VERSION 5.8 ;
BUSBITCHARS "[]" ;
DIVIDERCHAR "/" ;
UNITS
    DATABASE MICRONS 1000 ;
END UNITS

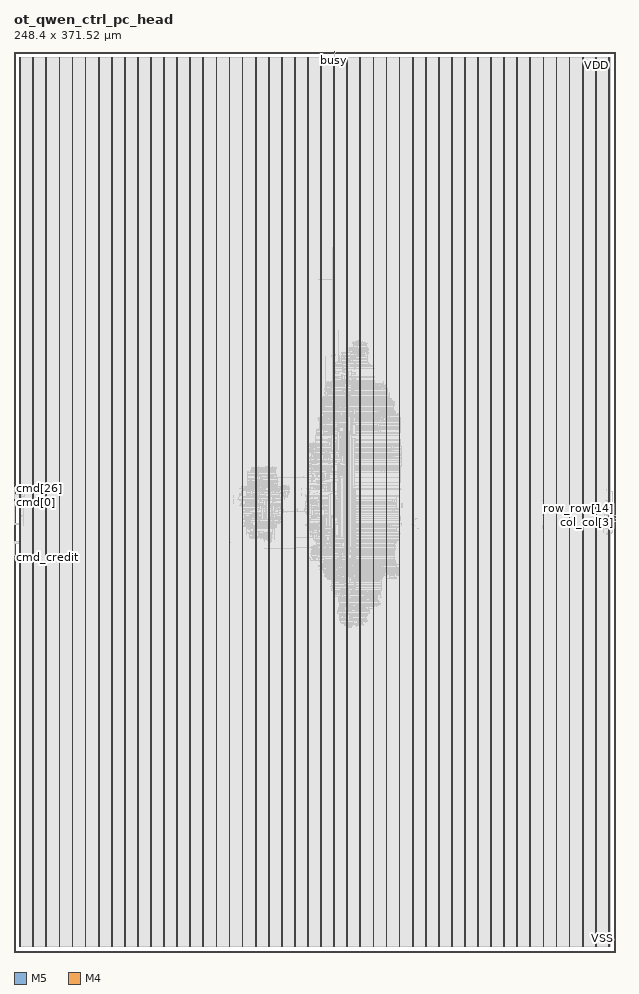
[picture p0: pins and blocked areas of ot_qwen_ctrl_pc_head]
MACRO ot_qwen_ctrl_pc_head
  FOREIGN ot_qwen_ctrl_pc_head 0 0 ;
  CLASS BLOCK ;
  SIZE 248.4 BY 371.52 ;
  PIN busy
    DIRECTION OUTPUT ;
    USE SIGNAL ;
    PORT
      LAYER M5 ;
        RECT  132.144 371.436 132.168 371.52 ;
    END
  END busy
  PIN clk
    DIRECTION INPUT ;
    USE SIGNAL ;
    PORT
      LAYER M5 ;
        RECT  132.24 371.436 132.264 371.52 ;
    END
  END clk
  PIN cmd[0]
    DIRECTION INPUT ;
    USE SIGNAL ;
    PORT
      LAYER M4 ;
        RECT  0 185.712 0.084 185.736 ;
    END
  END cmd[0]
  PIN cmd[10]
    DIRECTION INPUT ;
    USE SIGNAL ;
    PORT
      LAYER M4 ;
        RECT  0 186.672 0.084 186.696 ;
    END
  END cmd[10]
  PIN cmd[11]
    DIRECTION INPUT ;
    USE SIGNAL ;
    PORT
      LAYER M4 ;
        RECT  0 186.768 0.084 186.792 ;
    END
  END cmd[11]
  PIN cmd[12]
    DIRECTION INPUT ;
    USE SIGNAL ;
    PORT
      LAYER M4 ;
        RECT  0 186.864 0.084 186.888 ;
    END
  END cmd[12]
  PIN cmd[13]
    DIRECTION INPUT ;
    USE SIGNAL ;
    PORT
      LAYER M4 ;
        RECT  0 186.96 0.084 186.984 ;
    END
  END cmd[13]
  PIN cmd[14]
    DIRECTION INPUT ;
    USE SIGNAL ;
    PORT
      LAYER M4 ;
        RECT  0 187.056 0.084 187.08 ;
    END
  END cmd[14]
  PIN cmd[15]
    DIRECTION INPUT ;
    USE SIGNAL ;
    PORT
      LAYER M4 ;
        RECT  0 187.152 0.084 187.176 ;
    END
  END cmd[15]
  PIN cmd[16]
    DIRECTION INPUT ;
    USE SIGNAL ;
    PORT
      LAYER M4 ;
        RECT  0 187.248 0.084 187.272 ;
    END
  END cmd[16]
  PIN cmd[17]
    DIRECTION INPUT ;
    USE SIGNAL ;
    PORT
      LAYER M4 ;
        RECT  0 187.344 0.084 187.368 ;
    END
  END cmd[17]
  PIN cmd[18]
    DIRECTION INPUT ;
    USE SIGNAL ;
    PORT
      LAYER M4 ;
        RECT  0 187.44 0.084 187.464 ;
    END
  END cmd[18]
  PIN cmd[19]
    DIRECTION INPUT ;
    USE SIGNAL ;
    PORT
      LAYER M4 ;
        RECT  0 187.536 0.084 187.56 ;
    END
  END cmd[19]
  PIN cmd[1]
    DIRECTION INPUT ;
    USE SIGNAL ;
    PORT
      LAYER M4 ;
        RECT  0 185.808 0.084 185.832 ;
    END
  END cmd[1]
  PIN cmd[20]
    DIRECTION INPUT ;
    USE SIGNAL ;
    PORT
      LAYER M4 ;
        RECT  0 187.632 0.084 187.656 ;
    END
  END cmd[20]
  PIN cmd[21]
    DIRECTION INPUT ;
    USE SIGNAL ;
    PORT
      LAYER M4 ;
        RECT  0 187.728 0.084 187.752 ;
    END
  END cmd[21]
  PIN cmd[22]
    DIRECTION INPUT ;
    USE SIGNAL ;
    PORT
      LAYER M4 ;
        RECT  0 187.824 0.084 187.848 ;
    END
  END cmd[22]
  PIN cmd[23]
    DIRECTION INPUT ;
    USE SIGNAL ;
    PORT
      LAYER M4 ;
        RECT  0 187.92 0.084 187.944 ;
    END
  END cmd[23]
  PIN cmd[24]
    DIRECTION INPUT ;
    USE SIGNAL ;
    PORT
      LAYER M4 ;
        RECT  0 188.016 0.084 188.04 ;
    END
  END cmd[24]
  PIN cmd[25]
    DIRECTION INPUT ;
    USE SIGNAL ;
    PORT
      LAYER M4 ;
        RECT  0 188.112 0.084 188.136 ;
    END
  END cmd[25]
  PIN cmd[26]
    DIRECTION INPUT ;
    USE SIGNAL ;
    PORT
      LAYER M4 ;
        RECT  0 188.208 0.084 188.232 ;
    END
  END cmd[26]
  PIN cmd[27]
    DIRECTION INPUT ;
    USE SIGNAL ;
    PORT
      LAYER M4 ;
        RECT  0 188.304 0.084 188.328 ;
    END
  END cmd[27]
  PIN cmd[28]
    DIRECTION INPUT ;
    USE SIGNAL ;
    PORT
      LAYER M4 ;
        RECT  0 188.4 0.084 188.424 ;
    END
  END cmd[28]
  PIN cmd[29]
    DIRECTION INPUT ;
    USE SIGNAL ;
    PORT
      LAYER M4 ;
        RECT  0 188.496 0.084 188.52 ;
    END
  END cmd[29]
  PIN cmd[2]
    DIRECTION INPUT ;
    USE SIGNAL ;
    PORT
      LAYER M4 ;
        RECT  0 185.904 0.084 185.928 ;
    END
  END cmd[2]
  PIN cmd[30]
    DIRECTION INPUT ;
    USE SIGNAL ;
    PORT
      LAYER M4 ;
        RECT  0 188.592 0.084 188.616 ;
    END
  END cmd[30]
  PIN cmd[31]
    DIRECTION INPUT ;
    USE SIGNAL ;
    PORT
      LAYER M4 ;
        RECT  0 188.688 0.084 188.712 ;
    END
  END cmd[31]
  PIN cmd[3]
    DIRECTION INPUT ;
    USE SIGNAL ;
    PORT
      LAYER M4 ;
        RECT  0 186 0.084 186.024 ;
    END
  END cmd[3]
  PIN cmd[4]
    DIRECTION INPUT ;
    USE SIGNAL ;
    PORT
      LAYER M4 ;
        RECT  0 186.096 0.084 186.12 ;
    END
  END cmd[4]
  PIN cmd[5]
    DIRECTION INPUT ;
    USE SIGNAL ;
    PORT
      LAYER M4 ;
        RECT  0 186.192 0.084 186.216 ;
    END
  END cmd[5]
  PIN cmd[6]
    DIRECTION INPUT ;
    USE SIGNAL ;
    PORT
      LAYER M4 ;
        RECT  0 186.288 0.084 186.312 ;
    END
  END cmd[6]
  PIN cmd[7]
    DIRECTION INPUT ;
    USE SIGNAL ;
    PORT
      LAYER M4 ;
        RECT  0 186.384 0.084 186.408 ;
    END
  END cmd[7]
  PIN cmd[8]
    DIRECTION INPUT ;
    USE SIGNAL ;
    PORT
      LAYER M4 ;
        RECT  0 186.48 0.084 186.504 ;
    END
  END cmd[8]
  PIN cmd[9]
    DIRECTION INPUT ;
    USE SIGNAL ;
    PORT
      LAYER M4 ;
        RECT  0 186.576 0.084 186.6 ;
    END
  END cmd[9]
  PIN cmd_credit
    DIRECTION OUTPUT ;
    USE SIGNAL ;
    PORT
      LAYER M4 ;
        RECT  0 162.96 0.084 162.984 ;
    END
  END cmd_credit
  PIN cmd_v
    DIRECTION INPUT ;
    USE SIGNAL ;
    PORT
      LAYER M4 ;
        RECT  0 163.056 0.084 163.08 ;
    END
  END cmd_v
  PIN col_bank[0]
    DIRECTION OUTPUT ;
    USE SIGNAL ;
    PORT
      LAYER M4 ;
        RECT  248.316 176.592 248.4 176.616 ;
    END
  END col_bank[0]
  PIN col_bank[1]
    DIRECTION OUTPUT ;
    USE SIGNAL ;
    PORT
      LAYER M4 ;
        RECT  248.316 176.688 248.4 176.712 ;
    END
  END col_bank[1]
  PIN col_bank[2]
    DIRECTION OUTPUT ;
    USE SIGNAL ;
    PORT
      LAYER M4 ;
        RECT  248.316 176.784 248.4 176.808 ;
    END
  END col_bank[2]
  PIN col_bank[3]
    DIRECTION OUTPUT ;
    USE SIGNAL ;
    PORT
      LAYER M4 ;
        RECT  248.316 176.88 248.4 176.904 ;
    END
  END col_bank[3]
  PIN col_bank[4]
    DIRECTION OUTPUT ;
    USE SIGNAL ;
    PORT
      LAYER M4 ;
        RECT  248.316 176.976 248.4 177 ;
    END
  END col_bank[4]
  PIN col_col[0]
    DIRECTION OUTPUT ;
    USE SIGNAL ;
    PORT
      LAYER M4 ;
        RECT  248.316 177.072 248.4 177.096 ;
    END
  END col_col[0]
  PIN col_col[1]
    DIRECTION OUTPUT ;
    USE SIGNAL ;
    PORT
      LAYER M4 ;
        RECT  248.316 177.168 248.4 177.192 ;
    END
  END col_col[1]
  PIN col_col[2]
    DIRECTION OUTPUT ;
    USE SIGNAL ;
    PORT
      LAYER M4 ;
        RECT  248.316 177.264 248.4 177.288 ;
    END
  END col_col[2]
  PIN col_col[3]
    DIRECTION OUTPUT ;
    USE SIGNAL ;
    PORT
      LAYER M4 ;
        RECT  248.316 177.36 248.4 177.384 ;
    END
  END col_col[3]
  PIN col_col[4]
    DIRECTION OUTPUT ;
    USE SIGNAL ;
    PORT
      LAYER M4 ;
        RECT  248.316 177.456 248.4 177.48 ;
    END
  END col_col[4]
  PIN col_v
    DIRECTION OUTPUT ;
    USE SIGNAL ;
    PORT
      LAYER M4 ;
        RECT  248.316 177.552 248.4 177.576 ;
    END
  END col_v
  PIN col_we
    DIRECTION OUTPUT ;
    USE SIGNAL ;
    PORT
      LAYER M4 ;
        RECT  248.316 177.648 248.4 177.672 ;
    END
  END col_we
  PIN fault
    DIRECTION OUTPUT ;
    USE SIGNAL ;
    PORT
      LAYER M5 ;
        RECT  132.336 371.436 132.36 371.52 ;
    END
  END fault
  PIN read_credit[0]
    DIRECTION INPUT ;
    USE SIGNAL ;
    PORT
      LAYER M4 ;
        RECT  0 163.152 0.084 163.176 ;
    END
  END read_credit[0]
  PIN read_credit[1]
    DIRECTION INPUT ;
    USE SIGNAL ;
    PORT
      LAYER M4 ;
        RECT  0 163.248 0.084 163.272 ;
    END
  END read_credit[1]
  PIN read_credit[2]
    DIRECTION INPUT ;
    USE SIGNAL ;
    PORT
      LAYER M4 ;
        RECT  0 163.344 0.084 163.368 ;
    END
  END read_credit[2]
  PIN row_bank[0]
    DIRECTION OUTPUT ;
    USE SIGNAL ;
    PORT
      LAYER M4 ;
        RECT  248.316 177.744 248.4 177.768 ;
    END
  END row_bank[0]
  PIN row_bank[1]
    DIRECTION OUTPUT ;
    USE SIGNAL ;
    PORT
      LAYER M4 ;
        RECT  248.316 177.84 248.4 177.864 ;
    END
  END row_bank[1]
  PIN row_bank[2]
    DIRECTION OUTPUT ;
    USE SIGNAL ;
    PORT
      LAYER M4 ;
        RECT  248.316 177.936 248.4 177.96 ;
    END
  END row_bank[2]
  PIN row_bank[3]
    DIRECTION OUTPUT ;
    USE SIGNAL ;
    PORT
      LAYER M4 ;
        RECT  248.316 178.032 248.4 178.056 ;
    END
  END row_bank[3]
  PIN row_bank[4]
    DIRECTION OUTPUT ;
    USE SIGNAL ;
    PORT
      LAYER M4 ;
        RECT  248.316 178.128 248.4 178.152 ;
    END
  END row_bank[4]
  PIN row_op[0]
    DIRECTION OUTPUT ;
    USE SIGNAL ;
    PORT
      LAYER M4 ;
        RECT  248.316 178.224 248.4 178.248 ;
    END
  END row_op[0]
  PIN row_op[1]
    DIRECTION OUTPUT ;
    USE SIGNAL ;
    PORT
      LAYER M4 ;
        RECT  248.316 178.32 248.4 178.344 ;
    END
  END row_op[1]
  PIN row_op[2]
    DIRECTION OUTPUT ;
    USE SIGNAL ;
    PORT
      LAYER M4 ;
        RECT  248.316 178.416 248.4 178.44 ;
    END
  END row_op[2]
  PIN row_row[0]
    DIRECTION OUTPUT ;
    USE SIGNAL ;
    PORT
      LAYER M4 ;
        RECT  248.316 178.512 248.4 178.536 ;
    END
  END row_row[0]
  PIN row_row[10]
    DIRECTION OUTPUT ;
    USE SIGNAL ;
    PORT
      LAYER M4 ;
        RECT  248.316 179.472 248.4 179.496 ;
    END
  END row_row[10]
  PIN row_row[11]
    DIRECTION OUTPUT ;
    USE SIGNAL ;
    PORT
      LAYER M4 ;
        RECT  248.316 179.568 248.4 179.592 ;
    END
  END row_row[11]
  PIN row_row[12]
    DIRECTION OUTPUT ;
    USE SIGNAL ;
    PORT
      LAYER M4 ;
        RECT  248.316 179.664 248.4 179.688 ;
    END
  END row_row[12]
  PIN row_row[13]
    DIRECTION OUTPUT ;
    USE SIGNAL ;
    PORT
      LAYER M4 ;
        RECT  248.316 179.76 248.4 179.784 ;
    END
  END row_row[13]
  PIN row_row[14]
    DIRECTION OUTPUT ;
    USE SIGNAL ;
    PORT
      LAYER M4 ;
        RECT  248.316 179.856 248.4 179.88 ;
    END
  END row_row[14]
  PIN row_row[15]
    DIRECTION OUTPUT ;
    USE SIGNAL ;
    PORT
      LAYER M4 ;
        RECT  248.316 179.952 248.4 179.976 ;
    END
  END row_row[15]
  PIN row_row[16]
    DIRECTION OUTPUT ;
    USE SIGNAL ;
    PORT
      LAYER M4 ;
        RECT  248.316 180.048 248.4 180.072 ;
    END
  END row_row[16]
  PIN row_row[17]
    DIRECTION OUTPUT ;
    USE SIGNAL ;
    PORT
      LAYER M4 ;
        RECT  248.316 180.144 248.4 180.168 ;
    END
  END row_row[17]
  PIN row_row[18]
    DIRECTION OUTPUT ;
    USE SIGNAL ;
    PORT
      LAYER M4 ;
        RECT  248.316 180.24 248.4 180.264 ;
    END
  END row_row[18]
  PIN row_row[1]
    DIRECTION OUTPUT ;
    USE SIGNAL ;
    PORT
      LAYER M4 ;
        RECT  248.316 178.608 248.4 178.632 ;
    END
  END row_row[1]
  PIN row_row[2]
    DIRECTION OUTPUT ;
    USE SIGNAL ;
    PORT
      LAYER M4 ;
        RECT  248.316 178.704 248.4 178.728 ;
    END
  END row_row[2]
  PIN row_row[3]
    DIRECTION OUTPUT ;
    USE SIGNAL ;
    PORT
      LAYER M4 ;
        RECT  248.316 178.8 248.4 178.824 ;
    END
  END row_row[3]
  PIN row_row[4]
    DIRECTION OUTPUT ;
    USE SIGNAL ;
    PORT
      LAYER M4 ;
        RECT  248.316 178.896 248.4 178.92 ;
    END
  END row_row[4]
  PIN row_row[5]
    DIRECTION OUTPUT ;
    USE SIGNAL ;
    PORT
      LAYER M4 ;
        RECT  248.316 178.992 248.4 179.016 ;
    END
  END row_row[5]
  PIN row_row[6]
    DIRECTION OUTPUT ;
    USE SIGNAL ;
    PORT
      LAYER M4 ;
        RECT  248.316 179.088 248.4 179.112 ;
    END
  END row_row[6]
  PIN row_row[7]
    DIRECTION OUTPUT ;
    USE SIGNAL ;
    PORT
      LAYER M4 ;
        RECT  248.316 179.184 248.4 179.208 ;
    END
  END row_row[7]
  PIN row_row[8]
    DIRECTION OUTPUT ;
    USE SIGNAL ;
    PORT
      LAYER M4 ;
        RECT  248.316 179.28 248.4 179.304 ;
    END
  END row_row[8]
  PIN row_row[9]
    DIRECTION OUTPUT ;
    USE SIGNAL ;
    PORT
      LAYER M4 ;
        RECT  248.316 179.376 248.4 179.4 ;
    END
  END row_row[9]
  PIN row_v
    DIRECTION OUTPUT ;
    USE SIGNAL ;
    PORT
      LAYER M4 ;
        RECT  248.316 180.336 248.4 180.36 ;
    END
  END row_v
  PIN rst_n
    DIRECTION INPUT ;
    USE SIGNAL ;
    PORT
      LAYER M5 ;
        RECT  132.432 371.436 132.456 371.52 ;
    END
  END rst_n
  PIN VDD
    DIRECTION INOUT ;
    USE POWER ;
    PORT
      LAYER M5 ;
        RECT  245.592 2.151 245.712 369.369 ;
        RECT  240.192 2.151 240.312 369.369 ;
        RECT  234.792 2.151 234.912 369.369 ;
        RECT  229.392 2.151 229.512 369.369 ;
        RECT  223.992 2.151 224.112 369.369 ;
        RECT  218.592 2.151 218.712 369.369 ;
        RECT  213.192 2.151 213.312 369.369 ;
        RECT  207.792 2.151 207.912 369.369 ;
        RECT  202.392 2.151 202.512 369.369 ;
        RECT  196.992 2.151 197.112 369.369 ;
        RECT  191.592 2.151 191.712 369.369 ;
        RECT  186.192 2.151 186.312 369.369 ;
        RECT  180.792 2.151 180.912 369.369 ;
        RECT  175.392 2.151 175.512 369.369 ;
        RECT  169.992 2.151 170.112 369.369 ;
        RECT  164.592 2.151 164.712 369.369 ;
        RECT  159.192 2.151 159.312 369.369 ;
        RECT  153.792 2.151 153.912 369.369 ;
        RECT  148.392 2.151 148.512 369.369 ;
        RECT  142.992 2.151 143.112 369.369 ;
        RECT  137.592 2.151 137.712 369.369 ;
        RECT  132.192 2.151 132.312 369.369 ;
        RECT  126.792 2.151 126.912 369.369 ;
        RECT  121.392 2.151 121.512 369.369 ;
        RECT  115.992 2.151 116.112 369.369 ;
        RECT  110.592 2.151 110.712 369.369 ;
        RECT  105.192 2.151 105.312 369.369 ;
        RECT  99.792 2.151 99.912 369.369 ;
        RECT  94.392 2.151 94.512 369.369 ;
        RECT  88.992 2.151 89.112 369.369 ;
        RECT  83.592 2.151 83.712 369.369 ;
        RECT  78.192 2.151 78.312 369.369 ;
        RECT  72.792 2.151 72.912 369.369 ;
        RECT  67.392 2.151 67.512 369.369 ;
        RECT  61.992 2.151 62.112 369.369 ;
        RECT  56.592 2.151 56.712 369.369 ;
        RECT  51.192 2.151 51.312 369.369 ;
        RECT  45.792 2.151 45.912 369.369 ;
        RECT  40.392 2.151 40.512 369.369 ;
        RECT  34.992 2.151 35.112 369.369 ;
        RECT  29.592 2.151 29.712 369.369 ;
        RECT  24.192 2.151 24.312 369.369 ;
        RECT  18.792 2.151 18.912 369.369 ;
        RECT  13.392 2.151 13.512 369.369 ;
        RECT  7.992 2.151 8.112 369.369 ;
        RECT  2.592 2.151 2.712 369.369 ;
    END
  END VDD
  PIN VSS
    DIRECTION INOUT ;
    USE GROUND ;
    PORT
      LAYER M5 ;
        RECT  245.4 2.137 245.52 369.383 ;
        RECT  240 2.137 240.12 369.383 ;
        RECT  234.6 2.137 234.72 369.383 ;
        RECT  229.2 2.137 229.32 369.383 ;
        RECT  223.8 2.137 223.92 369.383 ;
        RECT  218.4 2.137 218.52 369.383 ;
        RECT  213 2.137 213.12 369.383 ;
        RECT  207.6 2.137 207.72 369.383 ;
        RECT  202.2 2.137 202.32 369.383 ;
        RECT  196.8 2.137 196.92 369.383 ;
        RECT  191.4 2.137 191.52 369.383 ;
        RECT  186 2.137 186.12 369.383 ;
        RECT  180.6 2.137 180.72 369.383 ;
        RECT  175.2 2.137 175.32 369.383 ;
        RECT  169.8 2.137 169.92 369.383 ;
        RECT  164.4 2.137 164.52 369.383 ;
        RECT  159 2.137 159.12 369.383 ;
        RECT  153.6 2.137 153.72 369.383 ;
        RECT  148.2 2.137 148.32 369.383 ;
        RECT  142.8 2.137 142.92 369.383 ;
        RECT  137.4 2.137 137.52 369.383 ;
        RECT  132 2.137 132.12 369.383 ;
        RECT  126.6 2.137 126.72 369.383 ;
        RECT  121.2 2.137 121.32 369.383 ;
        RECT  115.8 2.137 115.92 369.383 ;
        RECT  110.4 2.137 110.52 369.383 ;
        RECT  105 2.137 105.12 369.383 ;
        RECT  99.6 2.137 99.72 369.383 ;
        RECT  94.2 2.137 94.32 369.383 ;
        RECT  88.8 2.137 88.92 369.383 ;
        RECT  83.4 2.137 83.52 369.383 ;
        RECT  78 2.137 78.12 369.383 ;
        RECT  72.6 2.137 72.72 369.383 ;
        RECT  67.2 2.137 67.32 369.383 ;
        RECT  61.8 2.137 61.92 369.383 ;
        RECT  56.4 2.137 56.52 369.383 ;
        RECT  51 2.137 51.12 369.383 ;
        RECT  45.6 2.137 45.72 369.383 ;
        RECT  40.2 2.137 40.32 369.383 ;
        RECT  34.8 2.137 34.92 369.383 ;
        RECT  29.4 2.137 29.52 369.383 ;
        RECT  24 2.137 24.12 369.383 ;
        RECT  18.6 2.137 18.72 369.383 ;
        RECT  13.2 2.137 13.32 369.383 ;
        RECT  7.8 2.137 7.92 369.383 ;
        RECT  2.4 2.137 2.52 369.383 ;
    END
  END VSS
  OBS
    LAYER RVTN ;
     RECT  2.16 2.16 246.24 2.295 ;
     RECT  2.16 2.565 246.24 2.835 ;
     RECT  2.16 3.105 246.24 3.375 ;
     RECT  2.16 3.645 246.24 3.915 ;
     RECT  2.16 4.185 246.24 4.455 ;
     RECT  2.16 4.725 246.24 4.995 ;
     RECT  2.16 5.265 246.24 5.535 ;
     RECT  2.16 5.805 246.24 6.075 ;
     RECT  2.16 6.345 246.24 6.615 ;
     RECT  2.16 6.885 246.24 7.155 ;
     RECT  2.16 7.425 246.24 7.695 ;
     RECT  2.16 7.965 246.24 8.235 ;
     RECT  2.16 8.505 246.24 8.775 ;
     RECT  2.16 9.045 246.24 9.315 ;
     RECT  2.16 9.585 246.24 9.855 ;
     RECT  2.16 10.125 246.24 10.395 ;
     RECT  2.16 10.665 246.24 10.935 ;
     RECT  2.16 11.205 246.24 11.475 ;
     RECT  2.16 11.745 246.24 12.015 ;
     RECT  2.16 12.285 246.24 12.555 ;
     RECT  2.16 12.825 246.24 13.095 ;
     RECT  2.16 13.365 246.24 13.635 ;
     RECT  2.16 13.905 246.24 14.175 ;
     RECT  2.16 14.445 246.24 14.715 ;
     RECT  2.16 14.985 246.24 15.255 ;
     RECT  2.16 15.525 246.24 15.795 ;
     RECT  2.16 16.065 246.24 16.335 ;
     RECT  2.16 16.605 246.24 16.875 ;
     RECT  2.16 17.145 246.24 17.415 ;
     RECT  2.16 17.685 246.24 17.955 ;
     RECT  2.16 18.225 246.24 18.495 ;
     RECT  2.16 18.765 246.24 19.035 ;
     RECT  2.16 19.305 246.24 19.575 ;
     RECT  2.16 19.845 246.24 20.115 ;
     RECT  2.16 20.385 246.24 20.655 ;
     RECT  2.16 20.925 246.24 21.195 ;
     RECT  2.16 21.465 246.24 21.735 ;
     RECT  2.16 22.005 246.24 22.275 ;
     RECT  2.16 22.545 246.24 22.815 ;
     RECT  2.16 23.085 246.24 23.355 ;
     RECT  2.16 23.625 246.24 23.895 ;
     RECT  2.16 24.165 246.24 24.435 ;
     RECT  2.16 24.705 246.24 24.975 ;
     RECT  2.16 25.245 246.24 25.515 ;
     RECT  2.16 25.785 246.24 26.055 ;
     RECT  2.16 26.325 246.24 26.595 ;
     RECT  2.16 26.865 246.24 27.135 ;
     RECT  2.16 27.405 246.24 27.675 ;
     RECT  2.16 27.945 246.24 28.215 ;
     RECT  2.16 28.485 246.24 28.755 ;
     RECT  2.16 29.025 246.24 29.295 ;
     RECT  2.16 29.565 246.24 29.835 ;
     RECT  2.16 30.105 246.24 30.375 ;
     RECT  2.16 30.645 246.24 30.915 ;
     RECT  2.16 31.185 246.24 31.455 ;
     RECT  2.16 31.725 246.24 31.995 ;
     RECT  2.16 32.265 246.24 32.535 ;
     RECT  2.16 32.805 246.24 33.075 ;
     RECT  2.16 33.345 246.24 33.615 ;
     RECT  2.16 33.885 246.24 34.155 ;
     RECT  2.16 34.425 246.24 34.695 ;
     RECT  2.16 34.965 246.24 35.235 ;
     RECT  2.16 35.505 246.24 35.775 ;
     RECT  2.16 36.045 246.24 36.315 ;
     RECT  2.16 36.585 246.24 36.855 ;
     RECT  2.16 37.125 246.24 37.395 ;
     RECT  2.16 37.665 246.24 37.935 ;
     RECT  2.16 38.205 246.24 38.475 ;
     RECT  2.16 38.745 246.24 39.015 ;
     RECT  2.16 39.285 246.24 39.555 ;
     RECT  2.16 39.825 246.24 40.095 ;
     RECT  2.16 40.365 246.24 40.635 ;
     RECT  2.16 40.905 246.24 41.175 ;
     RECT  2.16 41.445 246.24 41.715 ;
     RECT  2.16 41.985 246.24 42.255 ;
     RECT  2.16 42.525 246.24 42.795 ;
     RECT  2.16 43.065 246.24 43.335 ;
     RECT  2.16 43.605 246.24 43.875 ;
     RECT  2.16 44.145 246.24 44.415 ;
     RECT  2.16 44.685 246.24 44.955 ;
     RECT  2.16 45.225 246.24 45.495 ;
     RECT  2.16 45.765 246.24 46.035 ;
     RECT  2.16 46.305 246.24 46.575 ;
     RECT  2.16 46.845 246.24 47.115 ;
     RECT  2.16 47.385 246.24 47.655 ;
     RECT  2.16 47.925 246.24 48.195 ;
     RECT  2.16 48.465 246.24 48.735 ;
     RECT  2.16 49.005 246.24 49.275 ;
     RECT  2.16 49.545 246.24 49.815 ;
     RECT  2.16 50.085 246.24 50.355 ;
     RECT  2.16 50.625 246.24 50.895 ;
     RECT  2.16 51.165 246.24 51.435 ;
     RECT  2.16 51.705 246.24 51.975 ;
     RECT  2.16 52.245 246.24 52.515 ;
     RECT  2.16 52.785 246.24 53.055 ;
     RECT  2.16 53.325 246.24 53.595 ;
     RECT  2.16 53.865 246.24 54.135 ;
     RECT  2.16 54.405 246.24 54.675 ;
     RECT  2.16 54.945 246.24 55.215 ;
     RECT  2.16 55.485 246.24 55.755 ;
     RECT  2.16 56.025 246.24 56.295 ;
     RECT  2.16 56.565 246.24 56.835 ;
     RECT  2.16 57.105 246.24 57.375 ;
     RECT  2.16 57.645 246.24 57.915 ;
     RECT  2.16 58.185 246.24 58.455 ;
     RECT  2.16 58.725 246.24 58.995 ;
     RECT  2.16 59.265 246.24 59.535 ;
     RECT  2.16 59.805 246.24 60.075 ;
     RECT  2.16 60.345 246.24 60.615 ;
     RECT  2.16 60.885 246.24 61.155 ;
     RECT  2.16 61.425 246.24 61.695 ;
     RECT  2.16 61.965 246.24 62.235 ;
     RECT  2.16 62.505 246.24 62.775 ;
     RECT  2.16 63.045 246.24 63.315 ;
     RECT  2.16 63.585 246.24 63.855 ;
     RECT  2.16 64.125 246.24 64.395 ;
     RECT  2.16 64.665 246.24 64.935 ;
     RECT  2.16 65.205 246.24 65.475 ;
     RECT  2.16 65.745 246.24 66.015 ;
     RECT  2.16 66.285 246.24 66.555 ;
     RECT  2.16 66.825 246.24 67.095 ;
     RECT  2.16 67.365 246.24 67.635 ;
     RECT  2.16 67.905 246.24 68.175 ;
     RECT  2.16 68.445 246.24 68.715 ;
     RECT  2.16 68.985 246.24 69.255 ;
     RECT  2.16 69.525 246.24 69.795 ;
     RECT  2.16 70.065 246.24 70.335 ;
     RECT  2.16 70.605 246.24 70.875 ;
     RECT  2.16 71.145 246.24 71.415 ;
     RECT  2.16 71.685 246.24 71.955 ;
     RECT  2.16 72.225 246.24 72.495 ;
     RECT  2.16 72.765 246.24 73.035 ;
     RECT  2.16 73.305 246.24 73.575 ;
     RECT  2.16 73.845 246.24 74.115 ;
     RECT  2.16 74.385 246.24 74.655 ;
     RECT  2.16 74.925 246.24 75.195 ;
     RECT  2.16 75.465 246.24 75.735 ;
     RECT  2.16 76.005 246.24 76.275 ;
     RECT  2.16 76.545 246.24 76.815 ;
     RECT  2.16 77.085 246.24 77.355 ;
     RECT  2.16 77.625 246.24 77.895 ;
     RECT  2.16 78.165 246.24 78.435 ;
     RECT  2.16 78.705 246.24 78.975 ;
     RECT  2.16 79.245 246.24 79.515 ;
     RECT  2.16 79.785 246.24 80.055 ;
     RECT  2.16 80.325 246.24 80.595 ;
     RECT  2.16 80.865 246.24 81.135 ;
     RECT  2.16 81.405 246.24 81.675 ;
     RECT  2.16 81.945 246.24 82.215 ;
     RECT  2.16 82.485 246.24 82.755 ;
     RECT  2.16 83.025 246.24 83.295 ;
     RECT  2.16 83.565 246.24 83.835 ;
     RECT  2.16 84.105 246.24 84.375 ;
     RECT  2.16 84.645 246.24 84.915 ;
     RECT  2.16 85.185 246.24 85.455 ;
     RECT  2.16 85.725 246.24 85.995 ;
     RECT  2.16 86.265 246.24 86.535 ;
     RECT  2.16 86.805 246.24 87.075 ;
     RECT  2.16 87.345 246.24 87.615 ;
     RECT  2.16 87.885 246.24 88.155 ;
     RECT  2.16 88.425 246.24 88.695 ;
     RECT  2.16 88.965 246.24 89.235 ;
     RECT  2.16 89.505 246.24 89.775 ;
     RECT  2.16 90.045 246.24 90.315 ;
     RECT  2.16 90.585 246.24 90.855 ;
     RECT  2.16 91.125 246.24 91.395 ;
     RECT  2.16 91.665 246.24 91.935 ;
     RECT  2.16 92.205 246.24 92.475 ;
     RECT  2.16 92.745 246.24 93.015 ;
     RECT  2.16 93.285 246.24 93.555 ;
     RECT  2.16 93.825 246.24 94.095 ;
     RECT  2.16 94.365 246.24 94.635 ;
     RECT  2.16 94.905 246.24 95.175 ;
     RECT  2.16 95.445 246.24 95.715 ;
     RECT  2.16 95.985 246.24 96.255 ;
     RECT  2.16 96.525 246.24 96.795 ;
     RECT  2.16 97.065 246.24 97.335 ;
     RECT  2.16 97.605 246.24 97.875 ;
     RECT  2.16 98.145 246.24 98.415 ;
     RECT  2.16 98.685 246.24 98.955 ;
     RECT  2.16 99.225 246.24 99.495 ;
     RECT  2.16 99.765 246.24 100.035 ;
     RECT  2.16 100.305 246.24 100.575 ;
     RECT  2.16 100.845 246.24 101.115 ;
     RECT  2.16 101.385 246.24 101.655 ;
     RECT  2.16 101.925 246.24 102.195 ;
     RECT  2.16 102.465 246.24 102.735 ;
     RECT  2.16 103.005 246.24 103.275 ;
     RECT  2.16 103.545 246.24 103.815 ;
     RECT  2.16 104.085 246.24 104.355 ;
     RECT  2.16 104.625 246.24 104.895 ;
     RECT  2.16 105.165 246.24 105.435 ;
     RECT  2.16 105.705 246.24 105.975 ;
     RECT  2.16 106.245 246.24 106.515 ;
     RECT  2.16 106.785 246.24 107.055 ;
     RECT  2.16 107.325 246.24 107.595 ;
     RECT  2.16 107.865 246.24 108.135 ;
     RECT  2.16 108.405 246.24 108.675 ;
     RECT  2.16 108.945 246.24 109.215 ;
     RECT  2.16 109.485 246.24 109.755 ;
     RECT  2.16 110.025 246.24 110.295 ;
     RECT  2.16 110.565 246.24 110.835 ;
     RECT  2.16 111.105 246.24 111.375 ;
     RECT  2.16 111.645 246.24 111.915 ;
     RECT  2.16 112.185 246.24 112.455 ;
     RECT  2.16 112.725 246.24 112.995 ;
     RECT  2.16 113.265 246.24 113.535 ;
     RECT  2.16 113.805 246.24 114.075 ;
     RECT  2.16 114.345 246.24 114.615 ;
     RECT  2.16 114.885 246.24 115.155 ;
     RECT  2.16 115.425 246.24 115.695 ;
     RECT  2.16 115.965 246.24 116.235 ;
     RECT  2.16 116.505 246.24 116.775 ;
     RECT  2.16 117.045 246.24 117.315 ;
     RECT  2.16 117.585 246.24 117.855 ;
     RECT  2.16 118.125 246.24 118.395 ;
     RECT  2.16 118.665 246.24 118.935 ;
     RECT  2.16 119.205 246.24 119.475 ;
     RECT  2.16 119.745 246.24 120.015 ;
     RECT  2.16 120.285 246.24 120.555 ;
     RECT  2.16 120.825 246.24 121.095 ;
     RECT  2.16 121.365 246.24 121.635 ;
     RECT  2.16 121.905 246.24 122.175 ;
     RECT  2.16 122.445 246.24 122.715 ;
     RECT  2.16 122.985 246.24 123.255 ;
     RECT  2.16 123.525 246.24 123.795 ;
     RECT  2.16 124.065 246.24 124.335 ;
     RECT  2.16 124.605 246.24 124.875 ;
     RECT  2.16 125.145 246.24 125.415 ;
     RECT  2.16 125.685 246.24 125.955 ;
     RECT  2.16 126.225 246.24 126.495 ;
     RECT  2.16 126.765 246.24 127.035 ;
     RECT  2.16 127.305 246.24 127.575 ;
     RECT  2.16 127.845 246.24 128.115 ;
     RECT  2.16 128.385 246.24 128.655 ;
     RECT  2.16 128.925 246.24 129.195 ;
     RECT  2.16 129.465 246.24 129.735 ;
     RECT  2.16 130.005 246.24 130.275 ;
     RECT  2.16 130.545 246.24 130.815 ;
     RECT  2.16 131.085 246.24 131.355 ;
     RECT  2.16 131.625 246.24 131.895 ;
     RECT  2.16 132.165 246.24 132.435 ;
     RECT  2.16 132.705 246.24 132.975 ;
     RECT  2.16 133.245 246.24 133.515 ;
     RECT  2.16 133.785 246.24 134.055 ;
     RECT  2.16 134.325 246.24 134.595 ;
     RECT  2.16 134.865 246.24 135.135 ;
     RECT  2.16 135.405 246.24 135.675 ;
     RECT  2.16 135.945 246.24 136.215 ;
     RECT  2.16 136.485 246.24 136.755 ;
     RECT  2.16 137.025 246.24 137.295 ;
     RECT  2.16 137.565 246.24 137.835 ;
     RECT  2.16 138.105 246.24 138.375 ;
     RECT  2.16 138.645 246.24 138.915 ;
     RECT  2.16 139.185 246.24 139.455 ;
     RECT  2.16 139.725 246.24 139.995 ;
     RECT  2.16 140.265 246.24 140.535 ;
     RECT  2.16 140.805 246.24 141.075 ;
     RECT  2.16 141.345 246.24 141.615 ;
     RECT  2.16 141.885 246.24 142.155 ;
     RECT  2.16 142.425 246.24 142.695 ;
     RECT  2.16 142.965 246.24 143.235 ;
     RECT  2.16 143.505 246.24 143.775 ;
     RECT  2.16 144.045 246.24 144.315 ;
     RECT  2.16 144.585 246.24 144.855 ;
     RECT  2.16 145.125 246.24 145.395 ;
     RECT  2.16 145.665 246.24 145.935 ;
     RECT  2.16 146.205 246.24 146.475 ;
     RECT  2.16 146.745 246.24 147.015 ;
     RECT  2.16 147.285 246.24 147.555 ;
     RECT  2.16 147.825 246.24 148.095 ;
     RECT  2.16 148.365 246.24 148.635 ;
     RECT  2.16 148.905 246.24 149.175 ;
     RECT  2.16 149.445 246.24 149.715 ;
     RECT  2.16 149.985 246.24 150.255 ;
     RECT  2.16 150.525 246.24 150.795 ;
     RECT  2.16 151.065 246.24 151.335 ;
     RECT  2.16 151.605 246.24 151.875 ;
     RECT  2.16 152.145 246.24 152.415 ;
     RECT  2.16 152.685 246.24 152.955 ;
     RECT  2.16 153.225 246.24 153.495 ;
     RECT  2.16 153.765 246.24 154.035 ;
     RECT  2.16 154.305 246.24 154.575 ;
     RECT  2.16 154.845 246.24 155.115 ;
     RECT  2.16 155.385 246.24 155.655 ;
     RECT  2.16 155.925 246.24 156.195 ;
     RECT  2.16 156.465 246.24 156.735 ;
     RECT  2.16 157.005 246.24 157.275 ;
     RECT  2.16 157.545 246.24 157.815 ;
     RECT  2.16 158.085 246.24 158.355 ;
     RECT  2.16 158.625 246.24 158.895 ;
     RECT  2.16 159.165 246.24 159.435 ;
     RECT  2.16 159.705 246.24 159.975 ;
     RECT  2.16 160.245 246.24 160.515 ;
     RECT  2.16 160.785 246.24 161.055 ;
     RECT  2.16 161.325 246.24 161.595 ;
     RECT  2.16 161.865 246.24 162.135 ;
     RECT  2.16 162.405 246.24 162.675 ;
     RECT  2.16 162.945 246.24 163.215 ;
     RECT  2.16 163.485 246.24 163.755 ;
     RECT  2.16 164.025 246.24 164.295 ;
     RECT  2.16 164.565 246.24 164.835 ;
     RECT  2.16 165.105 246.24 165.375 ;
     RECT  2.16 165.645 246.24 165.915 ;
     RECT  2.16 166.185 246.24 166.455 ;
     RECT  2.16 166.725 246.24 166.995 ;
     RECT  2.16 167.265 246.24 167.535 ;
     RECT  2.16 167.805 246.24 168.075 ;
     RECT  2.16 168.345 246.24 168.615 ;
     RECT  2.16 168.885 246.24 169.155 ;
     RECT  2.16 169.425 246.24 169.695 ;
     RECT  2.16 169.965 246.24 170.235 ;
     RECT  2.16 170.505 246.24 170.775 ;
     RECT  2.16 171.045 246.24 171.315 ;
     RECT  2.16 171.585 246.24 171.855 ;
     RECT  2.16 172.125 246.24 172.395 ;
     RECT  2.16 172.665 246.24 172.935 ;
     RECT  2.16 173.205 246.24 173.475 ;
     RECT  2.16 173.745 246.24 174.015 ;
     RECT  2.16 174.285 246.24 174.555 ;
     RECT  2.16 174.825 246.24 175.095 ;
     RECT  2.16 175.365 246.24 175.635 ;
     RECT  2.16 175.905 246.24 176.175 ;
     RECT  2.16 176.445 246.24 176.715 ;
     RECT  2.16 176.985 246.24 177.255 ;
     RECT  2.16 177.525 246.24 177.795 ;
     RECT  2.16 178.065 246.24 178.335 ;
     RECT  2.16 178.605 246.24 178.875 ;
     RECT  2.16 179.145 246.24 179.415 ;
     RECT  2.16 179.685 246.24 179.955 ;
     RECT  2.16 180.225 246.24 180.495 ;
     RECT  2.16 180.765 246.24 181.035 ;
     RECT  2.16 181.305 246.24 181.575 ;
     RECT  2.16 181.845 246.24 182.115 ;
     RECT  2.16 182.385 246.24 182.655 ;
     RECT  2.16 182.925 246.24 183.195 ;
     RECT  2.16 183.465 246.24 183.735 ;
     RECT  2.16 184.005 246.24 184.275 ;
     RECT  2.16 184.545 246.24 184.815 ;
     RECT  2.16 185.085 246.24 185.355 ;
     RECT  2.16 185.625 246.24 185.895 ;
     RECT  2.16 186.165 246.24 186.435 ;
     RECT  2.16 186.705 246.24 186.975 ;
     RECT  2.16 187.245 246.24 187.515 ;
     RECT  2.16 187.785 246.24 188.055 ;
     RECT  2.16 188.325 246.24 188.595 ;
     RECT  2.16 188.865 246.24 189.135 ;
     RECT  2.16 189.405 246.24 189.675 ;
     RECT  2.16 189.945 246.24 190.215 ;
     RECT  2.16 190.485 246.24 190.755 ;
     RECT  2.16 191.025 246.24 191.295 ;
     RECT  2.16 191.565 246.24 191.835 ;
     RECT  2.16 192.105 246.24 192.375 ;
     RECT  2.16 192.645 246.24 192.915 ;
     RECT  2.16 193.185 246.24 193.455 ;
     RECT  2.16 193.725 246.24 193.995 ;
     RECT  2.16 194.265 246.24 194.535 ;
     RECT  2.16 194.805 246.24 195.075 ;
     RECT  2.16 195.345 246.24 195.615 ;
     RECT  2.16 195.885 246.24 196.155 ;
     RECT  2.16 196.425 246.24 196.695 ;
     RECT  2.16 196.965 246.24 197.235 ;
     RECT  2.16 197.505 246.24 197.775 ;
     RECT  2.16 198.045 246.24 198.315 ;
     RECT  2.16 198.585 246.24 198.855 ;
     RECT  2.16 199.125 246.24 199.395 ;
     RECT  2.16 199.665 246.24 199.935 ;
     RECT  2.16 200.205 246.24 200.475 ;
     RECT  2.16 200.745 246.24 201.015 ;
     RECT  2.16 201.285 246.24 201.555 ;
     RECT  2.16 201.825 246.24 202.095 ;
     RECT  2.16 202.365 246.24 202.635 ;
     RECT  2.16 202.905 246.24 203.175 ;
     RECT  2.16 203.445 246.24 203.715 ;
     RECT  2.16 203.985 246.24 204.255 ;
     RECT  2.16 204.525 246.24 204.795 ;
     RECT  2.16 205.065 246.24 205.335 ;
     RECT  2.16 205.605 246.24 205.875 ;
     RECT  2.16 206.145 246.24 206.415 ;
     RECT  2.16 206.685 246.24 206.955 ;
     RECT  2.16 207.225 246.24 207.495 ;
     RECT  2.16 207.765 246.24 208.035 ;
     RECT  2.16 208.305 246.24 208.575 ;
     RECT  2.16 208.845 246.24 209.115 ;
     RECT  2.16 209.385 246.24 209.655 ;
     RECT  2.16 209.925 246.24 210.195 ;
     RECT  2.16 210.465 246.24 210.735 ;
     RECT  2.16 211.005 246.24 211.275 ;
     RECT  2.16 211.545 246.24 211.815 ;
     RECT  2.16 212.085 246.24 212.355 ;
     RECT  2.16 212.625 246.24 212.895 ;
     RECT  2.16 213.165 246.24 213.435 ;
     RECT  2.16 213.705 246.24 213.975 ;
     RECT  2.16 214.245 246.24 214.515 ;
     RECT  2.16 214.785 246.24 215.055 ;
     RECT  2.16 215.325 246.24 215.595 ;
     RECT  2.16 215.865 246.24 216.135 ;
     RECT  2.16 216.405 246.24 216.675 ;
     RECT  2.16 216.945 246.24 217.215 ;
     RECT  2.16 217.485 246.24 217.755 ;
     RECT  2.16 218.025 246.24 218.295 ;
     RECT  2.16 218.565 246.24 218.835 ;
     RECT  2.16 219.105 246.24 219.375 ;
     RECT  2.16 219.645 246.24 219.915 ;
     RECT  2.16 220.185 246.24 220.455 ;
     RECT  2.16 220.725 246.24 220.995 ;
     RECT  2.16 221.265 246.24 221.535 ;
     RECT  2.16 221.805 246.24 222.075 ;
     RECT  2.16 222.345 246.24 222.615 ;
     RECT  2.16 222.885 246.24 223.155 ;
     RECT  2.16 223.425 246.24 223.695 ;
     RECT  2.16 223.965 246.24 224.235 ;
     RECT  2.16 224.505 246.24 224.775 ;
     RECT  2.16 225.045 246.24 225.315 ;
     RECT  2.16 225.585 246.24 225.855 ;
     RECT  2.16 226.125 246.24 226.395 ;
     RECT  2.16 226.665 246.24 226.935 ;
     RECT  2.16 227.205 246.24 227.475 ;
     RECT  2.16 227.745 246.24 228.015 ;
     RECT  2.16 228.285 246.24 228.555 ;
     RECT  2.16 228.825 246.24 229.095 ;
     RECT  2.16 229.365 246.24 229.635 ;
     RECT  2.16 229.905 246.24 230.175 ;
     RECT  2.16 230.445 246.24 230.715 ;
     RECT  2.16 230.985 246.24 231.255 ;
     RECT  2.16 231.525 246.24 231.795 ;
     RECT  2.16 232.065 246.24 232.335 ;
     RECT  2.16 232.605 246.24 232.875 ;
     RECT  2.16 233.145 246.24 233.415 ;
     RECT  2.16 233.685 246.24 233.955 ;
     RECT  2.16 234.225 246.24 234.495 ;
     RECT  2.16 234.765 246.24 235.035 ;
     RECT  2.16 235.305 246.24 235.575 ;
     RECT  2.16 235.845 246.24 236.115 ;
     RECT  2.16 236.385 246.24 236.655 ;
     RECT  2.16 236.925 246.24 237.195 ;
     RECT  2.16 237.465 246.24 237.735 ;
     RECT  2.16 238.005 246.24 238.275 ;
     RECT  2.16 238.545 246.24 238.815 ;
     RECT  2.16 239.085 246.24 239.355 ;
     RECT  2.16 239.625 246.24 239.895 ;
     RECT  2.16 240.165 246.24 240.435 ;
     RECT  2.16 240.705 246.24 240.975 ;
     RECT  2.16 241.245 246.24 241.515 ;
     RECT  2.16 241.785 246.24 242.055 ;
     RECT  2.16 242.325 246.24 242.595 ;
     RECT  2.16 242.865 246.24 243.135 ;
     RECT  2.16 243.405 246.24 243.675 ;
     RECT  2.16 243.945 246.24 244.215 ;
     RECT  2.16 244.485 246.24 244.755 ;
     RECT  2.16 245.025 246.24 245.295 ;
     RECT  2.16 245.565 246.24 245.835 ;
     RECT  2.16 246.105 246.24 246.375 ;
     RECT  2.16 246.645 246.24 246.915 ;
     RECT  2.16 247.185 246.24 247.455 ;
     RECT  2.16 247.725 246.24 247.995 ;
     RECT  2.16 248.265 246.24 248.535 ;
     RECT  2.16 248.805 246.24 249.075 ;
     RECT  2.16 249.345 246.24 249.615 ;
     RECT  2.16 249.885 246.24 250.155 ;
     RECT  2.16 250.425 246.24 250.695 ;
     RECT  2.16 250.965 246.24 251.235 ;
     RECT  2.16 251.505 246.24 251.775 ;
     RECT  2.16 252.045 246.24 252.315 ;
     RECT  2.16 252.585 246.24 252.855 ;
     RECT  2.16 253.125 246.24 253.395 ;
     RECT  2.16 253.665 246.24 253.935 ;
     RECT  2.16 254.205 246.24 254.475 ;
     RECT  2.16 254.745 246.24 255.015 ;
     RECT  2.16 255.285 246.24 255.555 ;
     RECT  2.16 255.825 246.24 256.095 ;
     RECT  2.16 256.365 246.24 256.635 ;
     RECT  2.16 256.905 246.24 257.175 ;
     RECT  2.16 257.445 246.24 257.715 ;
     RECT  2.16 257.985 246.24 258.255 ;
     RECT  2.16 258.525 246.24 258.795 ;
     RECT  2.16 259.065 246.24 259.335 ;
     RECT  2.16 259.605 246.24 259.875 ;
     RECT  2.16 260.145 246.24 260.415 ;
     RECT  2.16 260.685 246.24 260.955 ;
     RECT  2.16 261.225 246.24 261.495 ;
     RECT  2.16 261.765 246.24 262.035 ;
     RECT  2.16 262.305 246.24 262.575 ;
     RECT  2.16 262.845 246.24 263.115 ;
     RECT  2.16 263.385 246.24 263.655 ;
     RECT  2.16 263.925 246.24 264.195 ;
     RECT  2.16 264.465 246.24 264.735 ;
     RECT  2.16 265.005 246.24 265.275 ;
     RECT  2.16 265.545 246.24 265.815 ;
     RECT  2.16 266.085 246.24 266.355 ;
     RECT  2.16 266.625 246.24 266.895 ;
     RECT  2.16 267.165 246.24 267.435 ;
     RECT  2.16 267.705 246.24 267.975 ;
     RECT  2.16 268.245 246.24 268.515 ;
     RECT  2.16 268.785 246.24 269.055 ;
     RECT  2.16 269.325 246.24 269.595 ;
     RECT  2.16 269.865 246.24 270.135 ;
     RECT  2.16 270.405 246.24 270.675 ;
     RECT  2.16 270.945 246.24 271.215 ;
     RECT  2.16 271.485 246.24 271.755 ;
     RECT  2.16 272.025 246.24 272.295 ;
     RECT  2.16 272.565 246.24 272.835 ;
     RECT  2.16 273.105 246.24 273.375 ;
     RECT  2.16 273.645 246.24 273.915 ;
     RECT  2.16 274.185 246.24 274.455 ;
     RECT  2.16 274.725 246.24 274.995 ;
     RECT  2.16 275.265 246.24 275.535 ;
     RECT  2.16 275.805 246.24 276.075 ;
     RECT  2.16 276.345 246.24 276.615 ;
     RECT  2.16 276.885 246.24 277.155 ;
     RECT  2.16 277.425 246.24 277.695 ;
     RECT  2.16 277.965 246.24 278.235 ;
     RECT  2.16 278.505 246.24 278.775 ;
     RECT  2.16 279.045 246.24 279.315 ;
     RECT  2.16 279.585 246.24 279.855 ;
     RECT  2.16 280.125 246.24 280.395 ;
     RECT  2.16 280.665 246.24 280.935 ;
     RECT  2.16 281.205 246.24 281.475 ;
     RECT  2.16 281.745 246.24 282.015 ;
     RECT  2.16 282.285 246.24 282.555 ;
     RECT  2.16 282.825 246.24 283.095 ;
     RECT  2.16 283.365 246.24 283.635 ;
     RECT  2.16 283.905 246.24 284.175 ;
     RECT  2.16 284.445 246.24 284.715 ;
     RECT  2.16 284.985 246.24 285.255 ;
     RECT  2.16 285.525 246.24 285.795 ;
     RECT  2.16 286.065 246.24 286.335 ;
     RECT  2.16 286.605 246.24 286.875 ;
     RECT  2.16 287.145 246.24 287.415 ;
     RECT  2.16 287.685 246.24 287.955 ;
     RECT  2.16 288.225 246.24 288.495 ;
     RECT  2.16 288.765 246.24 289.035 ;
     RECT  2.16 289.305 246.24 289.575 ;
     RECT  2.16 289.845 246.24 290.115 ;
     RECT  2.16 290.385 246.24 290.655 ;
     RECT  2.16 290.925 246.24 291.195 ;
     RECT  2.16 291.465 246.24 291.735 ;
     RECT  2.16 292.005 246.24 292.275 ;
     RECT  2.16 292.545 246.24 292.815 ;
     RECT  2.16 293.085 246.24 293.355 ;
     RECT  2.16 293.625 246.24 293.895 ;
     RECT  2.16 294.165 246.24 294.435 ;
     RECT  2.16 294.705 246.24 294.975 ;
     RECT  2.16 295.245 246.24 295.515 ;
     RECT  2.16 295.785 246.24 296.055 ;
     RECT  2.16 296.325 246.24 296.595 ;
     RECT  2.16 296.865 246.24 297.135 ;
     RECT  2.16 297.405 246.24 297.675 ;
     RECT  2.16 297.945 246.24 298.215 ;
     RECT  2.16 298.485 246.24 298.755 ;
     RECT  2.16 299.025 246.24 299.295 ;
     RECT  2.16 299.565 246.24 299.835 ;
     RECT  2.16 300.105 246.24 300.375 ;
     RECT  2.16 300.645 246.24 300.915 ;
     RECT  2.16 301.185 246.24 301.455 ;
     RECT  2.16 301.725 246.24 301.995 ;
     RECT  2.16 302.265 246.24 302.535 ;
     RECT  2.16 302.805 246.24 303.075 ;
     RECT  2.16 303.345 246.24 303.615 ;
     RECT  2.16 303.885 246.24 304.155 ;
     RECT  2.16 304.425 246.24 304.695 ;
     RECT  2.16 304.965 246.24 305.235 ;
     RECT  2.16 305.505 246.24 305.775 ;
     RECT  2.16 306.045 246.24 306.315 ;
     RECT  2.16 306.585 246.24 306.855 ;
     RECT  2.16 307.125 246.24 307.395 ;
     RECT  2.16 307.665 246.24 307.935 ;
     RECT  2.16 308.205 246.24 308.475 ;
     RECT  2.16 308.745 246.24 309.015 ;
     RECT  2.16 309.285 246.24 309.555 ;
     RECT  2.16 309.825 246.24 310.095 ;
     RECT  2.16 310.365 246.24 310.635 ;
     RECT  2.16 310.905 246.24 311.175 ;
     RECT  2.16 311.445 246.24 311.715 ;
     RECT  2.16 311.985 246.24 312.255 ;
     RECT  2.16 312.525 246.24 312.795 ;
     RECT  2.16 313.065 246.24 313.335 ;
     RECT  2.16 313.605 246.24 313.875 ;
     RECT  2.16 314.145 246.24 314.415 ;
     RECT  2.16 314.685 246.24 314.955 ;
     RECT  2.16 315.225 246.24 315.495 ;
     RECT  2.16 315.765 246.24 316.035 ;
     RECT  2.16 316.305 246.24 316.575 ;
     RECT  2.16 316.845 246.24 317.115 ;
     RECT  2.16 317.385 246.24 317.655 ;
     RECT  2.16 317.925 246.24 318.195 ;
     RECT  2.16 318.465 246.24 318.735 ;
     RECT  2.16 319.005 246.24 319.275 ;
     RECT  2.16 319.545 246.24 319.815 ;
     RECT  2.16 320.085 246.24 320.355 ;
     RECT  2.16 320.625 246.24 320.895 ;
     RECT  2.16 321.165 246.24 321.435 ;
     RECT  2.16 321.705 246.24 321.975 ;
     RECT  2.16 322.245 246.24 322.515 ;
     RECT  2.16 322.785 246.24 323.055 ;
     RECT  2.16 323.325 246.24 323.595 ;
     RECT  2.16 323.865 246.24 324.135 ;
     RECT  2.16 324.405 246.24 324.675 ;
     RECT  2.16 324.945 246.24 325.215 ;
     RECT  2.16 325.485 246.24 325.755 ;
     RECT  2.16 326.025 246.24 326.295 ;
     RECT  2.16 326.565 246.24 326.835 ;
     RECT  2.16 327.105 246.24 327.375 ;
     RECT  2.16 327.645 246.24 327.915 ;
     RECT  2.16 328.185 246.24 328.455 ;
     RECT  2.16 328.725 246.24 328.995 ;
     RECT  2.16 329.265 246.24 329.535 ;
     RECT  2.16 329.805 246.24 330.075 ;
     RECT  2.16 330.345 246.24 330.615 ;
     RECT  2.16 330.885 246.24 331.155 ;
     RECT  2.16 331.425 246.24 331.695 ;
     RECT  2.16 331.965 246.24 332.235 ;
     RECT  2.16 332.505 246.24 332.775 ;
     RECT  2.16 333.045 246.24 333.315 ;
     RECT  2.16 333.585 246.24 333.855 ;
     RECT  2.16 334.125 246.24 334.395 ;
     RECT  2.16 334.665 246.24 334.935 ;
     RECT  2.16 335.205 246.24 335.475 ;
     RECT  2.16 335.745 246.24 336.015 ;
     RECT  2.16 336.285 246.24 336.555 ;
     RECT  2.16 336.825 246.24 337.095 ;
     RECT  2.16 337.365 246.24 337.635 ;
     RECT  2.16 337.905 246.24 338.175 ;
     RECT  2.16 338.445 246.24 338.715 ;
     RECT  2.16 338.985 246.24 339.255 ;
     RECT  2.16 339.525 246.24 339.795 ;
     RECT  2.16 340.065 246.24 340.335 ;
     RECT  2.16 340.605 246.24 340.875 ;
     RECT  2.16 341.145 246.24 341.415 ;
     RECT  2.16 341.685 246.24 341.955 ;
     RECT  2.16 342.225 246.24 342.495 ;
     RECT  2.16 342.765 246.24 343.035 ;
     RECT  2.16 343.305 246.24 343.575 ;
     RECT  2.16 343.845 246.24 344.115 ;
     RECT  2.16 344.385 246.24 344.655 ;
     RECT  2.16 344.925 246.24 345.195 ;
     RECT  2.16 345.465 246.24 345.735 ;
     RECT  2.16 346.005 246.24 346.275 ;
     RECT  2.16 346.545 246.24 346.815 ;
     RECT  2.16 347.085 246.24 347.355 ;
     RECT  2.16 347.625 246.24 347.895 ;
     RECT  2.16 348.165 246.24 348.435 ;
     RECT  2.16 348.705 246.24 348.975 ;
     RECT  2.16 349.245 246.24 349.515 ;
     RECT  2.16 349.785 246.24 350.055 ;
     RECT  2.16 350.325 246.24 350.595 ;
     RECT  2.16 350.865 246.24 351.135 ;
     RECT  2.16 351.405 246.24 351.675 ;
     RECT  2.16 351.945 246.24 352.215 ;
     RECT  2.16 352.485 246.24 352.755 ;
     RECT  2.16 353.025 246.24 353.295 ;
     RECT  2.16 353.565 246.24 353.835 ;
     RECT  2.16 354.105 246.24 354.375 ;
     RECT  2.16 354.645 246.24 354.915 ;
     RECT  2.16 355.185 246.24 355.455 ;
     RECT  2.16 355.725 246.24 355.995 ;
     RECT  2.16 356.265 246.24 356.535 ;
     RECT  2.16 356.805 246.24 357.075 ;
     RECT  2.16 357.345 246.24 357.615 ;
     RECT  2.16 357.885 246.24 358.155 ;
     RECT  2.16 358.425 246.24 358.695 ;
     RECT  2.16 358.965 246.24 359.235 ;
     RECT  2.16 359.505 246.24 359.775 ;
     RECT  2.16 360.045 246.24 360.315 ;
     RECT  2.16 360.585 246.24 360.855 ;
     RECT  2.16 361.125 246.24 361.395 ;
     RECT  2.16 361.665 246.24 361.935 ;
     RECT  2.16 362.205 246.24 362.475 ;
     RECT  2.16 362.745 246.24 363.015 ;
     RECT  2.16 363.285 246.24 363.555 ;
     RECT  2.16 363.825 246.24 364.095 ;
     RECT  2.16 364.365 246.24 364.635 ;
     RECT  2.16 364.905 246.24 365.175 ;
     RECT  2.16 365.445 246.24 365.715 ;
     RECT  2.16 365.985 246.24 366.255 ;
     RECT  2.16 366.525 246.24 366.795 ;
     RECT  2.16 367.065 246.24 367.335 ;
     RECT  2.16 367.605 246.24 367.875 ;
     RECT  2.16 368.145 246.24 368.415 ;
     RECT  2.16 368.685 246.24 368.955 ;
     RECT  2.16 369.225 246.24 369.36 ;
    LAYER RVTP ;
     RECT  2.16 2.295 246.24 2.565 ;
     RECT  2.16 2.835 246.24 3.105 ;
     RECT  2.16 3.375 246.24 3.645 ;
     RECT  2.16 3.915 246.24 4.185 ;
     RECT  2.16 4.455 246.24 4.725 ;
     RECT  2.16 4.995 246.24 5.265 ;
     RECT  2.16 5.535 246.24 5.805 ;
     RECT  2.16 6.075 246.24 6.345 ;
     RECT  2.16 6.615 246.24 6.885 ;
     RECT  2.16 7.155 246.24 7.425 ;
     RECT  2.16 7.695 246.24 7.965 ;
     RECT  2.16 8.235 246.24 8.505 ;
     RECT  2.16 8.775 246.24 9.045 ;
     RECT  2.16 9.315 246.24 9.585 ;
     RECT  2.16 9.855 246.24 10.125 ;
     RECT  2.16 10.395 246.24 10.665 ;
     RECT  2.16 10.935 246.24 11.205 ;
     RECT  2.16 11.475 246.24 11.745 ;
     RECT  2.16 12.015 246.24 12.285 ;
     RECT  2.16 12.555 246.24 12.825 ;
     RECT  2.16 13.095 246.24 13.365 ;
     RECT  2.16 13.635 246.24 13.905 ;
     RECT  2.16 14.175 246.24 14.445 ;
     RECT  2.16 14.715 246.24 14.985 ;
     RECT  2.16 15.255 246.24 15.525 ;
     RECT  2.16 15.795 246.24 16.065 ;
     RECT  2.16 16.335 246.24 16.605 ;
     RECT  2.16 16.875 246.24 17.145 ;
     RECT  2.16 17.415 246.24 17.685 ;
     RECT  2.16 17.955 246.24 18.225 ;
     RECT  2.16 18.495 246.24 18.765 ;
     RECT  2.16 19.035 246.24 19.305 ;
     RECT  2.16 19.575 246.24 19.845 ;
     RECT  2.16 20.115 246.24 20.385 ;
     RECT  2.16 20.655 246.24 20.925 ;
     RECT  2.16 21.195 246.24 21.465 ;
     RECT  2.16 21.735 246.24 22.005 ;
     RECT  2.16 22.275 246.24 22.545 ;
     RECT  2.16 22.815 246.24 23.085 ;
     RECT  2.16 23.355 246.24 23.625 ;
     RECT  2.16 23.895 246.24 24.165 ;
     RECT  2.16 24.435 246.24 24.705 ;
     RECT  2.16 24.975 246.24 25.245 ;
     RECT  2.16 25.515 246.24 25.785 ;
     RECT  2.16 26.055 246.24 26.325 ;
     RECT  2.16 26.595 246.24 26.865 ;
     RECT  2.16 27.135 246.24 27.405 ;
     RECT  2.16 27.675 246.24 27.945 ;
     RECT  2.16 28.215 246.24 28.485 ;
     RECT  2.16 28.755 246.24 29.025 ;
     RECT  2.16 29.295 246.24 29.565 ;
     RECT  2.16 29.835 246.24 30.105 ;
     RECT  2.16 30.375 246.24 30.645 ;
     RECT  2.16 30.915 246.24 31.185 ;
     RECT  2.16 31.455 246.24 31.725 ;
     RECT  2.16 31.995 246.24 32.265 ;
     RECT  2.16 32.535 246.24 32.805 ;
     RECT  2.16 33.075 246.24 33.345 ;
     RECT  2.16 33.615 246.24 33.885 ;
     RECT  2.16 34.155 246.24 34.425 ;
     RECT  2.16 34.695 246.24 34.965 ;
     RECT  2.16 35.235 246.24 35.505 ;
     RECT  2.16 35.775 246.24 36.045 ;
     RECT  2.16 36.315 246.24 36.585 ;
     RECT  2.16 36.855 246.24 37.125 ;
     RECT  2.16 37.395 246.24 37.665 ;
     RECT  2.16 37.935 246.24 38.205 ;
     RECT  2.16 38.475 246.24 38.745 ;
     RECT  2.16 39.015 246.24 39.285 ;
     RECT  2.16 39.555 246.24 39.825 ;
     RECT  2.16 40.095 246.24 40.365 ;
     RECT  2.16 40.635 246.24 40.905 ;
     RECT  2.16 41.175 246.24 41.445 ;
     RECT  2.16 41.715 246.24 41.985 ;
     RECT  2.16 42.255 246.24 42.525 ;
     RECT  2.16 42.795 246.24 43.065 ;
     RECT  2.16 43.335 246.24 43.605 ;
     RECT  2.16 43.875 246.24 44.145 ;
     RECT  2.16 44.415 246.24 44.685 ;
     RECT  2.16 44.955 246.24 45.225 ;
     RECT  2.16 45.495 246.24 45.765 ;
     RECT  2.16 46.035 246.24 46.305 ;
     RECT  2.16 46.575 246.24 46.845 ;
     RECT  2.16 47.115 246.24 47.385 ;
     RECT  2.16 47.655 246.24 47.925 ;
     RECT  2.16 48.195 246.24 48.465 ;
     RECT  2.16 48.735 246.24 49.005 ;
     RECT  2.16 49.275 246.24 49.545 ;
     RECT  2.16 49.815 246.24 50.085 ;
     RECT  2.16 50.355 246.24 50.625 ;
     RECT  2.16 50.895 246.24 51.165 ;
     RECT  2.16 51.435 246.24 51.705 ;
     RECT  2.16 51.975 246.24 52.245 ;
     RECT  2.16 52.515 246.24 52.785 ;
     RECT  2.16 53.055 246.24 53.325 ;
     RECT  2.16 53.595 246.24 53.865 ;
     RECT  2.16 54.135 246.24 54.405 ;
     RECT  2.16 54.675 246.24 54.945 ;
     RECT  2.16 55.215 246.24 55.485 ;
     RECT  2.16 55.755 246.24 56.025 ;
     RECT  2.16 56.295 246.24 56.565 ;
     RECT  2.16 56.835 246.24 57.105 ;
     RECT  2.16 57.375 246.24 57.645 ;
     RECT  2.16 57.915 246.24 58.185 ;
     RECT  2.16 58.455 246.24 58.725 ;
     RECT  2.16 58.995 246.24 59.265 ;
     RECT  2.16 59.535 246.24 59.805 ;
     RECT  2.16 60.075 246.24 60.345 ;
     RECT  2.16 60.615 246.24 60.885 ;
     RECT  2.16 61.155 246.24 61.425 ;
     RECT  2.16 61.695 246.24 61.965 ;
     RECT  2.16 62.235 246.24 62.505 ;
     RECT  2.16 62.775 246.24 63.045 ;
     RECT  2.16 63.315 246.24 63.585 ;
     RECT  2.16 63.855 246.24 64.125 ;
     RECT  2.16 64.395 246.24 64.665 ;
     RECT  2.16 64.935 246.24 65.205 ;
     RECT  2.16 65.475 246.24 65.745 ;
     RECT  2.16 66.015 246.24 66.285 ;
     RECT  2.16 66.555 246.24 66.825 ;
     RECT  2.16 67.095 246.24 67.365 ;
     RECT  2.16 67.635 246.24 67.905 ;
     RECT  2.16 68.175 246.24 68.445 ;
     RECT  2.16 68.715 246.24 68.985 ;
     RECT  2.16 69.255 246.24 69.525 ;
     RECT  2.16 69.795 246.24 70.065 ;
     RECT  2.16 70.335 246.24 70.605 ;
     RECT  2.16 70.875 246.24 71.145 ;
     RECT  2.16 71.415 246.24 71.685 ;
     RECT  2.16 71.955 246.24 72.225 ;
     RECT  2.16 72.495 246.24 72.765 ;
     RECT  2.16 73.035 246.24 73.305 ;
     RECT  2.16 73.575 246.24 73.845 ;
     RECT  2.16 74.115 246.24 74.385 ;
     RECT  2.16 74.655 246.24 74.925 ;
     RECT  2.16 75.195 246.24 75.465 ;
     RECT  2.16 75.735 246.24 76.005 ;
     RECT  2.16 76.275 246.24 76.545 ;
     RECT  2.16 76.815 246.24 77.085 ;
     RECT  2.16 77.355 246.24 77.625 ;
     RECT  2.16 77.895 246.24 78.165 ;
     RECT  2.16 78.435 246.24 78.705 ;
     RECT  2.16 78.975 246.24 79.245 ;
     RECT  2.16 79.515 246.24 79.785 ;
     RECT  2.16 80.055 246.24 80.325 ;
     RECT  2.16 80.595 246.24 80.865 ;
     RECT  2.16 81.135 246.24 81.405 ;
     RECT  2.16 81.675 246.24 81.945 ;
     RECT  2.16 82.215 246.24 82.485 ;
     RECT  2.16 82.755 246.24 83.025 ;
     RECT  2.16 83.295 246.24 83.565 ;
     RECT  2.16 83.835 246.24 84.105 ;
     RECT  2.16 84.375 246.24 84.645 ;
     RECT  2.16 84.915 246.24 85.185 ;
     RECT  2.16 85.455 246.24 85.725 ;
     RECT  2.16 85.995 246.24 86.265 ;
     RECT  2.16 86.535 246.24 86.805 ;
     RECT  2.16 87.075 246.24 87.345 ;
     RECT  2.16 87.615 246.24 87.885 ;
     RECT  2.16 88.155 246.24 88.425 ;
     RECT  2.16 88.695 246.24 88.965 ;
     RECT  2.16 89.235 246.24 89.505 ;
     RECT  2.16 89.775 246.24 90.045 ;
     RECT  2.16 90.315 246.24 90.585 ;
     RECT  2.16 90.855 246.24 91.125 ;
     RECT  2.16 91.395 246.24 91.665 ;
     RECT  2.16 91.935 246.24 92.205 ;
     RECT  2.16 92.475 246.24 92.745 ;
     RECT  2.16 93.015 246.24 93.285 ;
     RECT  2.16 93.555 246.24 93.825 ;
     RECT  2.16 94.095 246.24 94.365 ;
     RECT  2.16 94.635 246.24 94.905 ;
     RECT  2.16 95.175 246.24 95.445 ;
     RECT  2.16 95.715 246.24 95.985 ;
     RECT  2.16 96.255 246.24 96.525 ;
     RECT  2.16 96.795 246.24 97.065 ;
     RECT  2.16 97.335 246.24 97.605 ;
     RECT  2.16 97.875 246.24 98.145 ;
     RECT  2.16 98.415 246.24 98.685 ;
     RECT  2.16 98.955 246.24 99.225 ;
     RECT  2.16 99.495 246.24 99.765 ;
     RECT  2.16 100.035 246.24 100.305 ;
     RECT  2.16 100.575 246.24 100.845 ;
     RECT  2.16 101.115 246.24 101.385 ;
     RECT  2.16 101.655 246.24 101.925 ;
     RECT  2.16 102.195 246.24 102.465 ;
     RECT  2.16 102.735 246.24 103.005 ;
     RECT  2.16 103.275 246.24 103.545 ;
     RECT  2.16 103.815 246.24 104.085 ;
     RECT  2.16 104.355 246.24 104.625 ;
     RECT  2.16 104.895 246.24 105.165 ;
     RECT  2.16 105.435 246.24 105.705 ;
     RECT  2.16 105.975 246.24 106.245 ;
     RECT  2.16 106.515 246.24 106.785 ;
     RECT  2.16 107.055 246.24 107.325 ;
     RECT  2.16 107.595 246.24 107.865 ;
     RECT  2.16 108.135 246.24 108.405 ;
     RECT  2.16 108.675 246.24 108.945 ;
     RECT  2.16 109.215 246.24 109.485 ;
     RECT  2.16 109.755 246.24 110.025 ;
     RECT  2.16 110.295 246.24 110.565 ;
     RECT  2.16 110.835 246.24 111.105 ;
     RECT  2.16 111.375 246.24 111.645 ;
     RECT  2.16 111.915 246.24 112.185 ;
     RECT  2.16 112.455 246.24 112.725 ;
     RECT  2.16 112.995 246.24 113.265 ;
     RECT  2.16 113.535 246.24 113.805 ;
     RECT  2.16 114.075 246.24 114.345 ;
     RECT  2.16 114.615 246.24 114.885 ;
     RECT  2.16 115.155 246.24 115.425 ;
     RECT  2.16 115.695 246.24 115.965 ;
     RECT  2.16 116.235 246.24 116.505 ;
     RECT  2.16 116.775 246.24 117.045 ;
     RECT  2.16 117.315 246.24 117.585 ;
     RECT  2.16 117.855 246.24 118.125 ;
     RECT  2.16 118.395 246.24 118.665 ;
     RECT  2.16 118.935 246.24 119.205 ;
     RECT  2.16 119.475 246.24 119.745 ;
     RECT  2.16 120.015 246.24 120.285 ;
     RECT  2.16 120.555 246.24 120.825 ;
     RECT  2.16 121.095 246.24 121.365 ;
     RECT  2.16 121.635 246.24 121.905 ;
     RECT  2.16 122.175 246.24 122.445 ;
     RECT  2.16 122.715 246.24 122.985 ;
     RECT  2.16 123.255 246.24 123.525 ;
     RECT  2.16 123.795 246.24 124.065 ;
     RECT  2.16 124.335 246.24 124.605 ;
     RECT  2.16 124.875 246.24 125.145 ;
     RECT  2.16 125.415 246.24 125.685 ;
     RECT  2.16 125.955 246.24 126.225 ;
     RECT  2.16 126.495 246.24 126.765 ;
     RECT  2.16 127.035 246.24 127.305 ;
     RECT  2.16 127.575 246.24 127.845 ;
     RECT  2.16 128.115 246.24 128.385 ;
     RECT  2.16 128.655 246.24 128.925 ;
     RECT  2.16 129.195 246.24 129.465 ;
     RECT  2.16 129.735 246.24 130.005 ;
     RECT  2.16 130.275 246.24 130.545 ;
     RECT  2.16 130.815 246.24 131.085 ;
     RECT  2.16 131.355 246.24 131.625 ;
     RECT  2.16 131.895 246.24 132.165 ;
     RECT  2.16 132.435 246.24 132.705 ;
     RECT  2.16 132.975 246.24 133.245 ;
     RECT  2.16 133.515 246.24 133.785 ;
     RECT  2.16 134.055 246.24 134.325 ;
     RECT  2.16 134.595 246.24 134.865 ;
     RECT  2.16 135.135 246.24 135.405 ;
     RECT  2.16 135.675 246.24 135.945 ;
     RECT  2.16 136.215 246.24 136.485 ;
     RECT  2.16 136.755 246.24 137.025 ;
     RECT  2.16 137.295 246.24 137.565 ;
     RECT  2.16 137.835 246.24 138.105 ;
     RECT  2.16 138.375 246.24 138.645 ;
     RECT  2.16 138.915 246.24 139.185 ;
     RECT  2.16 139.455 246.24 139.725 ;
     RECT  2.16 139.995 246.24 140.265 ;
     RECT  2.16 140.535 246.24 140.805 ;
     RECT  2.16 141.075 246.24 141.345 ;
     RECT  2.16 141.615 246.24 141.885 ;
     RECT  2.16 142.155 246.24 142.425 ;
     RECT  2.16 142.695 246.24 142.965 ;
     RECT  2.16 143.235 246.24 143.505 ;
     RECT  2.16 143.775 246.24 144.045 ;
     RECT  2.16 144.315 246.24 144.585 ;
     RECT  2.16 144.855 246.24 145.125 ;
     RECT  2.16 145.395 246.24 145.665 ;
     RECT  2.16 145.935 246.24 146.205 ;
     RECT  2.16 146.475 246.24 146.745 ;
     RECT  2.16 147.015 246.24 147.285 ;
     RECT  2.16 147.555 246.24 147.825 ;
     RECT  2.16 148.095 246.24 148.365 ;
     RECT  2.16 148.635 246.24 148.905 ;
     RECT  2.16 149.175 246.24 149.445 ;
     RECT  2.16 149.715 246.24 149.985 ;
     RECT  2.16 150.255 246.24 150.525 ;
     RECT  2.16 150.795 246.24 151.065 ;
     RECT  2.16 151.335 246.24 151.605 ;
     RECT  2.16 151.875 246.24 152.145 ;
     RECT  2.16 152.415 246.24 152.685 ;
     RECT  2.16 152.955 246.24 153.225 ;
     RECT  2.16 153.495 246.24 153.765 ;
     RECT  2.16 154.035 246.24 154.305 ;
     RECT  2.16 154.575 246.24 154.845 ;
     RECT  2.16 155.115 246.24 155.385 ;
     RECT  2.16 155.655 246.24 155.925 ;
     RECT  2.16 156.195 246.24 156.465 ;
     RECT  2.16 156.735 246.24 157.005 ;
     RECT  2.16 157.275 246.24 157.545 ;
     RECT  2.16 157.815 246.24 158.085 ;
     RECT  2.16 158.355 246.24 158.625 ;
     RECT  2.16 158.895 246.24 159.165 ;
     RECT  2.16 159.435 246.24 159.705 ;
     RECT  2.16 159.975 246.24 160.245 ;
     RECT  2.16 160.515 246.24 160.785 ;
     RECT  2.16 161.055 246.24 161.325 ;
     RECT  2.16 161.595 246.24 161.865 ;
     RECT  2.16 162.135 246.24 162.405 ;
     RECT  2.16 162.675 246.24 162.945 ;
     RECT  2.16 163.215 246.24 163.485 ;
     RECT  2.16 163.755 246.24 164.025 ;
     RECT  2.16 164.295 246.24 164.565 ;
     RECT  2.16 164.835 246.24 165.105 ;
     RECT  2.16 165.375 246.24 165.645 ;
     RECT  2.16 165.915 246.24 166.185 ;
     RECT  2.16 166.455 246.24 166.725 ;
     RECT  2.16 166.995 246.24 167.265 ;
     RECT  2.16 167.535 246.24 167.805 ;
     RECT  2.16 168.075 246.24 168.345 ;
     RECT  2.16 168.615 246.24 168.885 ;
     RECT  2.16 169.155 246.24 169.425 ;
     RECT  2.16 169.695 246.24 169.965 ;
     RECT  2.16 170.235 246.24 170.505 ;
     RECT  2.16 170.775 246.24 171.045 ;
     RECT  2.16 171.315 246.24 171.585 ;
     RECT  2.16 171.855 246.24 172.125 ;
     RECT  2.16 172.395 246.24 172.665 ;
     RECT  2.16 172.935 246.24 173.205 ;
     RECT  2.16 173.475 246.24 173.745 ;
     RECT  2.16 174.015 246.24 174.285 ;
     RECT  2.16 174.555 246.24 174.825 ;
     RECT  2.16 175.095 246.24 175.365 ;
     RECT  2.16 175.635 246.24 175.905 ;
     RECT  2.16 176.175 246.24 176.445 ;
     RECT  2.16 176.715 246.24 176.985 ;
     RECT  2.16 177.255 246.24 177.525 ;
     RECT  2.16 177.795 246.24 178.065 ;
     RECT  2.16 178.335 246.24 178.605 ;
     RECT  2.16 178.875 246.24 179.145 ;
     RECT  2.16 179.415 246.24 179.685 ;
     RECT  2.16 179.955 246.24 180.225 ;
     RECT  2.16 180.495 246.24 180.765 ;
     RECT  2.16 181.035 246.24 181.305 ;
     RECT  2.16 181.575 246.24 181.845 ;
     RECT  2.16 182.115 246.24 182.385 ;
     RECT  2.16 182.655 246.24 182.925 ;
     RECT  2.16 183.195 246.24 183.465 ;
     RECT  2.16 183.735 246.24 184.005 ;
     RECT  2.16 184.275 246.24 184.545 ;
     RECT  2.16 184.815 246.24 185.085 ;
     RECT  2.16 185.355 246.24 185.625 ;
     RECT  2.16 185.895 246.24 186.165 ;
     RECT  2.16 186.435 246.24 186.705 ;
     RECT  2.16 186.975 246.24 187.245 ;
     RECT  2.16 187.515 246.24 187.785 ;
     RECT  2.16 188.055 246.24 188.325 ;
     RECT  2.16 188.595 246.24 188.865 ;
     RECT  2.16 189.135 246.24 189.405 ;
     RECT  2.16 189.675 246.24 189.945 ;
     RECT  2.16 190.215 246.24 190.485 ;
     RECT  2.16 190.755 246.24 191.025 ;
     RECT  2.16 191.295 246.24 191.565 ;
     RECT  2.16 191.835 246.24 192.105 ;
     RECT  2.16 192.375 246.24 192.645 ;
     RECT  2.16 192.915 246.24 193.185 ;
     RECT  2.16 193.455 246.24 193.725 ;
     RECT  2.16 193.995 246.24 194.265 ;
     RECT  2.16 194.535 246.24 194.805 ;
     RECT  2.16 195.075 246.24 195.345 ;
     RECT  2.16 195.615 246.24 195.885 ;
     RECT  2.16 196.155 246.24 196.425 ;
     RECT  2.16 196.695 246.24 196.965 ;
     RECT  2.16 197.235 246.24 197.505 ;
     RECT  2.16 197.775 246.24 198.045 ;
     RECT  2.16 198.315 246.24 198.585 ;
     RECT  2.16 198.855 246.24 199.125 ;
     RECT  2.16 199.395 246.24 199.665 ;
     RECT  2.16 199.935 246.24 200.205 ;
     RECT  2.16 200.475 246.24 200.745 ;
     RECT  2.16 201.015 246.24 201.285 ;
     RECT  2.16 201.555 246.24 201.825 ;
     RECT  2.16 202.095 246.24 202.365 ;
     RECT  2.16 202.635 246.24 202.905 ;
     RECT  2.16 203.175 246.24 203.445 ;
     RECT  2.16 203.715 246.24 203.985 ;
     RECT  2.16 204.255 246.24 204.525 ;
     RECT  2.16 204.795 246.24 205.065 ;
     RECT  2.16 205.335 246.24 205.605 ;
     RECT  2.16 205.875 246.24 206.145 ;
     RECT  2.16 206.415 246.24 206.685 ;
     RECT  2.16 206.955 246.24 207.225 ;
     RECT  2.16 207.495 246.24 207.765 ;
     RECT  2.16 208.035 246.24 208.305 ;
     RECT  2.16 208.575 246.24 208.845 ;
     RECT  2.16 209.115 246.24 209.385 ;
     RECT  2.16 209.655 246.24 209.925 ;
     RECT  2.16 210.195 246.24 210.465 ;
     RECT  2.16 210.735 246.24 211.005 ;
     RECT  2.16 211.275 246.24 211.545 ;
     RECT  2.16 211.815 246.24 212.085 ;
     RECT  2.16 212.355 246.24 212.625 ;
     RECT  2.16 212.895 246.24 213.165 ;
     RECT  2.16 213.435 246.24 213.705 ;
     RECT  2.16 213.975 246.24 214.245 ;
     RECT  2.16 214.515 246.24 214.785 ;
     RECT  2.16 215.055 246.24 215.325 ;
     RECT  2.16 215.595 246.24 215.865 ;
     RECT  2.16 216.135 246.24 216.405 ;
     RECT  2.16 216.675 246.24 216.945 ;
     RECT  2.16 217.215 246.24 217.485 ;
     RECT  2.16 217.755 246.24 218.025 ;
     RECT  2.16 218.295 246.24 218.565 ;
     RECT  2.16 218.835 246.24 219.105 ;
     RECT  2.16 219.375 246.24 219.645 ;
     RECT  2.16 219.915 246.24 220.185 ;
     RECT  2.16 220.455 246.24 220.725 ;
     RECT  2.16 220.995 246.24 221.265 ;
     RECT  2.16 221.535 246.24 221.805 ;
     RECT  2.16 222.075 246.24 222.345 ;
     RECT  2.16 222.615 246.24 222.885 ;
     RECT  2.16 223.155 246.24 223.425 ;
     RECT  2.16 223.695 246.24 223.965 ;
     RECT  2.16 224.235 246.24 224.505 ;
     RECT  2.16 224.775 246.24 225.045 ;
     RECT  2.16 225.315 246.24 225.585 ;
     RECT  2.16 225.855 246.24 226.125 ;
     RECT  2.16 226.395 246.24 226.665 ;
     RECT  2.16 226.935 246.24 227.205 ;
     RECT  2.16 227.475 246.24 227.745 ;
     RECT  2.16 228.015 246.24 228.285 ;
     RECT  2.16 228.555 246.24 228.825 ;
     RECT  2.16 229.095 246.24 229.365 ;
     RECT  2.16 229.635 246.24 229.905 ;
     RECT  2.16 230.175 246.24 230.445 ;
     RECT  2.16 230.715 246.24 230.985 ;
     RECT  2.16 231.255 246.24 231.525 ;
     RECT  2.16 231.795 246.24 232.065 ;
     RECT  2.16 232.335 246.24 232.605 ;
     RECT  2.16 232.875 246.24 233.145 ;
     RECT  2.16 233.415 246.24 233.685 ;
     RECT  2.16 233.955 246.24 234.225 ;
     RECT  2.16 234.495 246.24 234.765 ;
     RECT  2.16 235.035 246.24 235.305 ;
     RECT  2.16 235.575 246.24 235.845 ;
     RECT  2.16 236.115 246.24 236.385 ;
     RECT  2.16 236.655 246.24 236.925 ;
     RECT  2.16 237.195 246.24 237.465 ;
     RECT  2.16 237.735 246.24 238.005 ;
     RECT  2.16 238.275 246.24 238.545 ;
     RECT  2.16 238.815 246.24 239.085 ;
     RECT  2.16 239.355 246.24 239.625 ;
     RECT  2.16 239.895 246.24 240.165 ;
     RECT  2.16 240.435 246.24 240.705 ;
     RECT  2.16 240.975 246.24 241.245 ;
     RECT  2.16 241.515 246.24 241.785 ;
     RECT  2.16 242.055 246.24 242.325 ;
     RECT  2.16 242.595 246.24 242.865 ;
     RECT  2.16 243.135 246.24 243.405 ;
     RECT  2.16 243.675 246.24 243.945 ;
     RECT  2.16 244.215 246.24 244.485 ;
     RECT  2.16 244.755 246.24 245.025 ;
     RECT  2.16 245.295 246.24 245.565 ;
     RECT  2.16 245.835 246.24 246.105 ;
     RECT  2.16 246.375 246.24 246.645 ;
     RECT  2.16 246.915 246.24 247.185 ;
     RECT  2.16 247.455 246.24 247.725 ;
     RECT  2.16 247.995 246.24 248.265 ;
     RECT  2.16 248.535 246.24 248.805 ;
     RECT  2.16 249.075 246.24 249.345 ;
     RECT  2.16 249.615 246.24 249.885 ;
     RECT  2.16 250.155 246.24 250.425 ;
     RECT  2.16 250.695 246.24 250.965 ;
     RECT  2.16 251.235 246.24 251.505 ;
     RECT  2.16 251.775 246.24 252.045 ;
     RECT  2.16 252.315 246.24 252.585 ;
     RECT  2.16 252.855 246.24 253.125 ;
     RECT  2.16 253.395 246.24 253.665 ;
     RECT  2.16 253.935 246.24 254.205 ;
     RECT  2.16 254.475 246.24 254.745 ;
     RECT  2.16 255.015 246.24 255.285 ;
     RECT  2.16 255.555 246.24 255.825 ;
     RECT  2.16 256.095 246.24 256.365 ;
     RECT  2.16 256.635 246.24 256.905 ;
     RECT  2.16 257.175 246.24 257.445 ;
     RECT  2.16 257.715 246.24 257.985 ;
     RECT  2.16 258.255 246.24 258.525 ;
     RECT  2.16 258.795 246.24 259.065 ;
     RECT  2.16 259.335 246.24 259.605 ;
     RECT  2.16 259.875 246.24 260.145 ;
     RECT  2.16 260.415 246.24 260.685 ;
     RECT  2.16 260.955 246.24 261.225 ;
     RECT  2.16 261.495 246.24 261.765 ;
     RECT  2.16 262.035 246.24 262.305 ;
     RECT  2.16 262.575 246.24 262.845 ;
     RECT  2.16 263.115 246.24 263.385 ;
     RECT  2.16 263.655 246.24 263.925 ;
     RECT  2.16 264.195 246.24 264.465 ;
     RECT  2.16 264.735 246.24 265.005 ;
     RECT  2.16 265.275 246.24 265.545 ;
     RECT  2.16 265.815 246.24 266.085 ;
     RECT  2.16 266.355 246.24 266.625 ;
     RECT  2.16 266.895 246.24 267.165 ;
     RECT  2.16 267.435 246.24 267.705 ;
     RECT  2.16 267.975 246.24 268.245 ;
     RECT  2.16 268.515 246.24 268.785 ;
     RECT  2.16 269.055 246.24 269.325 ;
     RECT  2.16 269.595 246.24 269.865 ;
     RECT  2.16 270.135 246.24 270.405 ;
     RECT  2.16 270.675 246.24 270.945 ;
     RECT  2.16 271.215 246.24 271.485 ;
     RECT  2.16 271.755 246.24 272.025 ;
     RECT  2.16 272.295 246.24 272.565 ;
     RECT  2.16 272.835 246.24 273.105 ;
     RECT  2.16 273.375 246.24 273.645 ;
     RECT  2.16 273.915 246.24 274.185 ;
     RECT  2.16 274.455 246.24 274.725 ;
     RECT  2.16 274.995 246.24 275.265 ;
     RECT  2.16 275.535 246.24 275.805 ;
     RECT  2.16 276.075 246.24 276.345 ;
     RECT  2.16 276.615 246.24 276.885 ;
     RECT  2.16 277.155 246.24 277.425 ;
     RECT  2.16 277.695 246.24 277.965 ;
     RECT  2.16 278.235 246.24 278.505 ;
     RECT  2.16 278.775 246.24 279.045 ;
     RECT  2.16 279.315 246.24 279.585 ;
     RECT  2.16 279.855 246.24 280.125 ;
     RECT  2.16 280.395 246.24 280.665 ;
     RECT  2.16 280.935 246.24 281.205 ;
     RECT  2.16 281.475 246.24 281.745 ;
     RECT  2.16 282.015 246.24 282.285 ;
     RECT  2.16 282.555 246.24 282.825 ;
     RECT  2.16 283.095 246.24 283.365 ;
     RECT  2.16 283.635 246.24 283.905 ;
     RECT  2.16 284.175 246.24 284.445 ;
     RECT  2.16 284.715 246.24 284.985 ;
     RECT  2.16 285.255 246.24 285.525 ;
     RECT  2.16 285.795 246.24 286.065 ;
     RECT  2.16 286.335 246.24 286.605 ;
     RECT  2.16 286.875 246.24 287.145 ;
     RECT  2.16 287.415 246.24 287.685 ;
     RECT  2.16 287.955 246.24 288.225 ;
     RECT  2.16 288.495 246.24 288.765 ;
     RECT  2.16 289.035 246.24 289.305 ;
     RECT  2.16 289.575 246.24 289.845 ;
     RECT  2.16 290.115 246.24 290.385 ;
     RECT  2.16 290.655 246.24 290.925 ;
     RECT  2.16 291.195 246.24 291.465 ;
     RECT  2.16 291.735 246.24 292.005 ;
     RECT  2.16 292.275 246.24 292.545 ;
     RECT  2.16 292.815 246.24 293.085 ;
     RECT  2.16 293.355 246.24 293.625 ;
     RECT  2.16 293.895 246.24 294.165 ;
     RECT  2.16 294.435 246.24 294.705 ;
     RECT  2.16 294.975 246.24 295.245 ;
     RECT  2.16 295.515 246.24 295.785 ;
     RECT  2.16 296.055 246.24 296.325 ;
     RECT  2.16 296.595 246.24 296.865 ;
     RECT  2.16 297.135 246.24 297.405 ;
     RECT  2.16 297.675 246.24 297.945 ;
     RECT  2.16 298.215 246.24 298.485 ;
     RECT  2.16 298.755 246.24 299.025 ;
     RECT  2.16 299.295 246.24 299.565 ;
     RECT  2.16 299.835 246.24 300.105 ;
     RECT  2.16 300.375 246.24 300.645 ;
     RECT  2.16 300.915 246.24 301.185 ;
     RECT  2.16 301.455 246.24 301.725 ;
     RECT  2.16 301.995 246.24 302.265 ;
     RECT  2.16 302.535 246.24 302.805 ;
     RECT  2.16 303.075 246.24 303.345 ;
     RECT  2.16 303.615 246.24 303.885 ;
     RECT  2.16 304.155 246.24 304.425 ;
     RECT  2.16 304.695 246.24 304.965 ;
     RECT  2.16 305.235 246.24 305.505 ;
     RECT  2.16 305.775 246.24 306.045 ;
     RECT  2.16 306.315 246.24 306.585 ;
     RECT  2.16 306.855 246.24 307.125 ;
     RECT  2.16 307.395 246.24 307.665 ;
     RECT  2.16 307.935 246.24 308.205 ;
     RECT  2.16 308.475 246.24 308.745 ;
     RECT  2.16 309.015 246.24 309.285 ;
     RECT  2.16 309.555 246.24 309.825 ;
     RECT  2.16 310.095 246.24 310.365 ;
     RECT  2.16 310.635 246.24 310.905 ;
     RECT  2.16 311.175 246.24 311.445 ;
     RECT  2.16 311.715 246.24 311.985 ;
     RECT  2.16 312.255 246.24 312.525 ;
     RECT  2.16 312.795 246.24 313.065 ;
     RECT  2.16 313.335 246.24 313.605 ;
     RECT  2.16 313.875 246.24 314.145 ;
     RECT  2.16 314.415 246.24 314.685 ;
     RECT  2.16 314.955 246.24 315.225 ;
     RECT  2.16 315.495 246.24 315.765 ;
     RECT  2.16 316.035 246.24 316.305 ;
     RECT  2.16 316.575 246.24 316.845 ;
     RECT  2.16 317.115 246.24 317.385 ;
     RECT  2.16 317.655 246.24 317.925 ;
     RECT  2.16 318.195 246.24 318.465 ;
     RECT  2.16 318.735 246.24 319.005 ;
     RECT  2.16 319.275 246.24 319.545 ;
     RECT  2.16 319.815 246.24 320.085 ;
     RECT  2.16 320.355 246.24 320.625 ;
     RECT  2.16 320.895 246.24 321.165 ;
     RECT  2.16 321.435 246.24 321.705 ;
     RECT  2.16 321.975 246.24 322.245 ;
     RECT  2.16 322.515 246.24 322.785 ;
     RECT  2.16 323.055 246.24 323.325 ;
     RECT  2.16 323.595 246.24 323.865 ;
     RECT  2.16 324.135 246.24 324.405 ;
     RECT  2.16 324.675 246.24 324.945 ;
     RECT  2.16 325.215 246.24 325.485 ;
     RECT  2.16 325.755 246.24 326.025 ;
     RECT  2.16 326.295 246.24 326.565 ;
     RECT  2.16 326.835 246.24 327.105 ;
     RECT  2.16 327.375 246.24 327.645 ;
     RECT  2.16 327.915 246.24 328.185 ;
     RECT  2.16 328.455 246.24 328.725 ;
     RECT  2.16 328.995 246.24 329.265 ;
     RECT  2.16 329.535 246.24 329.805 ;
     RECT  2.16 330.075 246.24 330.345 ;
     RECT  2.16 330.615 246.24 330.885 ;
     RECT  2.16 331.155 246.24 331.425 ;
     RECT  2.16 331.695 246.24 331.965 ;
     RECT  2.16 332.235 246.24 332.505 ;
     RECT  2.16 332.775 246.24 333.045 ;
     RECT  2.16 333.315 246.24 333.585 ;
     RECT  2.16 333.855 246.24 334.125 ;
     RECT  2.16 334.395 246.24 334.665 ;
     RECT  2.16 334.935 246.24 335.205 ;
     RECT  2.16 335.475 246.24 335.745 ;
     RECT  2.16 336.015 246.24 336.285 ;
     RECT  2.16 336.555 246.24 336.825 ;
     RECT  2.16 337.095 246.24 337.365 ;
     RECT  2.16 337.635 246.24 337.905 ;
     RECT  2.16 338.175 246.24 338.445 ;
     RECT  2.16 338.715 246.24 338.985 ;
     RECT  2.16 339.255 246.24 339.525 ;
     RECT  2.16 339.795 246.24 340.065 ;
     RECT  2.16 340.335 246.24 340.605 ;
     RECT  2.16 340.875 246.24 341.145 ;
     RECT  2.16 341.415 246.24 341.685 ;
     RECT  2.16 341.955 246.24 342.225 ;
     RECT  2.16 342.495 246.24 342.765 ;
     RECT  2.16 343.035 246.24 343.305 ;
     RECT  2.16 343.575 246.24 343.845 ;
     RECT  2.16 344.115 246.24 344.385 ;
     RECT  2.16 344.655 246.24 344.925 ;
     RECT  2.16 345.195 246.24 345.465 ;
     RECT  2.16 345.735 246.24 346.005 ;
     RECT  2.16 346.275 246.24 346.545 ;
     RECT  2.16 346.815 246.24 347.085 ;
     RECT  2.16 347.355 246.24 347.625 ;
     RECT  2.16 347.895 246.24 348.165 ;
     RECT  2.16 348.435 246.24 348.705 ;
     RECT  2.16 348.975 246.24 349.245 ;
     RECT  2.16 349.515 246.24 349.785 ;
     RECT  2.16 350.055 246.24 350.325 ;
     RECT  2.16 350.595 246.24 350.865 ;
     RECT  2.16 351.135 246.24 351.405 ;
     RECT  2.16 351.675 246.24 351.945 ;
     RECT  2.16 352.215 246.24 352.485 ;
     RECT  2.16 352.755 246.24 353.025 ;
     RECT  2.16 353.295 246.24 353.565 ;
     RECT  2.16 353.835 246.24 354.105 ;
     RECT  2.16 354.375 246.24 354.645 ;
     RECT  2.16 354.915 246.24 355.185 ;
     RECT  2.16 355.455 246.24 355.725 ;
     RECT  2.16 355.995 246.24 356.265 ;
     RECT  2.16 356.535 246.24 356.805 ;
     RECT  2.16 357.075 246.24 357.345 ;
     RECT  2.16 357.615 246.24 357.885 ;
     RECT  2.16 358.155 246.24 358.425 ;
     RECT  2.16 358.695 246.24 358.965 ;
     RECT  2.16 359.235 246.24 359.505 ;
     RECT  2.16 359.775 246.24 360.045 ;
     RECT  2.16 360.315 246.24 360.585 ;
     RECT  2.16 360.855 246.24 361.125 ;
     RECT  2.16 361.395 246.24 361.665 ;
     RECT  2.16 361.935 246.24 362.205 ;
     RECT  2.16 362.475 246.24 362.745 ;
     RECT  2.16 363.015 246.24 363.285 ;
     RECT  2.16 363.555 246.24 363.825 ;
     RECT  2.16 364.095 246.24 364.365 ;
     RECT  2.16 364.635 246.24 364.905 ;
     RECT  2.16 365.175 246.24 365.445 ;
     RECT  2.16 365.715 246.24 365.985 ;
     RECT  2.16 366.255 246.24 366.525 ;
     RECT  2.16 366.795 246.24 367.065 ;
     RECT  2.16 367.335 246.24 367.605 ;
     RECT  2.16 367.875 246.24 368.145 ;
     RECT  2.16 368.415 246.24 368.685 ;
     RECT  2.16 368.955 246.24 369.225 ;
    LAYER M1 ;
     RECT  2.16 2.151 246.24 369.369 ;
    LAYER M2 ;
     RECT  0.031 169.362 0.067 169.38 ;
     RECT  0.031 176.652 0.103 176.67 ;
     RECT  0.031 185.904 0.103 185.922 ;
     RECT  0.103 185.328 0.139 185.922 ;
     RECT  0.067 162.99 0.175 163.008 ;
     RECT  0.139 185.328 0.175 186.309 ;
     RECT  0.103 182.394 0.239 182.412 ;
     RECT  0.175 185.328 0.427 186.39 ;
     RECT  0.427 185.328 0.535 186.849 ;
     RECT  0.103 191.772 1.723 191.79 ;
     RECT  0.175 162.918 2.16 163.008 ;
     RECT  0.067 168.696 2.16 169.38 ;
     RECT  0.103 176.652 2.16 177.048 ;
     RECT  0.535 184.86 2.16 186.966 ;
     RECT  1.759 190.692 2.16 190.71 ;
     RECT  1.723 191.502 2.16 191.79 ;
     RECT  2.16 2.151 246.24 369.369 ;
     RECT  246.24 172.566 246.515 173.124 ;
     RECT  246.24 176.076 246.803 180.684 ;
     RECT  246.803 176.076 246.839 180.594 ;
     RECT  246.839 176.49 246.875 178.524 ;
     RECT  246.24 190.116 247.091 190.134 ;
     RECT  246.515 173.106 247.127 173.124 ;
     RECT  246.24 184.446 247.163 184.464 ;
     RECT  246.839 179.856 247.343 180.594 ;
     RECT  246.875 177.426 247.379 178.524 ;
     RECT  247.343 179.856 247.379 180.414 ;
     RECT  246.875 176.526 247.415 176.634 ;
     RECT  247.379 179.856 247.415 180.324 ;
     RECT  247.415 176.616 247.451 176.634 ;
     RECT  247.415 180.126 248.215 180.324 ;
     RECT  248.215 179.586 248.279 180.324 ;
     RECT  247.379 177.696 248.315 177.714 ;
     RECT  248.279 179.586 248.315 180.144 ;
    LAYER M3 ;
     RECT  2.415 2.143 2.505 2.413 ;
     RECT  7.815 2.143 7.905 2.413 ;
     RECT  13.215 2.143 13.305 2.413 ;
     RECT  18.615 2.143 18.705 2.413 ;
     RECT  24.015 2.143 24.105 2.413 ;
     RECT  29.415 2.143 29.505 2.413 ;
     RECT  34.815 2.143 34.905 2.413 ;
     RECT  40.215 2.143 40.305 2.413 ;
     RECT  45.615 2.143 45.705 2.413 ;
     RECT  51.015 2.143 51.105 2.413 ;
     RECT  56.415 2.143 56.505 2.413 ;
     RECT  61.815 2.143 61.905 2.413 ;
     RECT  67.215 2.143 67.305 2.413 ;
     RECT  72.615 2.143 72.705 2.413 ;
     RECT  78.015 2.143 78.105 2.413 ;
     RECT  83.415 2.143 83.505 2.413 ;
     RECT  88.815 2.143 88.905 2.413 ;
     RECT  94.215 2.143 94.305 2.413 ;
     RECT  99.615 2.143 99.705 2.413 ;
     RECT  105.015 2.143 105.105 2.413 ;
     RECT  110.415 2.143 110.505 2.413 ;
     RECT  115.815 2.143 115.905 2.413 ;
     RECT  121.215 2.143 121.305 2.413 ;
     RECT  126.615 2.143 126.705 2.413 ;
     RECT  132.015 2.143 132.105 2.413 ;
     RECT  137.415 2.143 137.505 2.413 ;
     RECT  142.815 2.143 142.905 2.413 ;
     RECT  148.215 2.143 148.305 2.413 ;
     RECT  153.615 2.143 153.705 2.413 ;
     RECT  159.015 2.143 159.105 2.413 ;
     RECT  164.415 2.143 164.505 2.413 ;
     RECT  169.815 2.143 169.905 2.413 ;
     RECT  175.215 2.143 175.305 2.413 ;
     RECT  180.615 2.143 180.705 2.413 ;
     RECT  186.015 2.143 186.105 2.413 ;
     RECT  191.415 2.143 191.505 2.413 ;
     RECT  196.815 2.143 196.905 2.413 ;
     RECT  202.215 2.143 202.305 2.413 ;
     RECT  207.615 2.143 207.705 2.413 ;
     RECT  213.015 2.143 213.105 2.413 ;
     RECT  218.415 2.143 218.505 2.413 ;
     RECT  223.815 2.143 223.905 2.413 ;
     RECT  229.215 2.143 229.305 2.413 ;
     RECT  234.615 2.143 234.705 2.413 ;
     RECT  240.015 2.143 240.105 2.413 ;
     RECT  245.415 2.143 245.505 2.413 ;
     RECT  137.415 2.413 137.697 134.095 ;
     RECT  139.068 134.059 139.086 134.095 ;
     RECT  137.415 134.095 138.186 134.131 ;
     RECT  138.996 134.095 139.086 134.131 ;
     RECT  137.415 134.131 139.446 134.491 ;
     RECT  141.372 134.491 141.39 134.599 ;
     RECT  137.376 134.491 139.446 134.635 ;
     RECT  141.372 134.599 141.462 134.635 ;
     RECT  137.124 134.635 139.446 134.671 ;
     RECT  141.372 134.635 141.678 134.671 ;
     RECT  142.815 2.413 143.097 134.671 ;
     RECT  136.8 134.671 139.446 134.797 ;
     RECT  136.224 134.797 139.446 134.905 ;
     RECT  144.144 134.941 144.162 135.059 ;
     RECT  136.224 134.905 139.626 135.139 ;
     RECT  140.904 134.671 143.097 135.175 ;
     RECT  143.82 135.139 143.838 135.175 ;
     RECT  136.224 135.139 139.914 135.211 ;
     RECT  136.224 135.211 140.166 135.337 ;
     RECT  140.904 135.175 143.838 135.337 ;
     RECT  136.224 135.337 143.838 135.599 ;
     RECT  136.224 135.599 140.922 135.677 ;
     RECT  136.224 135.677 140.634 135.751 ;
     RECT  135.252 135.751 140.634 135.779 ;
     RECT  141.696 135.599 143.838 135.869 ;
     RECT  135.252 135.779 140.13 135.877 ;
     RECT  134.712 135.877 140.13 135.917 ;
     RECT  141.876 135.869 143.838 136.219 ;
     RECT  141.876 136.219 143.946 136.291 ;
     RECT  141.876 136.291 144.27 136.417 ;
     RECT  145.152 136.219 145.17 136.417 ;
     RECT  141.876 136.417 145.566 136.561 ;
     RECT  134.784 135.917 140.13 136.651 ;
     RECT  141.084 136.525 141.102 136.651 ;
     RECT  141.876 136.561 146.034 136.651 ;
     RECT  134.784 136.651 146.034 136.787 ;
     RECT  134.784 136.787 145.494 136.831 ;
     RECT  134.532 136.831 145.494 137.029 ;
     RECT  134.316 137.029 145.494 137.069 ;
     RECT  134.568 137.069 145.494 137.489 ;
     RECT  134.568 137.489 145.206 137.645 ;
     RECT  134.568 137.645 135.846 137.669 ;
     RECT  135.432 137.669 135.846 137.867 ;
     RECT  136.836 137.645 145.206 137.867 ;
     RECT  137.16 137.867 145.206 138.451 ;
     RECT  135.828 137.867 135.846 138.541 ;
     RECT  134.568 137.669 134.586 138.571 ;
     RECT  134.28 138.571 134.586 138.577 ;
     RECT  134.28 138.577 135.09 138.611 ;
     RECT  134.532 138.611 135.09 138.721 ;
     RECT  135.828 138.541 136.098 138.721 ;
     RECT  137.16 138.451 145.602 138.721 ;
     RECT  137.16 138.721 145.818 138.949 ;
     RECT  134.532 138.721 136.098 138.955 ;
     RECT  136.98 138.949 145.818 138.955 ;
     RECT  134.532 138.955 145.818 139.261 ;
     RECT  134.532 139.261 145.89 139.621 ;
     RECT  133.884 139.621 145.89 139.657 ;
     RECT  133.74 139.657 145.89 139.765 ;
     RECT  133.74 139.765 146.214 139.801 ;
     RECT  133.74 139.801 146.682 140.539 ;
     RECT  133.524 140.539 146.682 140.611 ;
     RECT  133.524 140.611 146.754 140.729 ;
     RECT  133.524 140.729 146.574 140.765 ;
     RECT  133.848 140.765 146.574 141.341 ;
     RECT  133.848 141.341 145.53 141.539 ;
     RECT  146.304 141.341 146.574 141.655 ;
     RECT  146.304 141.655 146.934 141.691 ;
     RECT  133.848 141.539 145.35 141.809 ;
     RECT  146.304 141.691 147.186 141.961 ;
     RECT  148.215 2.413 148.497 141.961 ;
     RECT  133.848 141.809 145.17 142.259 ;
     RECT  133.92 142.259 145.17 142.349 ;
     RECT  146.304 141.961 148.497 142.429 ;
     RECT  146.052 142.429 148.497 142.735 ;
     RECT  134.568 142.349 145.17 142.771 ;
     RECT  146.016 142.735 148.734 142.771 ;
     RECT  134.568 142.771 148.734 142.897 ;
     RECT  149.58 142.771 149.598 142.897 ;
     RECT  134.568 142.897 149.598 142.933 ;
     RECT  134.568 142.933 149.814 142.939 ;
     RECT  134.568 142.939 149.958 143.131 ;
     RECT  134.568 143.131 150.498 143.437 ;
     RECT  134.568 143.437 150.714 143.545 ;
     RECT  134.532 143.545 150.714 143.581 ;
     RECT  134.532 143.581 151.218 143.735 ;
     RECT  134.532 143.735 150.462 143.815 ;
     RECT  151.2 143.735 151.218 143.843 ;
     RECT  134.208 143.815 150.462 144.661 ;
     RECT  134.208 144.661 150.966 144.779 ;
     RECT  134.208 144.779 150.534 145.049 ;
     RECT  134.208 145.049 150.246 145.085 ;
     RECT  146.412 145.085 150.246 145.193 ;
     RECT  146.772 145.193 150.246 145.319 ;
     RECT  134.208 145.085 145.638 145.339 ;
     RECT  133.848 145.339 145.638 145.915 ;
     RECT  146.772 145.319 149.922 145.915 ;
     RECT  133.848 145.915 149.922 146.281 ;
     RECT  151.704 146.371 151.722 146.395 ;
     RECT  133.848 146.281 150.246 146.399 ;
     RECT  151.38 146.395 151.722 146.429 ;
     RECT  133.848 146.399 149.922 146.551 ;
     RECT  133.308 146.551 149.922 146.635 ;
     RECT  132.015 2.413 132.297 146.641 ;
     RECT  133.164 146.635 149.922 146.641 ;
     RECT  132.015 146.641 149.922 146.669 ;
     RECT  151.38 146.429 151.398 147.053 ;
     RECT  145.296 146.669 149.922 147.289 ;
     RECT  145.296 147.289 150.246 147.559 ;
     RECT  132.015 146.669 144.486 147.595 ;
     RECT  145.296 147.559 150.462 147.595 ;
     RECT  132.015 147.595 151.11 148.171 ;
     RECT  132.015 148.171 151.146 148.289 ;
     RECT  146.412 148.289 151.146 148.441 ;
     RECT  146.412 148.441 151.182 148.631 ;
     RECT  132.015 148.289 145.602 148.675 ;
     RECT  131.94 148.675 145.602 148.711 ;
     RECT  146.448 148.631 151.182 149.071 ;
     RECT  131.724 148.711 145.602 149.179 ;
     RECT  131.58 149.179 145.602 149.323 ;
     RECT  131.076 149.323 145.602 149.413 ;
     RECT  146.448 149.071 151.614 149.413 ;
     RECT  131.076 149.413 151.614 149.945 ;
     RECT  131.436 149.945 151.614 150.961 ;
     RECT  131.04 150.961 151.614 150.997 ;
     RECT  130.86 150.997 151.614 151.037 ;
     RECT  131.04 151.037 151.614 151.169 ;
     RECT  131.04 151.169 151.578 151.951 ;
     RECT  131.04 151.951 151.758 151.979 ;
     RECT  131.616 151.979 151.758 152.069 ;
     RECT  131.616 152.069 151.614 152.779 ;
     RECT  131.148 152.779 151.614 152.851 ;
     RECT  131.148 152.851 151.866 153.023 ;
     RECT  131.148 153.023 151.074 153.419 ;
     RECT  131.94 153.419 151.074 153.841 ;
     RECT  151.848 153.023 151.866 153.841 ;
     RECT  131.148 153.419 131.166 153.967 ;
     RECT  129.456 153.883 129.474 154.039 ;
     RECT  130.824 153.967 131.166 154.039 ;
     RECT  155.88 154.039 155.898 154.111 ;
     RECT  153.615 2.413 153.897 154.219 ;
     RECT  155.124 154.111 155.142 154.219 ;
     RECT  153.615 154.219 155.142 154.237 ;
     RECT  155.88 154.111 155.934 154.237 ;
     RECT  157.284 154.039 157.302 154.237 ;
     RECT  153.615 154.237 155.934 154.301 ;
     RECT  129.456 154.039 131.166 154.309 ;
     RECT  131.94 153.841 151.866 154.309 ;
     RECT  154.944 154.301 155.934 154.345 ;
     RECT  156.744 154.237 157.554 154.345 ;
     RECT  129.456 154.309 151.866 154.381 ;
     RECT  154.944 154.345 157.554 154.381 ;
     RECT  154.944 154.381 158.022 154.535 ;
     RECT  158.004 154.535 158.022 154.643 ;
     RECT  154.944 154.535 157.122 154.769 ;
     RECT  129.456 154.381 151.938 154.777 ;
     RECT  129.132 154.777 151.938 154.885 ;
     RECT  128.016 155.155 128.034 155.191 ;
     RECT  128.772 154.885 151.938 155.191 ;
     RECT  128.016 155.191 151.938 155.309 ;
     RECT  159.015 2.413 159.297 155.353 ;
     RECT  158.436 155.353 159.297 155.425 ;
     RECT  152.712 155.191 152.73 155.461 ;
     RECT  153.615 154.301 153.897 155.461 ;
     RECT  128.16 155.309 151.938 155.579 ;
     RECT  152.712 155.461 153.897 155.579 ;
     RECT  154.944 154.769 156.978 155.611 ;
     RECT  128.52 155.579 151.938 155.659 ;
     RECT  152.712 155.579 152.766 155.659 ;
     RECT  158.004 155.425 159.297 155.659 ;
     RECT  153.615 155.579 153.897 155.695 ;
     RECT  154.944 155.611 157.194 155.695 ;
     RECT  153.615 155.695 157.194 156.271 ;
     RECT  157.968 155.659 159.297 156.271 ;
     RECT  128.52 155.659 152.766 156.397 ;
     RECT  128.124 156.397 152.766 156.541 ;
     RECT  153.615 156.271 159.297 156.541 ;
     RECT  128.124 156.541 159.297 156.703 ;
     RECT  127.908 156.703 159.297 156.811 ;
     RECT  127.836 156.811 159.297 156.937 ;
     RECT  127.692 156.937 159.297 157.343 ;
     RECT  127.692 157.343 157.986 157.577 ;
     RECT  126.615 2.413 126.897 157.981 ;
     RECT  126.144 157.981 126.897 158.045 ;
     RECT  133.092 157.577 157.986 158.089 ;
     RECT  159.015 157.343 159.297 158.089 ;
     RECT  126.54 158.045 126.897 158.161 ;
     RECT  127.692 157.577 132.297 158.161 ;
     RECT  126.54 158.161 132.297 158.299 ;
     RECT  133.092 158.089 159.297 158.299 ;
     RECT  126.54 158.299 159.297 158.549 ;
     RECT  126.54 158.549 158.202 158.585 ;
     RECT  126.54 158.585 157.986 158.621 ;
     RECT  126.54 158.621 157.95 158.729 ;
     RECT  126.54 158.729 151.578 159.205 ;
     RECT  126.396 159.205 151.578 159.241 ;
     RECT  125.748 159.241 151.578 159.359 ;
     RECT  126.396 159.359 151.578 159.475 ;
     RECT  152.388 158.729 157.95 159.475 ;
     RECT  126.396 159.475 157.95 159.503 ;
     RECT  125.604 159.511 125.622 159.581 ;
     RECT  126.615 159.503 157.95 159.637 ;
     RECT  126.615 159.637 158.094 159.781 ;
     RECT  159.015 158.549 159.297 159.781 ;
     RECT  126.615 159.781 159.297 160.007 ;
     RECT  126.615 160.007 158.022 160.439 ;
     RECT  126.615 160.439 157.59 160.709 ;
     RECT  126.615 160.709 157.302 160.747 ;
     RECT  126.432 160.747 157.302 161.285 ;
     RECT  126.432 161.285 127.098 161.293 ;
     RECT  127.872 161.285 157.302 161.627 ;
     RECT  123.48 161.671 123.498 161.755 ;
     RECT  125.028 161.671 125.046 161.789 ;
     RECT  127.872 161.627 156.87 161.789 ;
     RECT  128.052 161.789 156.87 161.825 ;
     RECT  123.48 161.755 123.786 161.833 ;
     RECT  124.56 161.797 124.578 161.833 ;
     RECT  156.24 161.825 156.87 161.861 ;
     RECT  126.144 161.293 127.098 162.031 ;
     RECT  123.48 161.833 124.578 162.095 ;
     RECT  126.144 162.031 127.134 162.331 ;
     RECT  123.48 162.095 124.542 162.409 ;
     RECT  125.748 162.331 127.134 162.409 ;
     RECT  123.408 162.409 124.542 162.481 ;
     RECT  121.215 2.413 121.497 162.607 ;
     RECT  122.292 162.571 122.31 162.607 ;
     RECT  121.215 162.607 122.31 162.635 ;
     RECT  2.415 2.413 2.697 162.751 ;
     RECT  125.748 162.409 127.242 162.751 ;
     RECT  156.852 161.861 156.87 162.751 ;
     RECT  125.28 162.751 127.242 162.779 ;
     RECT  123.372 162.481 124.542 162.841 ;
     RECT  125.28 162.779 125.298 162.841 ;
     RECT  128.052 161.825 155.502 162.841 ;
     RECT  2.415 162.751 2.826 162.869 ;
     RECT  121.215 162.635 121.878 162.869 ;
     RECT  128.052 162.841 155.79 162.877 ;
     RECT  126.072 162.779 127.242 162.905 ;
     RECT  128.052 162.877 155.898 162.913 ;
     RECT  156.672 162.751 156.87 162.913 ;
     RECT  126.324 162.905 127.242 162.949 ;
     RECT  128.052 162.913 156.87 162.949 ;
     RECT  0.18 162.913 0.198 162.955 ;
     RECT  0.144 162.955 0.198 162.985 ;
     RECT  126.324 162.949 156.87 163.013 ;
     RECT  126.36 163.013 156.87 163.021 ;
     RECT  121.215 162.869 121.734 163.139 ;
     RECT  123.372 162.841 125.298 163.139 ;
     RECT  0.072 162.985 0.234 163.181 ;
     RECT  123.372 163.139 125.226 163.183 ;
     RECT  2.415 162.869 2.697 163.255 ;
     RECT  0.072 163.181 0.198 163.277 ;
     RECT  2.304 163.255 2.697 163.373 ;
     RECT  122.868 163.183 125.226 163.409 ;
     RECT  0.072 163.277 0.126 163.531 ;
     RECT  126.36 163.021 157.158 163.553 ;
     RECT  0.036 163.531 0.126 163.565 ;
     RECT  126.36 163.553 157.122 163.715 ;
     RECT  126.36 163.715 157.05 163.787 ;
     RECT  126.36 163.787 156.87 163.831 ;
     RECT  122.94 163.409 125.226 164.101 ;
     RECT  125.964 163.831 156.87 164.101 ;
     RECT  122.94 164.101 156.87 164.299 ;
     RECT  122.904 164.299 156.87 164.731 ;
     RECT  122.868 164.731 156.87 164.875 ;
     RECT  122.868 164.875 157.194 165.145 ;
     RECT  122.76 165.145 157.194 165.209 ;
     RECT  122.76 165.209 156.87 165.335 ;
     RECT  122.868 165.335 156.87 165.713 ;
     RECT  123.048 165.713 156.87 166.081 ;
     RECT  123.048 166.081 156.942 166.225 ;
     RECT  123.048 166.225 157.446 166.379 ;
     RECT  123.048 166.379 156.942 166.507 ;
     RECT  122.76 166.507 156.942 166.523 ;
     RECT  115.815 2.413 116.097 166.801 ;
     RECT  115.704 166.801 116.097 166.891 ;
     RECT  121.215 163.139 121.497 166.891 ;
     RECT  115.704 166.891 116.262 166.928 ;
     RECT  121.104 166.891 121.497 166.928 ;
     RECT  115.704 166.928 116.097 167.021 ;
     RECT  122.76 166.523 156.87 167.341 ;
     RECT  122.76 167.341 157.59 167.459 ;
     RECT  122.76 167.459 122.778 167.567 ;
     RECT  123.66 167.459 157.59 167.729 ;
     RECT  124.128 167.729 157.05 167.765 ;
     RECT  124.128 167.765 156.87 167.837 ;
     RECT  124.848 167.837 156.87 168.143 ;
     RECT  2.415 163.373 2.697 168.655 ;
     RECT  0.036 163.565 0.09 168.719 ;
     RECT  157.608 168.817 157.626 168.853 ;
     RECT  88.815 2.413 89.097 168.961 ;
     RECT  124.848 168.143 129.654 168.961 ;
     RECT  130.572 168.143 156.87 168.961 ;
     RECT  157.608 168.853 157.77 168.961 ;
     RECT  2.415 168.655 2.862 168.989 ;
     RECT  124.848 168.961 129.726 169.051 ;
     RECT  88.815 168.961 89.478 169.079 ;
     RECT  90.648 169.051 90.666 169.151 ;
     RECT  105.015 2.413 105.297 169.357 ;
     RECT  106.056 169.231 106.074 169.357 ;
     RECT  0.036 168.719 0.054 169.385 ;
     RECT  124.668 169.051 129.726 169.393 ;
     RECT  104.904 169.357 106.074 169.501 ;
     RECT  124.416 169.393 129.726 169.501 ;
     RECT  130.572 168.961 158.094 169.501 ;
     RECT  103.5 169.579 103.518 169.619 ;
     RECT  124.416 169.501 158.094 169.771 ;
     RECT  159.015 160.007 159.297 169.771 ;
     RECT  124.416 169.771 159.297 169.861 ;
     RECT  104.904 169.501 106.11 169.897 ;
     RECT  124.2 169.861 159.297 170.041 ;
     RECT  124.164 170.041 159.297 170.239 ;
     RECT  124.092 170.239 159.297 170.299 ;
     RECT  103.572 170.299 103.59 170.401 ;
     RECT  99.615 2.413 99.897 170.581 ;
     RECT  103.032 170.401 103.59 170.581 ;
     RECT  104.796 169.897 106.11 170.581 ;
     RECT  99.615 170.581 100.314 170.707 ;
     RECT  97.92 170.707 97.938 170.851 ;
     RECT  99.036 170.707 100.314 170.851 ;
     RECT  101.844 170.581 101.862 170.851 ;
     RECT  103.032 170.581 103.734 170.851 ;
     RECT  104.508 170.581 106.11 170.851 ;
     RECT  123.768 170.299 159.297 170.909 ;
     RECT  97.488 170.851 100.602 170.941 ;
     RECT  101.808 170.851 102.222 170.971 ;
     RECT  103.032 170.851 106.11 170.971 ;
     RECT  97.164 170.941 100.602 170.977 ;
     RECT  101.808 170.971 106.11 170.977 ;
     RECT  97.164 170.977 106.11 171.013 ;
     RECT  121.215 166.928 121.497 171.211 ;
     RECT  97.128 171.013 106.11 171.247 ;
     RECT  121.104 171.211 121.497 171.248 ;
     RECT  97.056 171.247 106.11 171.319 ;
     RECT  97.056 171.319 106.146 171.509 ;
     RECT  123.156 171.517 123.174 171.661 ;
     RECT  123.912 170.909 159.297 171.661 ;
     RECT  98.424 171.509 106.146 171.931 ;
     RECT  245.415 2.413 245.697 172.165 ;
     RECT  98.424 171.931 106.29 172.201 ;
     RECT  98.424 172.201 106.326 172.291 ;
     RECT  244.152 172.201 244.17 172.319 ;
     RECT  98.172 172.291 106.326 172.399 ;
     RECT  97.056 171.509 97.362 172.435 ;
     RECT  98.1 172.399 106.326 172.435 ;
     RECT  245.088 172.165 245.697 172.435 ;
     RECT  97.056 172.435 106.326 172.471 ;
     RECT  121.215 171.248 121.497 172.471 ;
     RECT  122.328 172.093 122.346 172.471 ;
     RECT  123.156 171.661 159.297 172.471 ;
     RECT  122.328 172.471 159.297 172.633 ;
     RECT  244.548 172.435 245.697 172.669 ;
     RECT  246.492 172.561 246.51 172.669 ;
     RECT  97.056 172.471 106.506 172.741 ;
     RECT  122.328 172.633 159.642 172.859 ;
     RECT  244.548 172.669 246.51 172.859 ;
     RECT  245.16 172.859 246.51 173.101 ;
     RECT  245.16 173.101 247.122 173.165 ;
     RECT  97.056 172.741 106.542 173.245 ;
     RECT  96.156 172.435 96.174 173.323 ;
     RECT  97.056 173.245 106.686 173.323 ;
     RECT  123.12 172.859 159.297 173.399 ;
     RECT  158.616 173.399 159.297 173.435 ;
     RECT  122.328 172.859 122.346 173.911 ;
     RECT  123.12 173.399 157.842 173.911 ;
     RECT  122.328 173.911 157.842 174.253 ;
     RECT  122.328 174.253 157.986 174.281 ;
     RECT  159.015 173.435 159.297 174.361 ;
     RECT  245.415 173.165 247.122 174.631 ;
     RECT  166.968 174.721 166.986 174.757 ;
     RECT  96.156 173.323 106.686 174.763 ;
     RECT  166.392 174.757 166.986 174.797 ;
     RECT  245.196 174.631 247.122 174.811 ;
     RECT  96.156 174.763 106.722 174.901 ;
     RECT  107.46 170.401 107.478 174.901 ;
     RECT  244.008 174.901 244.026 174.991 ;
     RECT  244.872 174.811 247.122 174.991 ;
     RECT  164.415 2.413 164.697 175.003 ;
     RECT  175.215 2.413 175.497 175.003 ;
     RECT  186.015 2.413 186.297 175.003 ;
     RECT  196.815 2.413 197.097 175.003 ;
     RECT  207.615 2.413 207.897 175.003 ;
     RECT  218.415 2.413 218.697 175.003 ;
     RECT  229.215 2.413 229.497 175.003 ;
     RECT  240.015 2.413 240.297 175.003 ;
     RECT  121.14 172.471 121.497 175.027 ;
     RECT  122.328 174.281 127.422 175.027 ;
     RECT  239.904 175.003 240.297 175.055 ;
     RECT  121.14 175.027 127.422 175.063 ;
     RECT  121.104 175.063 127.422 175.093 ;
     RECT  128.16 174.281 157.986 175.093 ;
     RECT  121.104 175.093 157.986 175.099 ;
     RECT  158.94 174.361 159.297 175.099 ;
     RECT  96.156 174.901 107.478 175.135 ;
     RECT  121.104 175.099 158.022 175.135 ;
     RECT  158.796 175.099 159.297 175.135 ;
     RECT  96.084 175.135 107.478 175.171 ;
     RECT  243.216 173.011 243.234 175.261 ;
     RECT  108.324 175.171 108.342 175.369 ;
     RECT  242.712 175.261 243.234 175.373 ;
     RECT  95.94 175.171 107.478 175.405 ;
     RECT  108.324 175.369 108.378 175.405 ;
     RECT  95.94 175.405 108.378 175.441 ;
     RECT  95.76 175.441 108.378 175.469 ;
     RECT  164.304 175.003 164.697 175.469 ;
     RECT  238.284 175.339 238.302 175.469 ;
     RECT  95.76 175.469 108.342 175.567 ;
     RECT  95.292 175.567 108.342 175.595 ;
     RECT  94.215 2.413 94.497 175.711 ;
     RECT  95.292 175.595 108.234 175.711 ;
     RECT  121.104 175.135 159.297 175.739 ;
     RECT  242.784 175.373 243.234 175.915 ;
     RECT  244.008 174.991 247.122 175.915 ;
     RECT  240.015 175.055 240.297 175.963 ;
     RECT  164.415 175.469 164.697 175.981 ;
     RECT  162.468 175.867 162.486 175.997 ;
     RECT  175.104 175.003 175.497 176.009 ;
     RECT  185.904 175.003 186.297 176.009 ;
     RECT  196.704 175.003 197.097 176.009 ;
     RECT  207.504 175.003 207.897 176.009 ;
     RECT  218.304 175.003 218.697 176.009 ;
     RECT  229.104 175.003 229.497 176.009 ;
     RECT  239.904 175.963 240.297 176.009 ;
     RECT  164.415 175.981 165.258 176.045 ;
     RECT  94.215 175.711 108.234 176.099 ;
     RECT  120.168 175.981 120.186 176.099 ;
     RECT  94.215 176.099 94.497 176.251 ;
     RECT  121.104 175.739 154.89 176.251 ;
     RECT  242.784 175.915 247.122 176.251 ;
     RECT  160.056 176.251 160.074 176.341 ;
     RECT  164.415 176.045 164.79 176.341 ;
     RECT  120.492 176.251 154.89 176.369 ;
     RECT  164.088 176.341 164.79 176.381 ;
     RECT  242.244 176.251 247.122 176.381 ;
     RECT  164.415 176.381 164.79 176.441 ;
     RECT  160.02 176.341 160.074 176.477 ;
     RECT  95.292 176.099 108.234 176.513 ;
     RECT  118.656 176.449 118.674 176.521 ;
     RECT  121.104 176.369 154.89 176.521 ;
     RECT  155.628 175.739 159.297 176.521 ;
     RECT  244.296 176.381 247.122 176.521 ;
     RECT  94.176 176.251 94.497 176.549 ;
     RECT  118.584 176.521 118.674 176.549 ;
     RECT  244.296 176.521 247.41 176.611 ;
     RECT  118.584 176.549 118.602 176.639 ;
     RECT  242.244 176.381 243.558 176.675 ;
     RECT  242.244 176.675 243.234 176.711 ;
     RECT  121.104 176.521 159.297 176.791 ;
     RECT  160.02 176.477 160.038 176.791 ;
     RECT  95.292 176.513 107.73 176.909 ;
     RECT  121.104 176.791 160.038 176.909 ;
     RECT  108.504 176.683 108.522 176.917 ;
     RECT  95.292 176.909 106.866 176.945 ;
     RECT  108.504 176.917 108.666 176.989 ;
     RECT  244.296 176.611 247.446 177.005 ;
     RECT  95.292 176.945 106.758 177.017 ;
     RECT  0.036 176.647 0.054 177.025 ;
     RECT  108.504 176.989 108.738 177.061 ;
     RECT  109.548 177.025 109.566 177.061 ;
     RECT  121.104 176.909 159.642 177.089 ;
     RECT  108.504 177.061 109.566 177.151 ;
     RECT  110.415 2.413 110.697 177.151 ;
     RECT  94.215 176.549 94.497 177.187 ;
     RECT  95.292 177.017 106.542 177.187 ;
     RECT  94.215 177.187 106.542 177.245 ;
     RECT  107.712 176.909 107.73 177.295 ;
     RECT  108.504 177.151 110.697 177.521 ;
     RECT  107.712 177.295 107.766 177.601 ;
     RECT  108.504 177.521 109.026 177.601 ;
     RECT  248.292 177.067 248.31 177.719 ;
     RECT  95.652 177.245 106.542 177.799 ;
     RECT  107.712 177.601 109.026 177.799 ;
     RECT  121.104 177.089 159.297 177.997 ;
     RECT  242.784 176.711 243.234 177.997 ;
     RECT  242.244 177.997 243.234 178.033 ;
     RECT  3.852 176.071 3.87 178.105 ;
     RECT  242.244 178.033 243.558 178.105 ;
     RECT  244.296 177.005 247.374 178.105 ;
     RECT  242.244 178.105 247.374 178.169 ;
     RECT  242.784 178.169 247.374 178.295 ;
     RECT  95.652 177.799 109.026 178.411 ;
     RECT  109.764 177.521 110.697 178.411 ;
     RECT  95.652 178.411 110.697 178.501 ;
     RECT  245.088 178.295 247.374 178.529 ;
     RECT  243.216 178.295 244.314 178.601 ;
     RECT  95.436 178.501 110.697 178.609 ;
     RECT  95.4 178.609 110.697 178.637 ;
     RECT  94.215 177.245 94.497 178.681 ;
     RECT  95.4 178.637 98.118 178.681 ;
     RECT  98.964 178.637 110.697 178.681 ;
     RECT  98.964 178.681 110.79 178.709 ;
     RECT  245.088 178.529 247.158 178.709 ;
     RECT  165.744 178.555 165.762 178.771 ;
     RECT  165.744 178.771 166.446 178.799 ;
     RECT  243.396 178.601 244.314 178.799 ;
     RECT  165.996 178.799 166.446 178.829 ;
     RECT  99.072 178.709 110.79 178.907 ;
     RECT  162.468 178.807 162.486 178.907 ;
     RECT  165.996 178.829 166.014 178.907 ;
     RECT  94.215 178.681 98.118 178.979 ;
     RECT  160.596 178.843 160.614 179.069 ;
     RECT  121.104 177.997 159.642 179.077 ;
     RECT  121.104 179.077 159.678 179.117 ;
     RECT  243.9 178.799 244.314 179.213 ;
     RECT  245.124 178.709 247.158 179.309 ;
     RECT  95.4 178.979 98.118 179.371 ;
     RECT  245.124 179.309 246.258 179.405 ;
     RECT  95.4 179.371 98.154 179.491 ;
     RECT  99.072 178.907 110.697 179.491 ;
     RECT  118.584 179.221 118.602 179.519 ;
     RECT  248.22 178.987 248.238 179.563 ;
     RECT  2.415 168.989 2.697 179.581 ;
     RECT  121.104 179.117 159.606 179.609 ;
     RECT  245.124 179.405 246.114 179.611 ;
     RECT  248.22 179.563 248.31 179.645 ;
     RECT  95.4 179.491 110.697 179.755 ;
     RECT  94.215 178.979 94.497 179.761 ;
     RECT  95.256 179.755 110.697 179.795 ;
     RECT  247.068 179.309 247.158 179.851 ;
     RECT  245.052 179.611 246.114 179.899 ;
     RECT  94.176 179.761 94.497 179.915 ;
     RECT  245.016 179.899 246.114 180.139 ;
     RECT  247.068 179.851 247.41 180.139 ;
     RECT  248.256 179.645 248.31 180.149 ;
     RECT  243.9 179.213 243.918 180.265 ;
     RECT  164.415 176.441 164.697 180.283 ;
     RECT  175.215 176.009 175.497 180.283 ;
     RECT  186.015 176.009 186.297 180.283 ;
     RECT  196.815 176.009 197.097 180.283 ;
     RECT  207.615 176.009 207.897 180.283 ;
     RECT  218.415 176.009 218.697 180.283 ;
     RECT  229.215 176.009 229.497 180.283 ;
     RECT  240.015 176.009 240.297 180.283 ;
     RECT  243.9 180.265 243.954 180.283 ;
     RECT  245.016 180.139 247.41 180.301 ;
     RECT  164.304 180.283 164.697 180.329 ;
     RECT  175.104 180.283 175.497 180.329 ;
     RECT  185.904 180.283 186.297 180.329 ;
     RECT  196.704 180.283 197.097 180.329 ;
     RECT  207.504 180.283 207.897 180.329 ;
     RECT  218.304 180.283 218.697 180.329 ;
     RECT  229.104 180.283 229.497 180.329 ;
     RECT  239.904 180.283 240.297 180.329 ;
     RECT  248.256 180.149 248.274 180.329 ;
     RECT  244.692 180.301 247.41 180.365 ;
     RECT  2.415 179.581 3.006 180.391 ;
     RECT  3.852 178.105 3.942 180.391 ;
     RECT  243.828 180.283 243.954 180.419 ;
     RECT  244.692 180.365 247.374 180.419 ;
     RECT  95.364 179.795 110.697 180.463 ;
     RECT  94.215 179.915 94.497 180.535 ;
     RECT  95.364 180.463 111.006 180.535 ;
     RECT  244.692 180.419 247.338 180.571 ;
     RECT  244.224 180.571 247.338 180.599 ;
     RECT  244.224 180.599 247.158 180.689 ;
     RECT  121.104 179.609 159.297 180.733 ;
     RECT  94.215 180.535 111.006 181.273 ;
     RECT  120.852 180.733 159.297 181.471 ;
     RECT  244.224 180.689 246.114 181.499 ;
     RECT  120.312 181.471 159.297 181.579 ;
     RECT  112.356 181.627 112.374 181.741 ;
     RECT  112.356 181.741 112.662 181.769 ;
     RECT  112.644 181.769 112.662 181.805 ;
     RECT  120.204 181.579 159.297 181.813 ;
     RECT  120.06 181.813 159.297 181.949 ;
     RECT  0.036 177.025 0.126 182.389 ;
     RECT  116.964 182.425 116.982 182.443 ;
     RECT  116.892 182.443 116.982 182.461 ;
     RECT  244.224 181.499 244.242 182.489 ;
     RECT  94.215 181.273 111.186 182.579 ;
     RECT  116.892 182.461 117.018 182.579 ;
     RECT  120.06 181.949 156.078 182.695 ;
     RECT  156.96 181.949 159.297 182.695 ;
     RECT  116.856 182.731 116.874 182.885 ;
     RECT  120.06 182.695 159.297 182.885 ;
     RECT  120.276 182.885 159.297 183.005 ;
     RECT  94.215 182.579 111.042 183.029 ;
     RECT  122.724 183.005 159.297 183.263 ;
     RECT  245.016 181.499 246.114 183.505 ;
     RECT  242.244 183.433 242.262 183.533 ;
     RECT  244.836 183.505 246.114 183.659 ;
     RECT  120.276 183.005 121.986 183.811 ;
     RECT  122.724 183.263 157.986 183.811 ;
     RECT  94.215 183.029 110.697 184.045 ;
     RECT  120.276 183.811 157.986 184.073 ;
     RECT  94.104 184.045 110.697 184.109 ;
     RECT  120.276 184.073 121.77 184.199 ;
     RECT  93.24 184.309 93.258 184.349 ;
     RECT  94.215 184.109 110.697 184.351 ;
     RECT  159.015 183.263 159.297 184.441 ;
     RECT  247.068 180.689 247.158 184.469 ;
     RECT  94.215 184.351 110.754 184.541 ;
     RECT  120.276 184.199 120.366 184.541 ;
     RECT  2.415 180.391 3.942 184.739 ;
     RECT  0.036 182.389 0.234 184.855 ;
     RECT  122.76 184.073 157.986 184.855 ;
     RECT  93.384 184.351 93.402 185.045 ;
     RECT  160.164 183.631 160.182 185.189 ;
     RECT  94.215 184.541 110.697 185.275 ;
     RECT  122.688 184.855 157.986 185.275 ;
     RECT  245.016 183.659 246.114 185.279 ;
     RECT  122.688 185.275 158.022 185.287 ;
     RECT  94.032 185.275 110.697 185.315 ;
     RECT  121.104 184.199 121.77 185.323 ;
     RECT  122.544 185.287 158.022 185.323 ;
     RECT  90.648 185.287 90.666 185.359 ;
     RECT  2.415 184.739 3.87 185.395 ;
     RECT  120.348 184.541 120.366 185.431 ;
     RECT  121.104 185.323 158.022 185.431 ;
     RECT  2.304 185.395 3.87 185.521 ;
     RECT  94.032 185.315 100.638 185.549 ;
     RECT  120.348 185.431 158.022 185.549 ;
     RECT  158.94 184.441 159.297 185.549 ;
     RECT  245.016 185.279 245.754 185.549 ;
     RECT  120.348 185.549 157.986 185.557 ;
     RECT  120.24 185.557 157.986 185.597 ;
     RECT  245.016 185.549 245.697 185.665 ;
     RECT  120.348 185.597 157.986 185.741 ;
     RECT  94.032 185.549 100.566 185.819 ;
     RECT  120.348 185.741 156.222 185.819 ;
     RECT  0.036 184.855 0.558 185.927 ;
     RECT  120.348 185.819 156.15 186.125 ;
     RECT  0.108 185.927 0.558 186.205 ;
     RECT  94.032 185.819 100.35 186.241 ;
     RECT  0.108 186.205 0.594 186.314 ;
     RECT  101.412 185.315 110.697 186.331 ;
     RECT  164.415 180.329 164.697 186.331 ;
     RECT  175.215 180.329 175.497 186.331 ;
     RECT  186.015 180.329 186.297 186.331 ;
     RECT  196.815 180.329 197.097 186.331 ;
     RECT  207.615 180.329 207.897 186.331 ;
     RECT  218.415 180.329 218.697 186.331 ;
     RECT  229.215 180.329 229.497 186.331 ;
     RECT  240.015 180.329 240.297 186.331 ;
     RECT  244.8 185.665 245.697 186.331 ;
     RECT  2.304 185.521 3.906 186.359 ;
     RECT  90.648 185.359 90.702 186.359 ;
     RECT  118.584 186.205 118.602 186.359 ;
     RECT  244.152 186.331 245.697 186.359 ;
     RECT  92.916 186.241 92.934 186.367 ;
     RECT  93.96 186.241 100.35 186.367 ;
     RECT  164.304 186.331 164.697 186.368 ;
     RECT  175.104 186.331 175.497 186.368 ;
     RECT  185.904 186.331 186.297 186.368 ;
     RECT  196.704 186.331 197.097 186.368 ;
     RECT  207.504 186.331 207.897 186.368 ;
     RECT  218.304 186.331 218.697 186.368 ;
     RECT  229.104 186.331 229.497 186.368 ;
     RECT  239.904 186.331 240.297 186.368 ;
     RECT  244.152 186.359 244.17 186.368 ;
     RECT  101.412 186.331 110.79 186.395 ;
     RECT  0.108 186.314 0.558 186.413 ;
     RECT  120.672 186.125 156.15 186.601 ;
     RECT  0.144 186.413 0.558 186.605 ;
     RECT  2.304 186.359 3.87 186.629 ;
     RECT  92.916 186.367 100.35 186.629 ;
     RECT  94.14 186.629 100.35 186.673 ;
     RECT  101.412 186.395 110.697 186.673 ;
     RECT  2.304 186.629 3.402 186.709 ;
     RECT  94.14 186.673 110.697 186.737 ;
     RECT  120.672 186.601 156.186 186.745 ;
     RECT  156.96 185.741 157.986 186.745 ;
     RECT  2.088 186.709 3.402 186.773 ;
     RECT  90.648 186.359 90.666 186.773 ;
     RECT  94.14 186.737 100.89 186.809 ;
     RECT  2.088 186.773 3.258 186.854 ;
     RECT  92.916 186.629 93.366 186.871 ;
     RECT  92.196 186.871 93.366 186.941 ;
     RECT  0.18 186.605 0.558 186.989 ;
     RECT  0.18 186.989 0.522 187.085 ;
     RECT  6.804 185.971 6.822 187.169 ;
     RECT  0.18 187.085 0.486 187.181 ;
     RECT  0.432 187.181 0.486 187.277 ;
     RECT  94.14 186.809 100.818 187.555 ;
     RECT  0.432 187.277 0.45 187.565 ;
     RECT  94.14 187.555 101.142 187.681 ;
     RECT  101.916 186.737 110.697 187.681 ;
     RECT  111.744 186.601 111.762 187.681 ;
     RECT  2.268 186.854 3.258 187.709 ;
     RECT  92.628 186.941 92.646 187.709 ;
     RECT  111.744 187.681 111.978 187.753 ;
     RECT  2.268 187.709 3.006 187.819 ;
     RECT  111.744 187.753 112.122 187.861 ;
     RECT  94.14 187.681 110.697 187.889 ;
     RECT  90.72 187.789 90.738 187.951 ;
     RECT  92.916 187.825 92.934 187.951 ;
     RECT  113.004 187.681 113.022 187.951 ;
     RECT  90.648 187.951 90.738 187.979 ;
     RECT  111.744 187.861 112.266 187.987 ;
     RECT  113.004 187.951 113.058 187.987 ;
     RECT  114.588 187.861 114.606 188.015 ;
     RECT  92.916 187.951 93.15 188.023 ;
     RECT  98.496 187.889 110.697 188.059 ;
     RECT  111.744 187.987 113.058 188.059 ;
     RECT  120.672 186.745 157.986 188.059 ;
     RECT  159.015 185.549 159.297 188.059 ;
     RECT  120.672 188.059 159.297 188.107 ;
     RECT  94.14 187.889 97.686 188.249 ;
     RECT  90.648 187.979 90.666 188.393 ;
     RECT  94.14 188.249 94.734 188.393 ;
     RECT  98.496 188.059 113.058 188.519 ;
     RECT  114.156 188.401 114.174 188.519 ;
     RECT  120.456 188.107 159.297 188.519 ;
     RECT  94.14 188.393 94.662 188.527 ;
     RECT  112.86 188.519 113.058 188.635 ;
     RECT  120.456 188.519 120.474 188.663 ;
     RECT  1.728 187.819 3.006 188.671 ;
     RECT  95.508 188.249 97.686 188.671 ;
     RECT  98.496 188.519 100.602 188.671 ;
     RECT  92.916 188.023 93.258 188.869 ;
     RECT  94.032 188.527 94.662 188.869 ;
     RECT  1.728 188.671 3.33 188.933 ;
     RECT  112.86 188.635 113.094 188.941 ;
     RECT  92.916 188.869 94.662 189.101 ;
     RECT  92.916 189.101 92.934 189.131 ;
     RECT  101.34 188.519 111.906 189.131 ;
     RECT  118.584 188.329 118.602 189.167 ;
     RECT  94.032 189.101 94.662 189.211 ;
     RECT  95.508 188.671 100.602 189.211 ;
     RECT  90.648 189.373 90.666 189.473 ;
     RECT  110.124 189.131 111.906 189.607 ;
     RECT  112.86 188.941 113.202 189.607 ;
     RECT  110.124 189.607 112.086 189.869 ;
     RECT  112.86 189.607 113.526 189.905 ;
     RECT  111.78 189.869 112.086 189.949 ;
     RECT  112.86 189.905 113.49 189.949 ;
     RECT  101.34 189.131 109.386 190.021 ;
     RECT  118.584 189.985 118.602 190.139 ;
     RECT  247.068 184.469 247.086 190.139 ;
     RECT  4.176 188.107 4.194 190.175 ;
     RECT  111.78 189.949 113.49 190.211 ;
     RECT  94.032 189.211 100.602 190.291 ;
     RECT  101.34 190.021 109.422 190.291 ;
     RECT  94.032 190.291 109.422 190.319 ;
     RECT  4.392 190.291 4.41 190.517 ;
     RECT  121.215 188.519 159.297 190.723 ;
     RECT  121.212 190.723 159.297 190.747 ;
     RECT  1.728 188.933 2.898 190.831 ;
     RECT  94.176 190.319 109.422 190.831 ;
     RECT  110.415 189.869 110.826 190.831 ;
     RECT  111.78 190.211 113.238 190.831 ;
     RECT  121.212 190.747 159.858 190.949 ;
     RECT  244.656 190.561 244.674 190.949 ;
     RECT  94.176 190.831 113.238 191.029 ;
     RECT  118.584 190.957 118.602 191.029 ;
     RECT  118.584 191.029 118.674 191.057 ;
     RECT  118.656 191.057 118.674 191.065 ;
     RECT  94.176 191.029 113.274 191.101 ;
     RECT  118.656 191.065 118.782 191.129 ;
     RECT  121.212 190.949 159.606 191.263 ;
     RECT  94.176 191.101 113.706 191.291 ;
     RECT  118.764 191.129 118.782 191.363 ;
     RECT  94.176 191.291 108.738 191.467 ;
     RECT  120.888 191.263 159.606 191.489 ;
     RECT  93.24 191.335 93.258 191.501 ;
     RECT  1.728 190.831 3.006 191.525 ;
     RECT  121.032 191.489 159.297 191.525 ;
     RECT  121.032 191.525 127.89 191.633 ;
     RECT  92.916 191.641 92.934 191.759 ;
     RECT  94.068 191.467 108.738 191.759 ;
     RECT  109.476 191.291 113.706 191.759 ;
     RECT  0.108 188.203 0.126 191.795 ;
     RECT  109.584 191.759 113.418 191.795 ;
     RECT  2.415 191.525 3.006 191.911 ;
     RECT  109.656 191.795 113.418 192.029 ;
     RECT  109.692 192.029 113.418 192.101 ;
     RECT  121.068 191.633 127.89 192.137 ;
     RECT  109.908 192.101 113.346 192.209 ;
     RECT  2.415 191.911 3.222 192.299 ;
     RECT  95.616 191.759 108.738 192.299 ;
     RECT  109.908 192.209 113.274 192.299 ;
     RECT  94.068 191.759 94.554 192.335 ;
     RECT  95.616 192.299 95.634 192.335 ;
     RECT  110.415 192.299 112.446 192.371 ;
     RECT  96.372 192.299 108.738 192.379 ;
     RECT  121.215 192.137 127.89 192.415 ;
     RECT  128.628 191.525 159.297 192.415 ;
     RECT  110.415 192.371 112.374 192.569 ;
     RECT  113.256 192.299 113.274 192.569 ;
     RECT  110.415 192.569 111.762 192.605 ;
     RECT  111.492 192.605 111.762 192.641 ;
     RECT  111.744 192.641 111.762 192.713 ;
     RECT  96.372 192.379 108.81 193.145 ;
     RECT  96.372 193.145 107.19 193.261 ;
     RECT  96.336 193.261 107.19 193.531 ;
     RECT  121.215 192.415 159.297 193.621 ;
     RECT  96.264 193.531 107.19 193.649 ;
     RECT  96.336 193.649 107.19 193.963 ;
     RECT  108.144 193.145 108.81 193.963 ;
     RECT  96.336 193.963 107.334 194.035 ;
     RECT  108.108 193.963 108.81 194.035 ;
     RECT  96.336 194.035 108.81 194.071 ;
     RECT  96.336 194.071 109.134 194.189 ;
     RECT  96.336 194.189 108.81 194.261 ;
     RECT  97.308 194.261 108.81 194.729 ;
     RECT  96.336 194.261 96.534 195.007 ;
     RECT  97.308 194.729 100.962 195.007 ;
     RECT  101.772 194.729 108.81 195.269 ;
     RECT  101.772 195.269 108.63 195.305 ;
     RECT  101.772 195.305 108.594 195.413 ;
     RECT  96.336 195.007 100.962 195.547 ;
     RECT  101.772 195.413 108.414 195.547 ;
     RECT  121.215 193.621 159.354 195.883 ;
     RECT  114.588 195.787 114.606 195.917 ;
     RECT  121.176 195.883 159.354 195.961 ;
     RECT  121.176 195.961 159.642 196.079 ;
     RECT  119.628 195.931 119.646 196.355 ;
     RECT  96.336 195.547 108.414 196.655 ;
     RECT  96.588 196.655 108.414 197.159 ;
     RECT  96.588 197.159 108.27 197.231 ;
     RECT  96.588 197.231 108.126 197.969 ;
     RECT  121.215 196.079 159.642 197.969 ;
     RECT  96.588 197.969 96.75 198.239 ;
     RECT  96.588 198.239 96.606 198.275 ;
     RECT  97.596 197.969 108.126 198.275 ;
     RECT  121.215 197.969 151.902 198.751 ;
     RECT  152.748 197.969 159.642 198.751 ;
     RECT  97.668 198.275 108.126 198.779 ;
     RECT  97.668 198.779 107.802 198.851 ;
     RECT  121.215 198.751 159.642 199.121 ;
     RECT  123.696 199.121 159.642 199.201 ;
     RECT  97.884 198.851 107.802 199.373 ;
     RECT  123.696 199.201 159.678 199.435 ;
     RECT  98.064 199.373 107.802 199.705 ;
     RECT  98.064 199.705 108.234 199.895 ;
     RECT  98.568 199.895 108.234 199.931 ;
     RECT  121.215 199.121 122.958 199.975 ;
     RECT  123.696 199.435 159.75 199.975 ;
     RECT  98.64 199.931 108.234 200.039 ;
     RECT  102.528 200.039 103.194 200.093 ;
     RECT  98.64 200.039 98.658 200.129 ;
     RECT  99.432 200.039 101.718 200.129 ;
     RECT  102.996 200.093 103.194 200.129 ;
     RECT  103.932 200.039 108.234 200.129 ;
     RECT  106.596 200.129 107.298 200.141 ;
     RECT  102.996 200.129 103.014 200.165 ;
     RECT  103.932 200.129 105.678 200.165 ;
     RECT  106.74 200.141 107.298 200.165 ;
     RECT  106.776 200.165 106.866 200.201 ;
     RECT  106.776 200.201 106.794 200.237 ;
     RECT  99.504 200.129 99.897 200.273 ;
     RECT  100.98 200.129 100.998 200.273 ;
     RECT  103.932 200.165 105.297 200.399 ;
     RECT  103.932 200.399 103.95 200.435 ;
     RECT  121.215 199.975 159.75 200.443 ;
     RECT  121.215 200.443 159.822 200.821 ;
     RECT  121.215 200.821 159.93 202.127 ;
     RECT  121.215 202.127 130.554 202.667 ;
     RECT  122.292 202.667 130.554 202.829 ;
     RECT  122.544 202.829 130.554 202.873 ;
     RECT  131.328 202.127 159.93 202.873 ;
     RECT  121.215 202.667 121.497 203.791 ;
     RECT  122.544 202.873 159.93 203.791 ;
     RECT  121.215 203.791 159.93 203.909 ;
     RECT  122.508 203.909 159.93 203.945 ;
     RECT  121.215 203.909 121.77 204.077 ;
     RECT  156.888 203.945 159.93 204.215 ;
     RECT  122.508 203.945 156.114 204.323 ;
     RECT  122.544 204.323 156.114 204.485 ;
     RECT  122.796 204.485 156.114 204.605 ;
     RECT  123.048 204.605 156.114 204.715 ;
     RECT  123.048 204.715 156.258 205.033 ;
     RECT  157.032 204.215 159.93 205.033 ;
     RECT  123.048 205.033 159.93 205.375 ;
     RECT  122.832 205.375 159.93 205.531 ;
     RECT  122.724 205.531 159.93 205.799 ;
     RECT  122.724 205.799 123.822 206.077 ;
     RECT  121.215 204.077 121.497 206.149 ;
     RECT  121.215 206.149 121.806 206.189 ;
     RECT  122.544 206.077 123.822 206.221 ;
     RECT  122.4 206.221 123.822 206.483 ;
     RECT  124.596 205.799 159.93 206.525 ;
     RECT  124.596 206.525 156.042 206.645 ;
     RECT  122.724 206.483 123.822 206.653 ;
     RECT  124.596 206.645 155.97 206.653 ;
     RECT  122.724 206.653 155.97 206.879 ;
     RECT  124.452 206.879 155.97 207.023 ;
     RECT  122.724 206.879 123.678 207.059 ;
     RECT  122.724 207.059 123.57 207.301 ;
     RECT  124.488 207.023 155.97 207.491 ;
     RECT  121.215 206.189 121.497 207.499 ;
     RECT  122.472 207.301 123.57 207.499 ;
     RECT  125.028 207.491 155.97 207.499 ;
     RECT  156.816 206.525 159.93 207.499 ;
     RECT  121.215 207.499 123.57 207.689 ;
     RECT  125.028 207.499 159.93 207.689 ;
     RECT  125.028 207.689 155.97 207.959 ;
     RECT  122.364 207.689 123.57 208.381 ;
     RECT  156.708 207.689 159.93 208.571 ;
     RECT  121.215 207.689 121.497 208.579 ;
     RECT  122.364 208.381 124.182 208.579 ;
     RECT  121.215 208.579 124.182 208.651 ;
     RECT  125.028 207.959 155.898 208.651 ;
     RECT  156.708 208.571 159.642 208.913 ;
     RECT  121.215 208.651 155.898 208.921 ;
     RECT  156.708 208.913 159.57 208.921 ;
     RECT  121.215 208.921 159.57 209.489 ;
     RECT  121.215 209.489 122.094 209.885 ;
     RECT  122.904 209.489 159.57 209.885 ;
     RECT  123.12 209.885 159.57 209.993 ;
     RECT  123.12 209.993 159.462 210.029 ;
     RECT  123.624 210.029 123.642 210.155 ;
     RECT  124.56 210.029 159.462 211.081 ;
     RECT  124.56 211.081 159.498 211.243 ;
     RECT  124.488 211.243 159.498 211.28 ;
     RECT  124.56 211.28 159.498 211.379 ;
     RECT  124.56 211.379 159.297 213.125 ;
     RECT  124.884 213.125 159.297 213.149 ;
     RECT  125.028 213.149 159.297 214.051 ;
     RECT  124.884 214.051 159.297 214.583 ;
     RECT  151.236 214.583 159.297 214.591 ;
     RECT  124.884 214.583 150.354 215.357 ;
     RECT  124.92 215.357 150.354 215.491 ;
     RECT  151.236 214.591 159.354 215.491 ;
     RECT  124.92 215.491 159.354 215.789 ;
     RECT  124.92 215.789 125.118 215.825 ;
     RECT  125.1 215.825 125.118 215.837 ;
     RECT  125.856 215.789 159.354 216.095 ;
     RECT  126.072 216.095 159.354 216.211 ;
     RECT  126.072 216.211 159.39 216.671 ;
     RECT  126.072 216.671 159.354 217.049 ;
     RECT  126.072 217.049 150.066 217.409 ;
     RECT  150.804 217.049 159.354 217.561 ;
     RECT  126.108 217.409 150.066 218.011 ;
     RECT  150.804 217.561 159.39 218.011 ;
     RECT  126.108 218.011 159.39 218.021 ;
     RECT  126.108 218.021 159.354 218.875 ;
     RECT  126.072 218.875 159.354 218.911 ;
     RECT  126.072 218.911 159.39 219.065 ;
     RECT  126.072 219.065 151.002 219.073 ;
     RECT  151.884 219.065 159.39 219.101 ;
     RECT  126 219.073 151.002 219.145 ;
     RECT  125.964 219.145 151.002 219.415 ;
     RECT  151.884 219.101 159.354 219.569 ;
     RECT  125.748 219.415 151.002 219.835 ;
     RECT  151.884 219.569 152.478 219.835 ;
     RECT  153.216 219.569 159.354 219.991 ;
     RECT  125.748 219.835 152.478 220.027 ;
     RECT  125.568 220.027 152.478 220.253 ;
     RECT  153.216 219.991 159.498 220.289 ;
     RECT  125.568 220.253 151.182 220.451 ;
     RECT  126.288 220.451 151.182 220.523 ;
     RECT  153.216 220.289 159.426 220.559 ;
     RECT  154.872 220.559 159.426 220.721 ;
     RECT  151.956 220.253 152.478 220.729 ;
     RECT  153.216 220.559 154.134 220.729 ;
     RECT  126.504 220.523 151.182 221.179 ;
     RECT  151.956 220.729 154.134 221.179 ;
     RECT  126.504 221.179 154.134 221.225 ;
     RECT  126.615 221.225 154.134 221.305 ;
     RECT  154.872 220.721 159.297 221.305 ;
     RECT  126.615 221.305 159.297 221.729 ;
     RECT  126.615 221.729 157.41 221.837 ;
     RECT  126.615 221.837 157.374 222.107 ;
     RECT  158.22 221.729 159.297 222.143 ;
     RECT  158.22 222.143 158.238 222.269 ;
     RECT  126.615 222.107 157.302 222.845 ;
     RECT  151.02 222.845 157.302 222.853 ;
     RECT  151.02 222.853 157.338 223.079 ;
     RECT  151.02 223.079 157.158 223.349 ;
     RECT  151.02 223.349 157.014 223.385 ;
     RECT  126.615 222.845 150.246 223.627 ;
     RECT  151.02 223.385 156.762 223.627 ;
     RECT  126.615 223.627 156.762 223.889 ;
     RECT  127.944 223.889 156.762 224.429 ;
     RECT  127.944 224.429 156.726 224.501 ;
     RECT  126.615 223.889 127.206 224.707 ;
     RECT  127.944 224.501 156.69 224.707 ;
     RECT  126.615 224.707 156.69 225.625 ;
     RECT  126.615 225.625 156.762 225.787 ;
     RECT  126.615 225.787 157.158 225.895 ;
     RECT  126.615 225.895 157.194 226.471 ;
     RECT  126.615 226.471 157.266 226.733 ;
     RECT  126.615 226.733 156.978 227.129 ;
     RECT  126.615 227.129 156.726 227.309 ;
     RECT  126.615 227.309 156.474 227.399 ;
     RECT  126.615 227.399 156.402 227.669 ;
     RECT  126.615 227.669 156.042 227.813 ;
     RECT  126.615 227.813 155.898 227.939 ;
     RECT  126.615 227.939 155.79 228.479 ;
     RECT  126.615 228.479 155.178 228.785 ;
     RECT  127.656 228.785 155.178 229.127 ;
     RECT  128.268 229.127 155.178 229.325 ;
     RECT  128.52 229.325 155.178 230.243 ;
     RECT  128.52 230.243 154.35 230.521 ;
     RECT  128.16 230.521 154.35 230.755 ;
     RECT  128.016 230.755 154.35 230.861 ;
     RECT  155.16 230.243 155.178 230.909 ;
     RECT  128.52 230.861 154.35 231.179 ;
     RECT  130.752 231.179 154.35 231.215 ;
     RECT  130.752 231.215 154.278 231.323 ;
     RECT  128.52 231.179 130.014 231.449 ;
     RECT  128.628 231.449 130.014 231.979 ;
     RECT  130.932 231.323 154.278 232.061 ;
     RECT  128.628 231.979 130.122 232.105 ;
     RECT  130.932 232.061 151.902 232.105 ;
     RECT  128.628 232.105 151.902 232.375 ;
     RECT  128.34 232.375 151.902 232.445 ;
     RECT  152.64 232.061 154.278 232.529 ;
     RECT  152.64 232.529 153.99 232.565 ;
     RECT  128.628 232.445 151.902 232.601 ;
     RECT  141.552 232.601 151.902 232.835 ;
     RECT  150.228 232.835 151.902 232.951 ;
     RECT  152.64 232.565 153.897 232.951 ;
     RECT  128.628 232.601 140.814 233.491 ;
     RECT  141.552 232.835 149.31 233.491 ;
     RECT  128.628 233.491 149.31 233.581 ;
     RECT  150.228 232.951 153.897 233.581 ;
     RECT  128.628 233.581 153.897 233.609 ;
     RECT  151.38 233.609 153.897 233.681 ;
     RECT  128.628 233.609 150.462 233.879 ;
     RECT  128.628 233.879 128.682 234.029 ;
     RECT  151.38 233.681 152.622 234.149 ;
     RECT  153.54 233.681 153.897 234.419 ;
     RECT  129.456 233.879 150.462 234.427 ;
     RECT  151.884 234.149 152.622 234.535 ;
     RECT  151.884 234.535 152.73 234.689 ;
     RECT  129.456 234.427 151.11 234.725 ;
     RECT  151.992 234.689 152.73 234.725 ;
     RECT  129.456 234.725 150.786 234.749 ;
     RECT  151.992 234.725 152.514 234.749 ;
     RECT  129.456 234.749 149.454 234.761 ;
     RECT  150.768 234.749 150.786 234.761 ;
     RECT  129.456 234.761 148.77 234.841 ;
     RECT  128.628 234.029 128.646 234.859 ;
     RECT  129.384 234.841 148.77 234.859 ;
     RECT  128.628 234.859 148.77 235.229 ;
     RECT  128.628 235.229 129.906 235.265 ;
     RECT  129.384 235.265 129.906 235.409 ;
     RECT  130.896 235.229 148.77 235.409 ;
     RECT  150.444 235.579 150.462 235.679 ;
     RECT  152.496 234.749 152.514 235.679 ;
     RECT  131.328 235.409 148.77 236.039 ;
     RECT  131.328 236.039 148.497 237.271 ;
     RECT  131.328 237.271 148.734 237.389 ;
     RECT  131.328 237.389 148.497 240.781 ;
     RECT  131.328 240.781 148.698 241.007 ;
     RECT  131.328 241.007 148.497 241.861 ;
     RECT  131.328 241.861 148.518 241.979 ;
     RECT  131.328 241.979 148.497 242.123 ;
     RECT  131.328 242.123 147.078 242.393 ;
     RECT  147.06 242.393 147.078 242.429 ;
     RECT  131.328 242.393 146.142 243.211 ;
     RECT  131.328 243.211 146.322 243.329 ;
     RECT  131.328 243.329 145.854 243.401 ;
     RECT  133.668 243.401 145.854 243.635 ;
     RECT  134.136 243.635 138.942 243.905 ;
     RECT  135.18 243.905 138.942 244.687 ;
     RECT  139.932 243.635 145.818 244.687 ;
     RECT  134.136 243.905 134.334 244.831 ;
     RECT  135.18 244.687 145.818 244.831 ;
     RECT  134.136 244.831 145.818 244.949 ;
     RECT  135.072 244.949 145.818 245.101 ;
     RECT  135.072 245.101 145.89 245.669 ;
     RECT  131.328 243.401 132.297 245.731 ;
     RECT  128.628 235.265 128.646 245.759 ;
     RECT  135.072 245.669 144.846 245.903 ;
     RECT  134.136 244.949 134.334 245.911 ;
     RECT  135.36 245.903 144.846 246.065 ;
     RECT  134.136 245.911 134.514 246.137 ;
     RECT  135.684 246.065 144.846 246.209 ;
     RECT  131.112 245.731 132.297 246.407 ;
     RECT  131.328 246.407 132.297 246.415 ;
     RECT  131.328 246.415 132.39 246.461 ;
     RECT  141.408 246.209 144.846 246.568 ;
     RECT  141.408 246.568 144.882 246.721 ;
     RECT  141.408 246.721 145.026 246.839 ;
     RECT  141.408 246.839 143.298 246.911 ;
     RECT  145.872 245.669 145.89 246.919 ;
     RECT  135.684 246.209 140.526 246.955 ;
     RECT  135.684 246.955 140.562 246.991 ;
     RECT  141.408 246.911 143.097 246.991 ;
     RECT  145.62 246.919 145.89 246.991 ;
     RECT  135.684 246.991 143.097 247.081 ;
     RECT  135.108 247.081 143.097 247.109 ;
     RECT  145.62 246.991 146.142 247.109 ;
     RECT  135.108 247.109 138.726 247.181 ;
     RECT  139.5 247.109 143.097 247.181 ;
     RECT  145.656 247.109 146.142 247.289 ;
     RECT  135.108 247.181 138.69 247.373 ;
     RECT  135.828 247.373 138.69 247.379 ;
     RECT  135.828 247.379 138.582 247.415 ;
     RECT  136.116 247.415 138.582 247.451 ;
     RECT  136.116 247.451 138.546 247.487 ;
     RECT  136.116 247.487 136.134 247.523 ;
     RECT  136.908 247.487 138.546 247.523 ;
     RECT  139.572 247.181 143.097 247.657 ;
     RECT  144.036 246.839 144.882 247.657 ;
     RECT  139.572 247.657 144.882 248.071 ;
     RECT  145.656 247.289 145.89 248.071 ;
     RECT  137.415 247.523 138.546 248.305 ;
     RECT  139.572 248.071 145.89 248.305 ;
     RECT  137.415 248.305 145.89 248.341 ;
     RECT  137.415 248.341 146.142 248.881 ;
     RECT  137.415 248.881 146.43 248.999 ;
     RECT  137.415 248.999 145.926 249.269 ;
     RECT  137.415 249.269 141.75 249.305 ;
     RECT  142.56 249.269 145.89 249.341 ;
     RECT  142.56 249.341 145.746 249.413 ;
     RECT  138.456 249.305 141.75 249.539 ;
     RECT  142.632 249.413 145.746 249.647 ;
     RECT  139.248 249.539 139.266 249.683 ;
     RECT  142.632 249.647 145.458 250.159 ;
     RECT  140.004 249.539 141.75 250.465 ;
     RECT  142.524 250.159 145.458 250.465 ;
     RECT  140.004 250.465 145.458 250.799 ;
     RECT  144.144 250.799 145.458 251.041 ;
     RECT  144.144 251.041 145.782 251.159 ;
     RECT  144.144 251.159 145.458 251.261 ;
     RECT  140.004 250.799 143.262 251.275 ;
     RECT  139.788 251.275 143.262 251.429 ;
     RECT  144.144 251.261 145.278 251.429 ;
     RECT  144.144 251.429 145.026 251.465 ;
     RECT  144.144 251.465 144.918 251.537 ;
     RECT  140.184 251.429 143.262 251.545 ;
     RECT  144.144 251.537 144.198 251.545 ;
     RECT  140.184 251.545 144.198 251.699 ;
     RECT  140.184 251.699 143.19 251.735 ;
     RECT  140.94 251.735 143.19 251.771 ;
     RECT  144 251.699 144.162 251.807 ;
     RECT  144 251.807 144.018 251.843 ;
     RECT  140.94 251.771 143.097 251.879 ;
     RECT  140.184 251.735 140.202 252.125 ;
     RECT  141.012 251.879 143.097 252.125 ;
     RECT  141.624 252.125 143.097 252.149 ;
     RECT  141.768 252.149 143.097 252.275 ;
     RECT  141.984 252.275 143.097 252.311 ;
     RECT  142.56 252.311 143.097 252.347 ;
     RECT  142.776 252.347 143.097 252.383 ;
     RECT  134.136 246.137 134.154 256.361 ;
     RECT  126.615 228.785 126.897 277.675 ;
     RECT  128.916 277.663 128.934 277.709 ;
     RECT  126.615 277.675 126.99 277.805 ;
     RECT  129.24 277.771 129.258 277.808 ;
     RECT  131.328 246.461 132.297 290.849 ;
     RECT  132.015 290.849 132.297 291.001 ;
     RECT  2.415 192.299 2.697 369.107 ;
     RECT  7.815 2.413 8.097 369.107 ;
     RECT  13.215 2.413 13.497 369.107 ;
     RECT  18.615 2.413 18.897 369.107 ;
     RECT  24.015 2.413 24.297 369.107 ;
     RECT  29.415 2.413 29.697 369.107 ;
     RECT  34.815 2.413 35.097 369.107 ;
     RECT  40.215 2.413 40.497 369.107 ;
     RECT  45.615 2.413 45.897 369.107 ;
     RECT  51.015 2.413 51.297 369.107 ;
     RECT  56.415 2.413 56.697 369.107 ;
     RECT  61.815 2.413 62.097 369.107 ;
     RECT  67.215 2.413 67.497 369.107 ;
     RECT  72.615 2.413 72.897 369.107 ;
     RECT  78.015 2.413 78.297 369.107 ;
     RECT  83.415 2.413 83.697 369.107 ;
     RECT  88.815 169.079 89.097 369.107 ;
     RECT  94.215 192.335 94.497 369.107 ;
     RECT  99.615 200.273 99.897 369.107 ;
     RECT  105.015 200.399 105.297 369.107 ;
     RECT  110.415 192.605 110.697 369.107 ;
     RECT  115.815 167.021 116.097 369.107 ;
     RECT  121.215 209.885 121.497 369.107 ;
     RECT  126.615 277.805 126.897 369.107 ;
     RECT  137.415 249.305 137.697 369.107 ;
     RECT  142.815 252.383 143.097 369.107 ;
     RECT  148.215 242.123 148.497 369.107 ;
     RECT  153.615 234.419 153.897 369.107 ;
     RECT  159.015 222.143 159.297 369.107 ;
     RECT  164.415 186.368 164.697 369.107 ;
     RECT  169.815 2.413 170.097 369.107 ;
     RECT  175.215 186.368 175.497 369.107 ;
     RECT  180.615 2.413 180.897 369.107 ;
     RECT  186.015 186.368 186.297 369.107 ;
     RECT  191.415 2.413 191.697 369.107 ;
     RECT  196.815 186.368 197.097 369.107 ;
     RECT  202.215 2.413 202.497 369.107 ;
     RECT  207.615 186.368 207.897 369.107 ;
     RECT  213.015 2.413 213.297 369.107 ;
     RECT  218.415 186.368 218.697 369.107 ;
     RECT  223.815 2.413 224.097 369.107 ;
     RECT  229.215 186.368 229.497 369.107 ;
     RECT  234.615 2.413 234.897 369.107 ;
     RECT  240.015 186.368 240.297 369.107 ;
     RECT  245.415 186.359 245.697 369.107 ;
     RECT  2.415 369.107 2.505 369.377 ;
     RECT  7.815 369.107 7.905 369.377 ;
     RECT  13.215 369.107 13.305 369.377 ;
     RECT  18.615 369.107 18.705 369.377 ;
     RECT  24.015 369.107 24.105 369.377 ;
     RECT  29.415 369.107 29.505 369.377 ;
     RECT  34.815 369.107 34.905 369.377 ;
     RECT  40.215 369.107 40.305 369.377 ;
     RECT  45.615 369.107 45.705 369.377 ;
     RECT  51.015 369.107 51.105 369.377 ;
     RECT  56.415 369.107 56.505 369.377 ;
     RECT  61.815 369.107 61.905 369.377 ;
     RECT  67.215 369.107 67.305 369.377 ;
     RECT  72.615 369.107 72.705 369.377 ;
     RECT  78.015 369.107 78.105 369.377 ;
     RECT  83.415 369.107 83.505 369.377 ;
     RECT  88.815 369.107 88.905 369.377 ;
     RECT  94.215 369.107 94.305 369.377 ;
     RECT  99.615 369.107 99.705 369.377 ;
     RECT  105.015 369.107 105.105 369.377 ;
     RECT  110.415 369.107 110.505 369.377 ;
     RECT  115.815 369.107 115.905 369.377 ;
     RECT  121.215 369.107 121.305 369.377 ;
     RECT  126.615 369.107 126.705 369.377 ;
     RECT  132.015 291.001 132.39 369.377 ;
     RECT  137.415 369.107 137.505 369.377 ;
     RECT  142.815 369.107 142.905 369.377 ;
     RECT  148.215 369.107 148.305 369.377 ;
     RECT  153.615 369.107 153.705 369.377 ;
     RECT  159.015 369.107 159.105 369.377 ;
     RECT  164.415 369.107 164.505 369.377 ;
     RECT  169.815 369.107 169.905 369.377 ;
     RECT  175.215 369.107 175.305 369.377 ;
     RECT  180.615 369.107 180.705 369.377 ;
     RECT  186.015 369.107 186.105 369.377 ;
     RECT  191.415 369.107 191.505 369.377 ;
     RECT  196.815 369.107 196.905 369.377 ;
     RECT  202.215 369.107 202.305 369.377 ;
     RECT  207.615 369.107 207.705 369.377 ;
     RECT  213.015 369.107 213.105 369.377 ;
     RECT  218.415 369.107 218.505 369.377 ;
     RECT  223.815 369.107 223.905 369.377 ;
     RECT  229.215 369.107 229.305 369.377 ;
     RECT  234.615 369.107 234.705 369.377 ;
     RECT  240.015 369.107 240.105 369.377 ;
     RECT  245.415 369.107 245.505 369.377 ;
     RECT  132.156 369.377 132.39 371.213 ;
     RECT  132.156 371.213 132.174 371.405 ;
    LAYER M4 ;
     RECT  0.025 163.536 0.06 163.56 ;
     RECT  0.06 162.96 0.137 163.56 ;
     RECT  0.137 162.96 0.173 163.368 ;
     RECT  0.173 163.152 0.245 163.368 ;
     RECT  0.245 163.344 2.408 163.368 ;
     RECT  0.06 185.712 2.408 188.712 ;
     RECT  2.408 2.148 2.512 369.372 ;
     RECT  2.512 2.418 2.704 369.102 ;
     RECT  2.704 187.44 2.801 188.328 ;
     RECT  2.801 188.112 2.873 188.328 ;
     RECT  2.873 188.112 4.205 188.136 ;
     RECT  7.808 2.148 7.912 369.372 ;
     RECT  7.912 2.418 8.104 369.102 ;
     RECT  13.208 2.148 13.312 369.372 ;
     RECT  13.312 2.418 13.504 369.102 ;
     RECT  18.608 2.148 18.712 369.372 ;
     RECT  18.712 2.418 18.904 369.102 ;
     RECT  24.008 2.148 24.112 369.372 ;
     RECT  24.112 2.418 24.304 369.102 ;
     RECT  29.408 2.148 29.512 369.372 ;
     RECT  29.512 2.418 29.704 369.102 ;
     RECT  34.808 2.148 34.912 369.372 ;
     RECT  34.912 2.418 35.104 369.102 ;
     RECT  40.208 2.148 40.312 369.372 ;
     RECT  40.312 2.418 40.504 369.102 ;
     RECT  45.608 2.148 45.712 369.372 ;
     RECT  45.712 2.418 45.904 369.102 ;
     RECT  51.008 2.148 51.112 369.372 ;
     RECT  51.112 2.418 51.304 369.102 ;
     RECT  56.408 2.148 56.512 369.372 ;
     RECT  56.512 2.418 56.704 369.102 ;
     RECT  61.808 2.148 61.912 369.372 ;
     RECT  61.912 2.418 62.104 369.102 ;
     RECT  67.208 2.148 67.312 369.372 ;
     RECT  67.312 2.418 67.504 369.102 ;
     RECT  72.608 2.148 72.712 369.372 ;
     RECT  72.712 2.418 72.904 369.102 ;
     RECT  78.008 2.148 78.112 369.372 ;
     RECT  78.112 2.418 78.304 369.102 ;
     RECT  83.408 2.148 83.512 369.372 ;
     RECT  83.512 2.418 83.704 369.102 ;
     RECT  88.808 2.148 88.912 369.372 ;
     RECT  88.912 2.418 89.104 369.102 ;
     RECT  93.085 188.544 93.553 188.568 ;
     RECT  93.229 184.32 94.021 184.344 ;
     RECT  93.553 188.544 94.049 189.096 ;
     RECT  94.021 184.08 94.208 185.304 ;
     RECT  92.185 186.912 94.208 186.936 ;
     RECT  94.049 188.544 94.208 189.288 ;
     RECT  93.229 191.472 94.208 191.496 ;
     RECT  94.208 2.148 94.312 369.372 ;
     RECT  94.312 2.418 94.504 369.102 ;
     RECT  94.504 178.944 95.075 180.696 ;
     RECT  94.504 177.168 95.213 177.24 ;
     RECT  94.504 191.472 95.219 192.312 ;
     RECT  95.075 179.76 95.285 180.696 ;
     RECT  94.504 184.8 95.363 186.36 ;
     RECT  94.504 181.776 95.741 181.8 ;
     RECT  95.741 181.776 95.825 182.76 ;
     RECT  94.504 188.208 95.893 190.392 ;
     RECT  95.893 187.488 95.939 190.392 ;
     RECT  95.285 180.672 96.077 180.696 ;
     RECT  95.939 187.488 96.077 187.512 ;
     RECT  95.363 184.8 96.113 186.312 ;
     RECT  95.939 188.784 96.149 190.392 ;
     RECT  95.713 178.272 96.253 178.296 ;
     RECT  96.217 190.752 96.289 190.776 ;
     RECT  95.219 192.048 96.289 192.072 ;
     RECT  96.289 190.752 96.365 192.072 ;
     RECT  96.253 178.272 96.397 178.968 ;
     RECT  96.62 173.328 96.661 173.352 ;
     RECT  96.661 172.656 96.707 173.352 ;
     RECT  95.213 177.168 96.793 177.192 ;
     RECT  96.793 177.168 96.853 177.24 ;
     RECT  96.397 178.272 96.853 179.976 ;
     RECT  95.825 181.776 97.045 182.184 ;
     RECT  96.707 172.656 97.085 172.68 ;
     RECT  97.045 181.776 97.091 182.616 ;
     RECT  97.009 176.112 97.093 176.136 ;
     RECT  96.853 177.168 97.117 179.976 ;
     RECT  96.113 184.8 97.117 185.112 ;
     RECT  97.117 177.168 97.333 180.12 ;
     RECT  96.973 192.528 97.373 192.792 ;
     RECT  97.333 176.928 97.405 180.12 ;
     RECT  97.297 171.36 97.409 171.384 ;
     RECT  96.649 174.384 97.441 174.408 ;
     RECT  97.441 173.712 97.481 174.408 ;
     RECT  97.117 184.704 97.549 185.112 ;
     RECT  96.113 186.288 97.549 186.312 ;
     RECT  96.365 190.752 97.585 191.496 ;
     RECT  97.405 176.928 97.589 180.456 ;
     RECT  97.585 190.368 97.625 191.496 ;
     RECT  97.585 194.544 97.765 194.568 ;
     RECT  97.589 176.928 97.805 180.12 ;
     RECT  96.149 188.784 97.813 189.384 ;
     RECT  97.625 190.368 97.813 190.392 ;
     RECT  97.091 182.16 97.841 182.616 ;
     RECT  97.549 184.704 97.945 186.312 ;
     RECT  97.837 174.864 97.985 174.888 ;
     RECT  97.945 184.704 98.053 186.408 ;
     RECT  97.765 194.544 98.053 194.952 ;
     RECT  98.053 194.4 98.089 194.952 ;
     RECT  97.805 179.376 98.165 180.12 ;
     RECT  98.053 184.176 98.165 186.408 ;
     RECT  96.865 196.608 98.273 196.632 ;
     RECT  98.165 184.176 98.345 185.064 ;
     RECT  97.625 191.472 98.381 191.496 ;
     RECT  97.805 176.928 98.413 177.864 ;
     RECT  97.837 172.704 98.449 172.728 ;
     RECT  97.841 182.304 98.453 182.616 ;
     RECT  97.813 188.784 98.572 190.392 ;
     RECT  98.449 172.368 98.593 172.728 ;
     RECT  97.481 173.712 98.701 173.736 ;
     RECT  98.572 190.176 98.881 190.392 ;
     RECT  97.373 192.768 98.989 192.792 ;
     RECT  98.377 181.2 99.169 181.224 ;
     RECT  98.989 192.048 99.169 192.792 ;
     RECT  98.165 186.384 99.385 186.408 ;
     RECT  98.701 173.712 99.421 174.6 ;
     RECT  98.345 184.176 99.457 184.728 ;
     RECT  98.197 198.24 99.493 198.264 ;
     RECT  97.873 199.344 99.493 199.368 ;
     RECT  98.881 190.176 99.529 190.728 ;
     RECT  98.453 182.592 99.565 182.616 ;
     RECT  97.837 170.976 99.608 171 ;
     RECT  98.593 172.176 99.608 172.728 ;
     RECT  99.421 173.712 99.608 175.08 ;
     RECT  98.413 176.112 99.608 177.864 ;
     RECT  98.165 179.616 99.608 180.12 ;
     RECT  99.169 181.2 99.608 181.272 ;
     RECT  99.565 182.352 99.608 182.616 ;
     RECT  99.457 184.176 99.608 184.824 ;
     RECT  99.385 186.384 99.608 187.32 ;
     RECT  98.572 188.784 99.608 188.904 ;
     RECT  99.529 190.176 99.608 190.968 ;
     RECT  99.169 192.048 99.608 193.416 ;
     RECT  98.089 194.4 99.608 195.096 ;
     RECT  99.432 196.464 99.608 196.488 ;
     RECT  99.493 197.712 99.608 199.368 ;
     RECT  99.608 2.148 99.712 369.372 ;
     RECT  99.712 2.418 99.904 369.102 ;
     RECT  99.904 176.928 99.965 177.864 ;
     RECT  99.904 179.664 100.001 184.488 ;
     RECT  99.904 171.552 100.019 173.976 ;
     RECT  100.001 179.664 100.019 183.24 ;
     RECT  99.904 188.784 100.019 191.496 ;
     RECT  100.019 179.664 100.06 183 ;
     RECT  99.904 194.544 100.073 196.488 ;
     RECT  100.001 184.272 100.109 184.488 ;
     RECT  99.904 193.392 100.289 193.416 ;
     RECT  100.06 182.352 100.307 183 ;
     RECT  100.019 189.072 100.307 191.496 ;
     RECT  100.06 179.664 100.361 181.272 ;
     RECT  100.307 189.072 100.361 189.768 ;
     RECT  100.361 180.144 100.397 181.272 ;
     RECT  99.904 186.912 100.541 187.32 ;
     RECT  99.965 177.552 100.721 177.864 ;
     RECT  100.307 182.352 100.757 182.904 ;
     RECT  100.019 171.552 100.793 173.736 ;
     RECT  100.397 180.144 100.937 181.224 ;
     RECT  99.904 198.96 100.969 198.984 ;
     RECT  99.904 197.712 101.009 197.736 ;
     RECT  100.721 177.84 101.041 177.864 ;
     RECT  100.793 171.936 101.081 173.736 ;
     RECT  100.073 194.928 101.123 196.488 ;
     RECT  100.969 198.768 101.149 198.984 ;
     RECT  101.081 171.936 101.164 173.448 ;
     RECT  101.041 177.84 101.189 178.44 ;
     RECT  100.307 191.472 101.221 191.496 ;
     RECT  101.149 198.384 101.233 198.984 ;
     RECT  100.757 182.592 101.365 182.904 ;
     RECT  101.233 198.768 101.365 198.984 ;
     RECT  100.969 200.064 101.365 200.088 ;
     RECT  99.904 175.056 101.369 175.08 ;
     RECT  100.541 186.912 101.401 186.936 ;
     RECT  101.365 182.592 101.473 183.48 ;
     RECT  100.109 184.464 101.473 184.488 ;
     RECT  101.221 193.104 101.729 193.128 ;
     RECT  101.189 178.416 101.833 178.44 ;
     RECT  101.123 194.928 101.833 196.344 ;
     RECT  101.401 186.336 101.861 186.936 ;
     RECT  101.365 198.768 101.909 200.088 ;
     RECT  101.861 186.336 101.941 187.56 ;
     RECT  101.941 185.952 101.945 187.56 ;
     RECT  101.945 185.952 101.98 186.936 ;
     RECT  101.473 182.592 102.083 184.488 ;
     RECT  102.083 184.464 102.193 184.488 ;
     RECT  100.937 180.96 102.229 181.224 ;
     RECT  102.083 182.592 102.229 183.48 ;
     RECT  101.221 191.472 102.265 192.072 ;
     RECT  102.193 184.464 102.301 184.728 ;
     RECT  100.361 189.072 102.301 189.096 ;
     RECT  101.833 178.416 102.341 179.4 ;
     RECT  101.833 194.544 102.341 196.344 ;
     RECT  102.341 178.656 102.373 179.4 ;
     RECT  102.229 180.96 102.373 183.48 ;
     RECT  102.341 194.544 102.481 195.96 ;
     RECT  102.337 176.448 102.517 176.568 ;
     RECT  102.481 193.776 102.611 195.96 ;
     RECT  102.611 194.544 102.629 195.96 ;
     RECT  102.629 194.544 102.652 194.712 ;
     RECT  102.265 190.656 102.697 192.072 ;
     RECT  102.625 174.432 102.737 174.456 ;
     RECT  101.164 172.848 102.809 173.448 ;
     RECT  101.909 198.768 102.877 198.792 ;
     RECT  102.373 178.656 102.881 183.48 ;
     RECT  102.877 198.288 102.881 198.792 ;
     RECT  102.301 184.464 102.949 184.824 ;
     RECT  101.98 185.952 102.949 186.792 ;
     RECT  102.809 172.848 102.985 172.872 ;
     RECT  102.949 184.464 102.989 186.792 ;
     RECT  102.301 189.072 103.097 189.624 ;
     RECT  102.697 190.608 103.129 192.072 ;
     RECT  102.652 194.544 103.133 194.568 ;
     RECT  103.129 190.608 103.237 192.12 ;
     RECT  102.517 176.448 103.273 176.76 ;
     RECT  102.881 178.656 103.277 181.08 ;
     RECT  102.881 198.288 103.349 198.312 ;
     RECT  103.097 189.072 103.385 189.432 ;
     RECT  102.913 170.976 103.477 171 ;
     RECT  102.985 172.704 103.477 172.872 ;
     RECT  102.877 174.624 103.525 174.792 ;
     RECT  103.273 176.256 103.525 176.76 ;
     RECT  103.525 174.624 103.529 176.76 ;
     RECT  103.484 169.584 103.535 169.608 ;
     RECT  103.477 170.976 103.535 172.872 ;
     RECT  103.535 169.584 103.571 172.872 ;
     RECT  103.571 170.304 103.629 172.872 ;
     RECT  103.629 170.304 103.637 171 ;
     RECT  103.237 190.608 103.637 192.36 ;
     RECT  102.629 195.792 103.777 195.96 ;
     RECT  103.561 193.536 103.781 193.56 ;
     RECT  103.777 195.6 103.877 195.96 ;
     RECT  103.529 174.624 103.889 176.52 ;
     RECT  103.277 179.28 103.916 181.08 ;
     RECT  102.989 184.464 103.925 186.504 ;
     RECT  103.916 179.28 103.957 181.128 ;
     RECT  102.881 182.592 103.957 183.48 ;
     RECT  101.909 200.064 103.961 200.088 ;
     RECT  103.385 189.072 103.993 189.096 ;
     RECT  103.957 179.28 104.108 183.48 ;
     RECT  103.925 184.464 104.108 186.456 ;
     RECT  104.108 179.28 104.425 186.456 ;
     RECT  103.877 195.264 104.461 195.96 ;
     RECT  103.889 176.256 104.533 176.52 ;
     RECT  104.353 172.896 104.783 172.92 ;
     RECT  103.637 170.304 104.785 170.328 ;
     RECT  104.785 170.304 104.821 170.424 ;
     RECT  103.637 190.608 104.857 191.592 ;
     RECT  104.137 192.672 104.857 192.696 ;
     RECT  103.993 188.112 104.965 189.096 ;
     RECT  104.857 190.608 104.965 192.696 ;
     RECT  103.525 166.656 105.008 166.68 ;
     RECT  104.821 170.304 105.008 170.856 ;
     RECT  104.783 172.896 105.008 173.448 ;
     RECT  103.889 174.624 105.008 174.792 ;
     RECT  104.533 176.256 105.008 177.24 ;
     RECT  104.425 178.416 105.008 186.456 ;
     RECT  104.965 188.112 105.008 192.696 ;
     RECT  104.461 195.264 105.008 196.92 ;
     RECT  104.029 198.24 105.008 198.264 ;
     RECT  105.008 2.148 105.112 369.372 ;
     RECT  105.112 2.418 105.304 369.102 ;
     RECT  105.304 195.264 105.401 198.408 ;
     RECT  105.304 176.112 105.473 178.392 ;
     RECT  105.473 177.216 105.491 178.392 ;
     RECT  105.304 199.44 105.539 200.136 ;
     RECT  105.401 198.24 105.58 198.408 ;
     RECT  105.304 169.92 105.761 171 ;
     RECT  105.491 177.84 105.797 178.392 ;
     RECT  105.401 195.264 105.797 196.92 ;
     RECT  105.761 170.16 106.013 171 ;
     RECT  105.304 186.384 106.019 189.912 ;
     RECT  105.304 172.896 106.049 172.92 ;
     RECT  105.304 191.184 106.085 192.696 ;
     RECT  105.304 179.664 106.369 180.6 ;
     RECT  105.304 182.592 106.369 183.528 ;
     RECT  106.369 179.616 106.477 180.6 ;
     RECT  106.369 182.592 106.477 184.44 ;
     RECT  105.797 178.368 106.508 178.392 ;
     RECT  106.477 179.616 106.508 184.44 ;
     RECT  105.473 176.112 106.585 176.136 ;
     RECT  106.019 189.072 106.585 189.912 ;
     RECT  106.085 191.184 106.585 191.496 ;
     RECT  106.508 178.368 106.595 184.44 ;
     RECT  106.019 186.384 106.597 187.848 ;
     RECT  106.597 185.472 106.643 187.848 ;
     RECT  106.585 189.072 106.643 191.496 ;
     RECT  106.643 191.472 106.684 191.496 ;
     RECT  105.304 174.768 106.733 174.792 ;
     RECT  106.643 185.472 106.733 185.832 ;
     RECT  106.585 176.112 106.837 176.712 ;
     RECT  106.013 170.976 106.883 171 ;
     RECT  105.58 198.24 106.913 198.264 ;
     RECT  106.837 175.296 106.985 178.008 ;
     RECT  105.797 195.792 107.093 196.104 ;
     RECT  106.985 175.296 107.201 177.48 ;
     RECT  106.643 186.912 107.233 187.848 ;
     RECT  107.201 176.688 107.309 177.48 ;
     RECT  106.595 179.376 107.309 180.696 ;
     RECT  105.539 200.112 107.309 200.136 ;
     RECT  107.201 175.296 107.417 175.32 ;
     RECT  106.595 181.776 107.449 184.44 ;
     RECT  107.449 181.776 107.489 184.728 ;
     RECT  106.085 192.672 107.629 192.696 ;
     RECT  107.489 181.776 107.633 183.528 ;
     RECT  107.629 192 107.633 192.696 ;
     RECT  107.233 186.912 107.669 188.088 ;
     RECT  106.643 189.072 107.729 190.392 ;
     RECT  107.309 177.456 107.777 177.48 ;
     RECT  107.729 189.072 107.795 190.44 ;
     RECT  107.795 190.416 107.813 190.44 ;
     RECT  107.309 179.376 107.849 180.6 ;
     RECT  107.849 179.664 107.921 180.6 ;
     RECT  106.733 185.808 107.921 185.832 ;
     RECT  107.633 182.112 107.957 183.528 ;
     RECT  107.669 187.488 108.101 188.088 ;
     RECT  107.921 179.664 108.353 180.504 ;
     RECT  107.197 194.208 108.425 194.232 ;
     RECT  107.957 182.592 108.569 183.384 ;
     RECT  107.795 189.072 108.677 189.192 ;
     RECT  108.673 177.312 108.803 177.336 ;
     RECT  107.489 184.704 109.037 184.728 ;
     RECT  108.101 187.488 109.037 187.8 ;
     RECT  108.353 180.48 109.169 180.504 ;
     RECT  109.169 180.48 109.189 181.272 ;
     RECT  108.569 182.592 109.189 182.616 ;
     RECT  108.757 178.512 109.213 178.536 ;
     RECT  109.189 180.48 109.235 182.616 ;
     RECT  109.213 178.512 109.397 179.208 ;
     RECT  109.037 187.68 109.621 187.8 ;
     RECT  108.677 189.072 109.621 189.096 ;
     RECT  109.717 183.84 109.861 183.864 ;
     RECT  105.304 166.656 110.408 166.68 ;
     RECT  109.397 178.512 110.408 178.824 ;
     RECT  109.235 180.48 110.408 181.8 ;
     RECT  109.861 182.88 110.408 183.864 ;
     RECT  109.82 186.336 110.408 186.36 ;
     RECT  109.621 187.68 110.408 189.096 ;
     RECT  107.633 192 110.408 192.024 ;
     RECT  107.093 195.792 110.408 195.816 ;
     RECT  110.408 2.148 110.512 369.372 ;
     RECT  110.512 2.418 110.704 369.102 ;
     RECT  110.704 190.944 110.765 191.688 ;
     RECT  110.765 190.944 110.837 191.592 ;
     RECT  110.704 188.064 111.161 189.24 ;
     RECT  110.837 190.944 111.233 191.016 ;
     RECT  111.161 189.216 111.733 189.24 ;
     RECT  111.233 190.944 111.733 190.968 ;
     RECT  111.733 189.216 111.779 190.968 ;
     RECT  111.779 190.08 111.781 190.968 ;
     RECT  111.781 190.08 111.82 190.104 ;
     RECT  111.161 188.064 111.881 188.088 ;
     RECT  110.704 181.776 112.345 181.8 ;
     RECT  110.704 195.792 114.577 195.816 ;
     RECT  114.577 195.792 114.617 195.912 ;
     RECT  110.704 166.656 115.693 166.68 ;
     RECT  115.693 166.656 115.808 167.016 ;
     RECT  112.345 181.632 115.808 181.8 ;
     RECT  114.617 195.888 115.808 195.912 ;
     RECT  115.808 2.148 115.912 369.372 ;
     RECT  115.912 2.418 116.104 369.102 ;
     RECT  116.104 166.896 116.243 167.016 ;
     RECT  116.104 181.632 116.243 182.472 ;
     RECT  116.243 181.776 116.993 182.472 ;
     RECT  116.104 195.888 119.612 195.912 ;
     RECT  119.612 195.888 119.699 196.344 ;
     RECT  120.229 185.568 120.709 185.592 ;
     RECT  116.993 181.776 121.201 181.8 ;
     RECT  116.243 166.896 121.208 166.92 ;
     RECT  116.104 171.216 121.208 171.24 ;
     RECT  121.201 181.776 121.208 182.616 ;
     RECT  120.332 184.032 121.208 184.056 ;
     RECT  120.709 185.568 121.208 186.408 ;
     RECT  120.445 188.112 121.208 188.136 ;
     RECT  119.699 195.888 121.208 195.96 ;
     RECT  121.208 2.148 121.312 369.372 ;
     RECT  121.312 2.418 121.504 369.102 ;
     RECT  121.504 208.608 122.003 209.88 ;
     RECT  121.504 177.264 122.041 178.632 ;
     RECT  121.504 180.432 122.051 184.728 ;
     RECT  121.504 176.016 122.069 176.04 ;
     RECT  122.051 180.432 122.092 183.864 ;
     RECT  122.041 177.792 122.099 178.632 ;
     RECT  121.504 206.16 122.099 207.528 ;
     RECT  122.003 209.184 122.105 209.88 ;
     RECT  121.504 189.264 122.149 189.912 ;
     RECT  121.504 187.536 122.213 188.136 ;
     RECT  121.504 199.056 122.236 199.08 ;
     RECT  122.099 206.736 122.243 207.528 ;
     RECT  121.504 191.424 122.485 192.696 ;
     RECT  122.149 189.888 122.531 189.912 ;
     RECT  121.504 162.576 122.533 162.6 ;
     RECT  122.099 178.272 122.537 178.632 ;
     RECT  122.485 190.944 122.537 192.696 ;
     RECT  122.533 161.76 122.579 162.6 ;
     RECT  122.605 202.416 122.713 202.44 ;
     RECT  121.504 166.896 122.749 166.92 ;
     RECT  122.092 180.432 122.753 183 ;
     RECT  122.753 180.432 122.785 182.616 ;
     RECT  121.504 186.336 122.785 186.36 ;
     RECT  121.504 197.232 122.785 197.784 ;
     RECT  121.504 204.048 122.785 204.072 ;
     RECT  122.713 205.536 122.785 205.56 ;
     RECT  122.533 164.304 122.879 164.328 ;
     RECT  121.504 201.168 122.893 201.192 ;
     RECT  122.713 202.368 122.893 202.44 ;
     RECT  122.879 164.304 122.933 164.76 ;
     RECT  122.893 201.168 122.933 202.44 ;
     RECT  122.105 209.76 122.933 209.88 ;
     RECT  122.749 166.512 122.963 166.92 ;
     RECT  121.504 194.928 122.965 196.056 ;
     RECT  122.785 197.232 122.969 197.88 ;
     RECT  122.213 188.112 123.077 188.136 ;
     RECT  122.965 194.352 123.113 196.056 ;
     RECT  121.504 171.216 123.145 171.24 ;
     RECT  121.504 172.608 123.289 172.632 ;
     RECT  121.504 174.192 123.289 174.504 ;
     RECT  122.933 201.744 123.289 202.44 ;
     RECT  122.969 197.232 123.301 197.256 ;
     RECT  123.001 198.24 123.301 198.264 ;
     RECT  123.289 172.608 123.329 174.504 ;
     RECT  123.301 198.24 123.329 199.032 ;
     RECT  123.113 194.928 123.349 196.056 ;
     RECT  123.301 197.088 123.349 197.256 ;
     RECT  122.785 186.048 123.397 186.36 ;
     RECT  123.349 194.928 123.437 197.256 ;
     RECT  123.437 194.928 123.545 196.008 ;
     RECT  123.505 183.648 123.596 183.672 ;
     RECT  123.397 186.048 123.644 186.696 ;
     RECT  122.243 206.736 123.647 206.952 ;
     RECT  122.785 180.288 123.653 182.616 ;
     RECT  123.329 173.52 123.683 174.504 ;
     RECT  123.596 183.648 123.683 183.72 ;
     RECT  123.644 186.048 123.683 187.608 ;
     RECT  123.145 171.216 123.685 171.576 ;
     RECT  122.537 190.944 123.685 192.072 ;
     RECT  122.785 204.048 123.685 205.56 ;
     RECT  123.647 206.736 123.685 207.048 ;
     RECT  123.437 197.232 123.689 197.256 ;
     RECT  123.685 204.048 123.689 207.048 ;
     RECT  123.685 190.944 123.725 192.648 ;
     RECT  123.689 204.048 123.725 204.072 ;
     RECT  123.689 205.536 123.725 207.048 ;
     RECT  123.683 186.336 123.731 187.608 ;
     RECT  123.725 191.088 123.731 192.648 ;
     RECT  123.685 170.88 123.757 172.152 ;
     RECT  122.893 179.232 123.757 179.256 ;
     RECT  123.653 182.352 123.761 182.616 ;
     RECT  123.289 201.744 123.769 202.968 ;
     RECT  123.725 206.304 123.769 207.048 ;
     RECT  123.769 202.896 123.865 202.968 ;
     RECT  123.685 189.264 123.869 189.288 ;
     RECT  123.865 176.688 123.877 176.712 ;
     RECT  123.653 180.288 123.941 181.272 ;
     RECT  123.545 194.928 123.941 195.912 ;
     RECT  123.877 176.688 123.949 177.48 ;
     RECT  123.949 177.456 123.964 177.48 ;
     RECT  123.865 202.896 124.108 203.496 ;
     RECT  123.793 200.016 124.261 200.04 ;
     RECT  124.045 208.752 124.261 208.776 ;
     RECT  122.933 209.76 124.261 209.784 ;
     RECT  124.261 200.016 124.307 200.664 ;
     RECT  124.261 208.032 124.307 209.784 ;
     RECT  122.933 164.736 124.337 164.76 ;
     RECT  124.307 209.28 124.348 209.784 ;
     RECT  123.731 192.624 124.373 192.648 ;
     RECT  123.941 195.696 124.373 195.912 ;
     RECT  123.757 170.304 124.409 172.152 ;
     RECT  123.757 178.944 124.513 179.256 ;
     RECT  123.941 180.288 124.513 180.456 ;
     RECT  123.769 206.88 124.517 207.048 ;
     RECT  123.731 191.088 124.625 191.544 ;
     RECT  124.307 200.64 124.625 200.664 ;
     RECT  124.621 197.52 124.657 197.544 ;
     RECT  123.973 193.728 124.729 193.752 ;
     RECT  124.513 178.944 124.733 180.456 ;
     RECT  123.769 201.744 124.733 201.768 ;
     RECT  122.963 166.896 124.789 166.92 ;
     RECT  124.789 166.896 124.801 167.304 ;
     RECT  124.765 184.752 124.801 184.776 ;
     RECT  123.731 186.336 124.801 186.696 ;
     RECT  124.009 175.584 124.837 175.608 ;
     RECT  124.373 195.888 124.873 195.912 ;
     RECT  124.657 197.232 124.873 197.544 ;
     RECT  124.789 165.264 124.876 165.288 ;
     RECT  124.844 213.12 124.885 213.144 ;
     RECT  123.761 182.544 124.909 182.616 ;
     RECT  124.885 213.12 124.931 213.72 ;
     RECT  124.348 209.76 124.949 209.784 ;
     RECT  124.801 184.752 125.021 186.696 ;
     RECT  124.108 203.472 125.021 203.496 ;
     RECT  124.307 208.032 125.057 208.056 ;
     RECT  124.873 195.888 125.093 197.544 ;
     RECT  124.729 193.728 125.125 194.52 ;
     RECT  124.517 206.88 125.129 206.904 ;
     RECT  124.801 166.416 125.165 167.304 ;
     RECT  125.125 193.2 125.165 194.52 ;
     RECT  125.084 215.808 125.171 215.832 ;
     RECT  125.165 194.4 125.201 194.52 ;
     RECT  123.683 173.52 125.324 174.216 ;
     RECT  124.837 175.248 125.324 175.608 ;
     RECT  123.683 183.648 125.341 183.672 ;
     RECT  125.021 184.752 125.341 185.592 ;
     RECT  124.409 171.216 125.365 172.152 ;
     RECT  125.324 173.52 125.365 175.608 ;
     RECT  125.365 171.216 125.411 176.136 ;
     RECT  125.341 169.68 125.449 169.704 ;
     RECT  124.931 213.696 125.449 213.72 ;
     RECT  124.733 178.944 125.453 178.968 ;
     RECT  124.837 189.6 125.453 189.624 ;
     RECT  125.411 175.68 125.516 176.136 ;
     RECT  125.516 175.68 125.557 176.712 ;
     RECT  125.377 186.96 125.557 186.984 ;
     RECT  125.411 172.992 125.561 174.6 ;
     RECT  125.125 220.032 125.597 220.056 ;
     RECT  125.557 175.68 125.603 177.288 ;
     RECT  122.579 161.76 125.701 161.784 ;
     RECT  125.093 195.888 125.701 196.056 ;
     RECT  124.733 180.096 125.773 180.456 ;
     RECT  125.773 180.096 125.797 181.368 ;
     RECT  125.093 197.232 125.917 197.544 ;
     RECT  123.329 198.912 125.917 199.032 ;
     RECT  125.341 183.648 125.989 185.592 ;
     RECT  125.557 186.96 125.989 187.512 ;
     RECT  125.917 197.232 126.061 199.032 ;
     RECT  124.909 205.2 126.097 205.224 ;
     RECT  125.449 169.44 126.133 169.704 ;
     RECT  126.133 169.44 126.169 169.752 ;
     RECT  124.625 191.088 126.205 191.352 ;
     RECT  125.989 201.216 126.349 201.24 ;
     RECT  124.477 211.248 126.385 211.272 ;
     RECT  126.061 197.232 126.421 199.08 ;
     RECT  125.665 208.512 126.449 208.536 ;
     RECT  125.411 171.216 126.457 171.816 ;
     RECT  126.449 208.512 126.469 208.632 ;
     RECT  126.169 169.44 126.493 169.944 ;
     RECT  125.797 180.096 126.493 181.512 ;
     RECT  124.909 182.544 126.493 182.664 ;
     RECT  126.277 189.36 126.493 189.384 ;
     RECT  126.205 191.088 126.493 192.024 ;
     RECT  126.133 206.976 126.529 207 ;
     RECT  126.385 210.384 126.529 211.272 ;
     RECT  126.493 169.152 126.565 169.944 ;
     RECT  126.457 171.216 126.565 171.912 ;
     RECT  125.561 173.232 126.565 174.6 ;
     RECT  126.493 189.36 126.565 192.024 ;
     RECT  125.165 193.2 126.565 193.224 ;
     RECT  126.133 158.016 126.608 158.04 ;
     RECT  125.593 159.552 126.608 159.576 ;
     RECT  126.421 160.752 126.608 160.776 ;
     RECT  125.701 161.76 126.608 162.36 ;
     RECT  125.161 164.16 126.608 164.184 ;
     RECT  125.989 165.312 126.608 165.336 ;
     RECT  125.165 167.28 126.608 167.304 ;
     RECT  126.565 169.152 126.608 174.6 ;
     RECT  125.603 175.68 126.608 176.28 ;
     RECT  125.603 177.264 126.608 177.288 ;
     RECT  126.385 178.608 126.608 178.632 ;
     RECT  126.493 180.096 126.608 182.664 ;
     RECT  125.989 183.648 126.608 187.512 ;
     RECT  126.565 189.36 126.608 193.224 ;
     RECT  125.201 194.4 126.608 194.472 ;
     RECT  125.701 195.504 126.608 196.056 ;
     RECT  126.421 197.184 126.608 199.08 ;
     RECT  125.593 200.112 126.608 200.136 ;
     RECT  126.349 201.216 126.608 201.768 ;
     RECT  126.493 204 126.608 204.024 ;
     RECT  126.097 205.2 126.608 205.32 ;
     RECT  126.529 206.592 126.608 207 ;
     RECT  126.469 208.512 126.608 209.16 ;
     RECT  126.529 210.384 126.608 211.56 ;
     RECT  125.449 213.696 126.608 214.008 ;
     RECT  126.169 215.52 126.608 215.544 ;
     RECT  126.385 217.248 126.608 217.272 ;
     RECT  126.097 218.256 126.608 218.28 ;
     RECT  126.493 220.128 126.608 220.152 ;
     RECT  125.893 277.68 126.608 277.704 ;
     RECT  126.608 2.148 126.712 369.372 ;
     RECT  126.712 2.418 126.904 369.102 ;
     RECT  126.904 202.848 126.965 205.32 ;
     RECT  126.904 277.68 127.001 277.8 ;
     RECT  126.904 166.464 127.043 184.584 ;
     RECT  126.904 185.568 127.043 187.992 ;
     RECT  126.904 189.36 127.043 191.16 ;
     RECT  126.904 225.36 127.043 227.4 ;
     RECT  127.043 185.568 127.073 186.264 ;
     RECT  127.043 180.288 127.081 184.536 ;
     RECT  127.043 187.968 127.145 187.992 ;
     RECT  126.904 216.672 127.217 220.152 ;
     RECT  127.217 216.672 127.228 220.008 ;
     RECT  127.228 216.672 127.283 218.376 ;
     RECT  126.904 165.072 127.379 165.48 ;
     RECT  127.283 216.672 127.397 217.272 ;
     RECT  127.043 166.464 127.433 179.16 ;
     RECT  126.904 211.248 127.433 211.848 ;
     RECT  127.433 166.56 127.468 179.16 ;
     RECT  126.904 192.624 127.505 192.936 ;
     RECT  126.904 194.352 127.541 197.784 ;
     RECT  127.081 183.648 127.577 184.536 ;
     RECT  126.904 213.696 127.667 215.544 ;
     RECT  127.468 166.56 127.685 173.256 ;
     RECT  126.965 202.848 127.715 205.176 ;
     RECT  127.541 194.448 127.721 197.784 ;
     RECT  126.904 163.008 127.757 163.032 ;
     RECT  127.685 168.816 127.757 173.256 ;
     RECT  127.379 165.072 127.829 165.24 ;
     RECT  126.904 158.016 127.897 158.04 ;
     RECT  127.468 174.288 127.907 179.16 ;
     RECT  126.904 221.232 127.933 222.12 ;
     RECT  126.904 160.512 127.937 161.64 ;
     RECT  127.667 213.696 127.937 214.056 ;
     RECT  127.667 215.52 127.969 215.544 ;
     RECT  127.397 216.672 127.969 216.696 ;
     RECT  127.721 194.448 127.973 197.208 ;
     RECT  127.433 211.248 127.973 211.56 ;
     RECT  127.933 221.232 127.973 222.264 ;
     RECT  127.043 225.36 128.012 225.72 ;
     RECT  127.715 204.72 128.081 205.032 ;
     RECT  128.012 225.072 128.099 225.72 ;
     RECT  127.073 186 128.113 186.264 ;
     RECT  127.829 165.168 128.117 165.24 ;
     RECT  128.041 188.688 128.125 188.712 ;
     RECT  127.937 160.656 128.189 161.64 ;
     RECT  126.904 199.056 128.204 199.512 ;
     RECT  127.757 168.816 128.225 173.016 ;
     RECT  127.907 175.632 128.252 179.16 ;
     RECT  127.043 190.272 128.257 191.16 ;
     RECT  127.043 227.376 128.257 227.4 ;
     RECT  126.904 228.576 128.257 228.6 ;
     RECT  128.204 199.056 128.291 199.656 ;
     RECT  127.973 221.232 128.293 221.256 ;
     RECT  128.293 221.184 128.294 221.256 ;
     RECT  127.081 180.288 128.297 182.664 ;
     RECT  127.973 194.448 128.297 196.056 ;
     RECT  127.969 215.52 128.297 216.696 ;
     RECT  128.257 227.376 128.297 228.6 ;
     RECT  126.904 208.464 128.329 209.16 ;
     RECT  128.252 175.632 128.339 179.256 ;
     RECT  128.252 187.824 128.339 188.52 ;
     RECT  128.257 190.128 128.341 191.208 ;
     RECT  128.189 160.752 128.369 161.64 ;
     RECT  127.973 197.184 128.369 197.208 ;
     RECT  128.291 199.056 128.369 199.512 ;
     RECT  128.297 227.376 128.405 227.976 ;
     RECT  128.339 175.632 128.441 179.16 ;
     RECT  128.005 230.832 128.485 230.856 ;
     RECT  128.485 230.304 128.509 230.856 ;
     RECT  128.341 190.128 128.531 191.448 ;
     RECT  128.509 230.208 128.54 230.856 ;
     RECT  128.113 186 128.581 186.36 ;
     RECT  126.904 206.976 128.581 207 ;
     RECT  127.907 174.288 128.585 174.456 ;
     RECT  127.283 218.352 128.588 218.376 ;
     RECT  128.225 168.816 128.621 171.48 ;
     RECT  127.937 213.696 128.653 213.96 ;
     RECT  128.588 217.92 128.675 218.376 ;
     RECT  128.297 180.288 128.693 180.6 ;
     RECT  128.245 200.64 128.693 200.664 ;
     RECT  126.904 223.968 128.725 223.992 ;
     RECT  128.117 165.216 128.765 165.24 ;
     RECT  128.675 218.304 128.797 218.376 ;
     RECT  127.228 219.984 128.797 220.008 ;
     RECT  127.685 166.56 128.821 167.592 ;
     RECT  128.329 232.416 128.821 232.44 ;
     RECT  128.653 234 128.821 234.024 ;
     RECT  127.505 192.816 128.833 192.936 ;
     RECT  128.725 223.488 128.837 223.992 ;
     RECT  128.821 234 128.867 234.888 ;
     RECT  128.225 172.608 128.869 173.016 ;
     RECT  127.001 277.776 128.905 277.8 ;
     RECT  128.581 186 128.909 186.552 ;
     RECT  128.081 205.008 128.909 205.032 ;
     RECT  127.973 222.24 128.909 222.264 ;
     RECT  128.867 234.864 128.945 234.888 ;
     RECT  127.897 158.016 129.013 158.52 ;
     RECT  128.369 199.056 129.013 199.08 ;
     RECT  128.837 223.968 129.049 223.992 ;
     RECT  128.329 208.464 129.053 209.448 ;
     RECT  128.297 216.192 129.053 216.696 ;
     RECT  128.797 218.304 129.089 220.008 ;
     RECT  129.089 219.984 129.116 220.008 ;
     RECT  128.294 221.184 129.116 221.208 ;
     RECT  128.005 155.28 129.121 155.304 ;
     RECT  128.297 195.072 129.121 196.056 ;
     RECT  128.621 169.152 129.155 171.48 ;
     RECT  129.121 155.28 129.161 155.592 ;
     RECT  128.821 232.416 129.161 232.968 ;
     RECT  128.821 166.56 129.197 168.12 ;
     RECT  128.405 227.712 129.203 227.976 ;
     RECT  129.197 166.56 129.205 167.448 ;
     RECT  129.205 166.416 129.251 167.448 ;
     RECT  127.973 211.248 129.253 211.272 ;
     RECT  128.833 192.816 129.265 193.032 ;
     RECT  128.905 277.68 129.269 277.8 ;
     RECT  129.253 210.576 129.299 211.272 ;
     RECT  128.869 172.608 129.301 173.064 ;
     RECT  128.531 190.272 129.337 191.448 ;
     RECT  128.339 187.92 129.373 188.52 ;
     RECT  129.337 190.272 129.373 191.64 ;
     RECT  128.54 230.208 129.373 231.336 ;
     RECT  129.373 190.272 129.409 191.784 ;
     RECT  129.265 192.816 129.409 193.128 ;
     RECT  129.089 218.304 129.413 218.712 ;
     RECT  128.725 162.144 129.445 162.168 ;
     RECT  128.909 186 129.445 186.408 ;
     RECT  129.373 230.112 129.445 231.336 ;
     RECT  128.653 213.456 129.449 213.96 ;
     RECT  129.116 219.984 129.449 221.208 ;
     RECT  129.161 155.568 129.481 155.592 ;
     RECT  129.409 190.272 129.517 193.128 ;
     RECT  129.481 155.568 129.521 156.168 ;
     RECT  128.297 181.92 129.553 182.664 ;
     RECT  129.373 187.872 129.553 188.52 ;
     RECT  127.715 202.848 129.553 203.544 ;
     RECT  129.445 229.632 129.557 231.336 ;
     RECT  128.441 175.824 129.589 179.16 ;
     RECT  128.693 180.288 129.589 180.312 ;
     RECT  129.121 195.072 129.589 196.92 ;
     RECT  129.013 198.144 129.589 199.08 ;
     RECT  128.581 206.16 129.589 207 ;
     RECT  129.013 157.776 129.593 158.52 ;
     RECT  129.049 223.968 129.593 224.424 ;
     RECT  129.589 195.072 129.629 199.08 ;
     RECT  129.445 185.136 129.661 186.408 ;
     RECT  129.557 230.112 129.665 231.336 ;
     RECT  129.521 156.144 129.685 156.168 ;
     RECT  129.553 187.824 129.697 188.52 ;
     RECT  129.685 156.144 129.731 156.792 ;
     RECT  129.593 157.776 129.731 158.04 ;
     RECT  129.517 190.272 129.769 193.368 ;
     RECT  129.731 156.768 129.773 156.792 ;
     RECT  129.161 232.416 129.773 232.44 ;
     RECT  129.697 187.824 129.805 188.568 ;
     RECT  129.589 205.344 129.809 207 ;
     RECT  128.099 225.696 129.809 225.72 ;
     RECT  127.577 183.648 129.877 183.672 ;
     RECT  129.661 184.656 129.877 186.408 ;
     RECT  129.053 208.896 129.877 209.448 ;
     RECT  129.299 210.576 129.877 210.6 ;
     RECT  128.369 160.752 129.913 160.776 ;
     RECT  129.445 162.096 129.913 162.168 ;
     RECT  129.553 181.776 129.913 182.664 ;
     RECT  129.665 230.208 129.917 230.232 ;
     RECT  129.805 187.824 129.949 188.76 ;
     RECT  129.769 190.272 129.949 193.464 ;
     RECT  129.251 166.416 129.953 167.016 ;
     RECT  129.809 205.344 129.953 206.328 ;
     RECT  129.449 213.456 129.98 213.672 ;
     RECT  129.877 183.648 129.985 186.408 ;
     RECT  129.949 187.824 129.985 189.048 ;
     RECT  129.949 190.032 129.985 193.464 ;
     RECT  129.629 195.36 130.019 199.08 ;
     RECT  129.589 175.824 130.021 180.312 ;
     RECT  129.913 181.584 130.021 182.664 ;
     RECT  129.985 183.648 130.021 189.048 ;
     RECT  129.665 231.312 130.025 231.336 ;
     RECT  129.913 160.752 130.061 162.168 ;
     RECT  129.053 216.192 130.093 216.36 ;
     RECT  130.019 195.36 130.097 198.552 ;
     RECT  129.155 169.728 130.117 171.48 ;
     RECT  130.093 216.192 130.133 216.456 ;
     RECT  129.769 201.792 130.165 201.816 ;
     RECT  129.413 218.592 130.165 218.712 ;
     RECT  129.985 190.032 130.169 193.704 ;
     RECT  129.953 205.344 130.201 205.704 ;
     RECT  129.449 219.984 130.205 220.68 ;
     RECT  129.553 202.848 130.211 203.976 ;
     RECT  130.211 203.376 130.252 203.976 ;
     RECT  130.169 190.272 130.309 193.704 ;
     RECT  130.165 218.592 130.417 218.904 ;
     RECT  130.252 203.52 130.453 203.976 ;
     RECT  130.201 205.008 130.453 205.704 ;
     RECT  130.381 233.616 130.488 233.64 ;
     RECT  129.98 213.024 130.489 213.672 ;
     RECT  130.097 198.192 130.493 198.552 ;
     RECT  130.417 218.592 130.493 219.24 ;
     RECT  130.133 216.336 130.501 216.456 ;
     RECT  130.309 199.584 130.525 200.04 ;
     RECT  130.501 216.336 130.547 217.416 ;
     RECT  130.345 227.04 130.549 227.064 ;
     RECT  129.661 228.24 130.549 228.264 ;
     RECT  130.488 233.04 130.549 233.64 ;
     RECT  130.345 235.2 130.549 235.224 ;
     RECT  130.309 190.272 130.561 193.8 ;
     RECT  130.549 227.04 130.595 228.264 ;
     RECT  130.549 233.04 130.595 235.56 ;
     RECT  130.117 169.248 130.597 171.48 ;
     RECT  130.597 168.288 130.633 171.48 ;
     RECT  129.877 208.896 130.633 210.6 ;
     RECT  130.021 212.016 130.633 212.04 ;
     RECT  130.205 220.272 130.637 220.68 ;
     RECT  130.021 175.824 130.669 189.048 ;
     RECT  130.669 175.824 130.673 189.096 ;
     RECT  130.633 168.288 130.741 171.576 ;
     RECT  129.301 172.608 130.741 173.784 ;
     RECT  130.633 164.256 130.777 164.28 ;
     RECT  130.595 227.424 130.777 228.264 ;
     RECT  130.165 201.744 130.781 201.816 ;
     RECT  130.595 233.04 130.787 234.312 ;
     RECT  130.525 199.584 130.796 200.472 ;
     RECT  130.493 198.288 130.817 198.552 ;
     RECT  130.796 199.584 130.883 200.664 ;
     RECT  130.633 208.896 130.885 212.04 ;
     RECT  130.489 213.024 130.885 213.72 ;
     RECT  130.885 207.696 130.921 207.72 ;
     RECT  130.885 208.896 130.921 213.72 ;
     RECT  129.953 166.416 130.957 166.44 ;
     RECT  130.777 227.424 130.961 228.888 ;
     RECT  130.076 231.936 130.961 232.008 ;
     RECT  130.957 166.416 130.988 167.304 ;
     RECT  130.741 168.288 130.988 173.784 ;
     RECT  130.673 175.824 131.029 179.208 ;
     RECT  130.817 198.528 131.029 198.552 ;
     RECT  130.883 199.584 131.029 200.04 ;
     RECT  131.029 174.816 131.033 179.208 ;
     RECT  130.849 151.008 131.077 151.032 ;
     RECT  129.445 153.888 131.209 153.912 ;
     RECT  130.988 166.416 131.245 173.784 ;
     RECT  130.921 207.696 131.245 213.72 ;
     RECT  131.101 162.192 131.281 162.216 ;
     RECT  130.061 160.752 131.353 160.776 ;
     RECT  131.281 162.048 131.353 162.264 ;
     RECT  131.077 151.008 131.425 151.368 ;
     RECT  130.561 190.272 131.425 193.848 ;
     RECT  130.777 164.256 131.497 164.376 ;
     RECT  130.493 218.88 131.497 219.24 ;
     RECT  129.593 224.4 131.564 224.424 ;
     RECT  131.065 149.328 131.569 149.352 ;
     RECT  129.949 214.848 131.605 214.872 ;
     RECT  131.564 224.4 131.605 224.568 ;
     RECT  130.705 225.744 131.605 225.768 ;
     RECT  131.209 153.888 131.641 154.488 ;
     RECT  130.547 216.336 131.641 216.36 ;
     RECT  130.547 217.392 131.641 217.416 ;
     RECT  131.497 164.256 131.653 164.808 ;
     RECT  131.245 166.08 131.653 173.784 ;
     RECT  130.453 203.52 131.708 205.704 ;
     RECT  131.245 206.928 131.708 213.72 ;
     RECT  131.653 164.256 131.713 173.784 ;
     RECT  131.033 174.816 131.713 179.16 ;
     RECT  131.245 156.768 131.845 156.792 ;
     RECT  129.731 158.016 131.893 158.04 ;
     RECT  131.353 160.752 131.893 162.264 ;
     RECT  130.961 227.424 132.001 228.264 ;
     RECT  131.569 149.184 132.008 149.352 ;
     RECT  131.425 150.432 132.008 151.368 ;
     RECT  131.077 152.784 132.008 152.808 ;
     RECT  131.641 153.888 132.008 155.064 ;
     RECT  131.845 156.144 132.008 156.792 ;
     RECT  131.893 158.016 132.008 162.264 ;
     RECT  131.713 164.256 132.008 179.16 ;
     RECT  130.673 180.288 132.008 189.096 ;
     RECT  131.425 190.272 132.008 194.328 ;
     RECT  130.097 195.36 132.008 197.208 ;
     RECT  131.029 198.528 132.008 200.04 ;
     RECT  131.317 202.176 132.008 202.2 ;
     RECT  131.708 203.328 132.008 213.72 ;
     RECT  131.605 214.752 132.008 214.872 ;
     RECT  131.641 216.336 132.008 217.416 ;
     RECT  131.497 218.64 132.008 219.24 ;
     RECT  130.637 220.656 132.008 220.68 ;
     RECT  131.605 223.44 132.008 225.768 ;
     RECT  132.001 227.424 132.008 228.504 ;
     RECT  131.065 232.08 132.008 232.92 ;
     RECT  130.787 234.288 132.008 234.312 ;
     RECT  130.595 235.536 132.008 235.56 ;
     RECT  131.857 237.792 132.008 237.816 ;
     RECT  129.269 277.68 132.008 277.704 ;
     RECT  132.008 2.148 132.112 369.372 ;
     RECT  132.101 371.376 132.229 371.4 ;
     RECT  132.112 2.418 132.304 369.102 ;
     RECT  132.229 371.28 132.317 371.4 ;
     RECT  132.304 167.28 132.401 168.696 ;
     RECT  132.304 212.64 132.401 214.776 ;
     RECT  132.317 371.184 132.401 371.4 ;
     RECT  132.304 162.144 132.419 163.032 ;
     RECT  132.401 213.648 132.419 214.776 ;
     RECT  132.304 216.144 132.419 217.272 ;
     RECT  132.304 218.352 132.419 218.376 ;
     RECT  132.304 219.6 132.419 219.72 ;
     RECT  132.304 226.752 132.419 226.872 ;
     RECT  132.304 227.952 132.419 229.32 ;
     RECT  132.304 236.496 132.419 236.712 ;
     RECT  132.304 237.792 132.419 239.976 ;
     RECT  132.304 224.976 132.445 225.72 ;
     RECT  132.304 277.68 132.467 277.704 ;
     RECT  132.401 371.28 132.467 371.4 ;
     RECT  132.304 169.728 132.473 176.52 ;
     RECT  132.473 171.552 132.509 176.52 ;
     RECT  132.304 246.432 132.563 246.456 ;
     RECT  132.467 371.376 132.563 371.4 ;
     RECT  132.419 228.144 132.581 229.32 ;
     RECT  132.304 233.664 132.581 234.84 ;
     RECT  132.304 180.288 132.617 188.568 ;
     RECT  132.401 167.28 132.653 167.736 ;
     RECT  132.304 204.768 132.689 210.408 ;
     RECT  132.509 171.552 132.725 176.424 ;
     RECT  132.419 226.848 132.803 226.872 ;
     RECT  132.419 219.6 132.833 219.672 ;
     RECT  132.419 238.752 132.833 239.976 ;
     RECT  132.304 242.832 132.833 243.384 ;
     RECT  132.304 155.856 132.861 158.424 ;
     RECT  132.304 153.888 132.905 153.912 ;
     RECT  132.473 169.728 132.905 170.424 ;
     RECT  132.304 159.888 132.941 159.912 ;
     RECT  132.304 151.008 133.013 151.032 ;
     RECT  132.304 202.32 133.049 202.92 ;
     RECT  132.581 234.816 133.084 234.84 ;
     RECT  132.617 180.288 133.121 186.36 ;
     RECT  133.049 202.896 133.121 202.92 ;
     RECT  132.304 161.088 133.157 161.112 ;
     RECT  132.833 219.6 133.265 219.624 ;
     RECT  132.581 228.48 133.301 229.32 ;
     RECT  132.304 147.744 133.333 147.768 ;
     RECT  132.689 207.216 133.333 210.408 ;
     RECT  132.581 233.664 133.333 233.688 ;
     RECT  132.419 236.544 133.333 236.712 ;
     RECT  132.861 155.856 133.369 155.88 ;
     RECT  132.304 177.552 133.369 179.256 ;
     RECT  133.121 180.288 133.369 186.216 ;
     RECT  132.689 204.768 133.369 205.944 ;
     RECT  133.333 233.568 133.373 233.688 ;
     RECT  132.419 216.336 133.381 217.272 ;
     RECT  132.861 157.44 133.409 158.424 ;
     RECT  133.381 216 133.427 217.272 ;
     RECT  132.617 187.488 133.429 188.568 ;
     RECT  132.304 190.272 133.429 194.28 ;
     RECT  132.419 162.912 133.445 163.032 ;
     RECT  132.653 167.568 133.445 167.736 ;
     RECT  132.304 195.648 133.477 197.208 ;
     RECT  132.304 198.24 133.477 201.192 ;
     RECT  132.401 212.64 133.477 212.664 ;
     RECT  132.419 213.648 133.477 214.584 ;
     RECT  133.333 207.216 133.513 211.32 ;
     RECT  133.477 212.64 133.513 214.68 ;
     RECT  133.445 167.712 133.549 167.736 ;
     RECT  133.477 195.648 133.585 201.192 ;
     RECT  133.445 162.912 133.621 162.936 ;
     RECT  133.369 204.048 133.621 205.944 ;
     RECT  133.429 187.488 133.657 194.28 ;
     RECT  133.427 217.248 133.729 217.272 ;
     RECT  133.477 218.592 133.729 218.616 ;
     RECT  133.369 154.464 133.733 155.88 ;
     RECT  132.905 170.4 133.733 170.424 ;
     RECT  132.725 171.888 133.765 176.424 ;
     RECT  133.369 177.552 133.765 186.216 ;
     RECT  133.657 187.44 133.813 194.28 ;
     RECT  133.585 195.552 133.813 201.192 ;
     RECT  132.304 146.64 133.837 146.664 ;
     RECT  132.304 164.256 133.909 165 ;
     RECT  133.333 147.744 133.913 148.296 ;
     RECT  133.909 164.256 133.945 165.336 ;
     RECT  133.868 149.856 133.955 149.88 ;
     RECT  133.621 162.384 133.981 162.936 ;
     RECT  133.729 217.248 133.985 218.616 ;
     RECT  133.301 229.296 133.985 229.32 ;
     RECT  132.833 238.752 134.021 239.592 ;
     RECT  133.409 158.4 134.053 158.424 ;
     RECT  133.333 236.544 134.053 236.76 ;
     RECT  133.813 187.44 134.089 201.192 ;
     RECT  133.873 153.888 134.093 153.912 ;
     RECT  133.985 217.248 134.093 217.752 ;
     RECT  134.053 236.544 134.093 237.72 ;
     RECT  134.089 187.44 134.125 201.816 ;
     RECT  133.837 145.344 134.149 146.664 ;
     RECT  133.765 171.888 134.161 186.216 ;
     RECT  133.621 204 134.161 205.944 ;
     RECT  133.513 207.216 134.161 214.68 ;
     RECT  132.304 222.24 134.161 222.264 ;
     RECT  134.161 204 134.165 214.68 ;
     RECT  134.149 144.624 134.195 146.664 ;
     RECT  134.195 144.624 134.197 144.648 ;
     RECT  133.427 216 134.197 216.024 ;
     RECT  134.165 213.12 134.233 214.68 ;
     RECT  134.197 215.664 134.233 216.024 ;
     RECT  134.197 144.528 134.237 144.648 ;
     RECT  132.304 221.136 134.237 221.16 ;
     RECT  134.204 241.632 134.291 241.656 ;
     RECT  132.833 243.36 134.291 243.384 ;
     RECT  134.165 204 134.305 211.992 ;
     RECT  133.945 164.112 134.309 165.336 ;
     RECT  134.252 138.576 134.339 138.6 ;
     RECT  134.125 187.2 134.339 201.816 ;
     RECT  132.445 224.976 134.345 225.192 ;
     RECT  133.957 244.56 134.345 244.584 ;
     RECT  134.293 137.04 134.38 137.064 ;
     RECT  133.549 167.712 134.413 168.12 ;
     RECT  134.345 224.976 134.413 225 ;
     RECT  133.373 233.568 134.413 233.592 ;
     RECT  134.233 213.12 134.417 216.024 ;
     RECT  133.441 231.216 134.444 231.24 ;
     RECT  132.304 232.272 134.476 232.296 ;
     RECT  133.981 162.144 134.485 162.936 ;
     RECT  134.161 171.264 134.485 186.216 ;
     RECT  134.339 187.2 134.485 195.864 ;
     RECT  134.417 214.704 134.521 216.024 ;
     RECT  134.339 196.896 134.525 201.816 ;
     RECT  134.444 230.352 134.525 231.24 ;
     RECT  134.413 233.568 134.525 234.312 ;
     RECT  134.525 230.352 134.531 230.376 ;
     RECT  134.485 161.904 134.557 162.936 ;
     RECT  134.309 164.112 134.557 165.048 ;
     RECT  133.733 154.896 134.561 155.88 ;
     RECT  134.457 226.992 134.569 227.016 ;
     RECT  134.161 222.192 134.581 222.264 ;
     RECT  134.521 220.368 134.627 220.392 ;
     RECT  134.053 158.4 134.629 159.144 ;
     RECT  134.525 196.896 134.633 201.048 ;
     RECT  134.561 154.896 134.701 155.832 ;
     RECT  134.593 202.224 134.701 202.488 ;
     RECT  134.581 221.568 134.701 222.36 ;
     RECT  134.629 158.352 134.713 159.144 ;
     RECT  134.701 154.32 134.723 155.832 ;
     RECT  134.305 203.616 134.764 211.992 ;
     RECT  134.195 146.16 134.773 146.664 ;
     RECT  133.913 147.744 134.773 148.248 ;
     RECT  134.485 171.264 134.813 195.864 ;
     RECT  134.773 146.16 134.819 148.248 ;
     RECT  134.557 161.904 134.879 165.048 ;
     RECT  134.485 152.448 134.953 152.472 ;
     RECT  134.713 158.4 134.957 159.144 ;
     RECT  133.909 142.32 134.989 142.344 ;
     RECT  134.879 161.616 135.001 165.048 ;
     RECT  134.701 202.224 135.025 202.632 ;
     RECT  134.764 203.616 135.025 205.128 ;
     RECT  134.093 217.728 135.059 217.752 ;
     RECT  134.917 149.472 135.061 149.496 ;
     RECT  134.981 218.88 135.065 218.904 ;
     RECT  134.723 154.32 135.097 155.4 ;
     RECT  134.953 152.448 135.101 152.712 ;
     RECT  134.819 146.496 135.107 148.248 ;
     RECT  134.881 169.776 135.169 169.8 ;
     RECT  134.413 167.568 135.205 168.12 ;
     RECT  135.169 169.104 135.205 169.8 ;
     RECT  134.764 206.352 135.205 211.992 ;
     RECT  134.417 213.12 135.205 213.672 ;
     RECT  134.413 224.208 135.205 225 ;
     RECT  134.093 236.688 135.205 237.72 ;
     RECT  135.205 167.568 135.245 169.8 ;
     RECT  133.513 140.544 135.313 140.568 ;
     RECT  134.989 142.32 135.313 142.44 ;
     RECT  134.633 196.896 135.347 201 ;
     RECT  135.061 149.472 135.353 149.784 ;
     RECT  135.097 154.272 135.353 155.4 ;
     RECT  135.353 154.416 135.389 155.4 ;
     RECT  135.205 236.4 135.397 237.72 ;
     RECT  134.021 239.568 135.421 239.592 ;
     RECT  133.801 151.392 135.493 151.416 ;
     RECT  135.397 236.4 135.533 238.248 ;
     RECT  135.313 140.544 135.548 142.44 ;
     RECT  135.205 224.064 135.569 225 ;
     RECT  135.457 138.96 135.589 138.984 ;
     RECT  135.548 140.544 135.589 142.776 ;
     RECT  134.917 231.408 135.601 231.432 ;
     RECT  134.701 221.568 135.605 222.84 ;
     RECT  134.525 233.568 135.605 233.64 ;
     RECT  135.589 138.96 135.635 143.304 ;
     RECT  135.635 140.688 135.637 143.304 ;
     RECT  135.493 150.432 135.641 151.416 ;
     RECT  135.601 230.928 135.673 231.432 ;
     RECT  135.641 150.432 135.683 150.456 ;
     RECT  135.635 138.96 135.713 139.704 ;
     RECT  134.957 158.4 135.713 159 ;
     RECT  135.421 239.568 135.733 240.504 ;
     RECT  134.665 241.728 135.733 242.28 ;
     RECT  134.665 243.264 135.733 243.288 ;
     RECT  135.673 244.416 135.733 244.44 ;
     RECT  135.205 206.352 135.74 213.672 ;
     RECT  135.733 239.568 135.779 243.288 ;
     RECT  135.733 244.416 135.779 244.728 ;
     RECT  134.237 144.528 135.781 144.552 ;
     RECT  135.347 196.896 135.781 200.712 ;
     RECT  135.025 202.224 135.817 205.128 ;
     RECT  135.779 239.568 135.82 241.08 ;
     RECT  135.781 144.528 135.827 145.08 ;
     RECT  135.827 145.056 135.868 145.08 ;
     RECT  135.569 224.4 135.889 225 ;
     RECT  135.673 230.928 135.929 231.912 ;
     RECT  134.813 171.264 135.961 195.672 ;
     RECT  135.781 196.848 135.961 200.712 ;
     RECT  135.637 140.688 135.965 143.448 ;
     RECT  135.349 226.32 135.965 226.344 ;
     RECT  135.74 206.352 135.98 213.72 ;
     RECT  134.521 214.704 135.98 216.648 ;
     RECT  135.001 163.872 136.069 165.048 ;
     RECT  135.107 146.496 136.073 147.768 ;
     RECT  136.073 147.024 136.109 147.768 ;
     RECT  135.98 206.352 136.141 216.648 ;
     RECT  135.745 217.776 136.141 218.232 ;
     RECT  135.779 244.704 136.141 244.728 ;
     RECT  135.673 246.24 136.141 246.264 ;
     RECT  135.82 239.568 136.172 240.504 ;
     RECT  135.817 201.696 136.249 205.128 ;
     RECT  136.141 206.352 136.249 218.232 ;
     RECT  134.701 135.888 136.253 135.912 ;
     RECT  135.965 140.688 136.253 142.44 ;
     RECT  136.141 244.704 136.253 246.264 ;
     RECT  135.605 222.816 136.259 222.84 ;
     RECT  135.889 224.4 136.259 225.192 ;
     RECT  136.172 239.04 136.259 240.504 ;
     RECT  134.845 137.616 136.261 137.64 ;
     RECT  135.713 138.96 136.261 138.984 ;
     RECT  136.069 163.872 136.261 165.384 ;
     RECT  136.249 201.696 136.277 218.232 ;
     RECT  135.533 236.4 136.285 237.816 ;
     RECT  135.389 154.512 136.289 155.4 ;
     RECT  136.261 137.616 136.307 138.984 ;
     RECT  135.245 167.568 136.307 169.128 ;
     RECT  135.605 233.616 136.321 233.64 ;
     RECT  135.961 171.264 136.357 200.712 ;
     RECT  136.277 201.696 136.361 218.328 ;
     RECT  136.253 244.704 136.361 246.072 ;
     RECT  135.101 152.688 136.393 152.712 ;
     RECT  135.529 157.344 136.393 157.368 ;
     RECT  136.307 168.528 136.393 169.128 ;
     RECT  136.261 163.872 136.501 166.296 ;
     RECT  136.393 168.528 136.597 169.416 ;
     RECT  136.357 171.024 136.597 200.712 ;
     RECT  136.393 157.296 136.652 157.368 ;
     RECT  135.713 158.4 136.652 158.712 ;
     RECT  136.501 159.696 136.681 159.72 ;
     RECT  135.001 161.616 136.681 162.456 ;
     RECT  136.501 163.872 136.681 167.544 ;
     RECT  135.929 230.928 136.741 231.816 ;
     RECT  136.717 229.68 136.753 229.704 ;
     RECT  136.597 168.528 136.789 200.712 ;
     RECT  136.361 201.696 136.789 218.28 ;
     RECT  136.393 219.456 136.789 219.48 ;
     RECT  135.097 247.344 136.789 247.368 ;
     RECT  136.681 159.696 136.825 160.2 ;
     RECT  136.681 161.616 136.825 167.544 ;
     RECT  136.652 157.296 137.041 158.712 ;
     RECT  136.825 159.696 137.041 167.544 ;
     RECT  136.741 230.736 137.185 231.816 ;
     RECT  136.321 233.616 137.221 234.552 ;
     RECT  136.753 229.536 137.257 229.704 ;
     RECT  136.789 219.456 137.293 220.248 ;
     RECT  137.293 145.584 137.329 145.608 ;
     RECT  137.041 157.296 137.329 167.544 ;
     RECT  136.789 168.528 137.329 218.28 ;
     RECT  136.361 244.704 137.365 244.728 ;
     RECT  136.289 154.848 137.401 155.4 ;
     RECT  136.969 135.648 137.408 135.672 ;
     RECT  136.307 138.432 137.408 138.984 ;
     RECT  136.253 141.072 137.408 142.44 ;
     RECT  135.965 143.424 137.408 143.448 ;
     RECT  137.329 145.584 137.408 146.424 ;
     RECT  136.109 147.744 137.408 147.768 ;
     RECT  135.637 149.424 137.408 149.448 ;
     RECT  136.393 151.584 137.408 152.712 ;
     RECT  137.401 154.8 137.408 155.4 ;
     RECT  137.329 157.296 137.408 218.28 ;
     RECT  137.293 219.408 137.408 220.248 ;
     RECT  135.605 221.568 137.408 221.592 ;
     RECT  136.259 224.496 137.408 225.192 ;
     RECT  137.041 226.272 137.408 226.296 ;
     RECT  137.257 228.768 137.408 229.704 ;
     RECT  137.185 230.736 137.408 232.392 ;
     RECT  137.221 233.616 137.408 235.272 ;
     RECT  136.285 236.304 137.408 237.816 ;
     RECT  136.259 239.088 137.408 240.504 ;
     RECT  135.779 242.304 137.408 242.808 ;
     RECT  137.365 244.224 137.408 244.728 ;
     RECT  136.361 246.048 137.408 246.072 ;
     RECT  136.789 247.2 137.408 247.368 ;
     RECT  137.408 2.148 137.512 369.372 ;
     RECT  137.512 2.418 137.704 369.102 ;
     RECT  137.704 228.768 137.765 232.536 ;
     RECT  137.704 236.304 137.765 240.504 ;
     RECT  137.704 150.432 137.843 155.88 ;
     RECT  137.704 226.464 137.891 226.632 ;
     RECT  137.765 228.768 137.891 231.432 ;
     RECT  137.704 145.584 137.909 149.448 ;
     RECT  137.704 227.76 137.932 227.784 ;
     RECT  137.704 159.648 137.939 221.448 ;
     RECT  137.891 229.68 137.939 231.432 ;
     RECT  137.939 162.384 137.945 221.448 ;
     RECT  137.939 159.648 137.981 160.44 ;
     RECT  137.704 143.04 137.987 144.504 ;
     RECT  137.704 222.816 137.987 225 ;
     RECT  137.909 145.584 138.017 146.76 ;
     RECT  137.939 229.68 138.017 229.896 ;
     RECT  137.987 143.04 138.025 143.064 ;
     RECT  137.945 162.384 138.035 221.208 ;
     RECT  138.035 214.704 138.053 221.208 ;
     RECT  137.704 233.568 138.125 234.552 ;
     RECT  137.765 236.304 138.161 239.592 ;
     RECT  137.704 134.496 138.197 135.672 ;
     RECT  137.981 159.648 138.197 159.96 ;
     RECT  138.035 162.384 138.197 213.72 ;
     RECT  137.987 222.816 138.269 224.28 ;
     RECT  138.197 165.024 138.305 213.72 ;
     RECT  138.269 224.064 138.305 224.28 ;
     RECT  137.843 152.16 138.413 154.872 ;
     RECT  138.161 236.304 138.449 236.424 ;
     RECT  138.197 135.168 138.515 135.672 ;
     RECT  137.704 136.8 138.521 139.176 ;
     RECT  138.515 135.168 138.557 135.432 ;
     RECT  138.305 224.064 138.557 224.184 ;
     RECT  138.413 152.16 138.563 154.776 ;
     RECT  137.704 248.496 138.563 249.288 ;
     RECT  137.843 150.432 138.611 151.032 ;
     RECT  138.611 150.432 138.629 150.648 ;
     RECT  138.563 152.976 138.652 154.776 ;
     RECT  137.704 246.048 138.701 247.512 ;
     RECT  138.521 136.8 138.737 138.552 ;
     RECT  137.909 147.888 138.737 149.352 ;
     RECT  137.704 241.536 138.737 242.424 ;
     RECT  138.701 247.152 138.737 247.512 ;
     RECT  137.704 141.36 138.769 141.384 ;
     RECT  138.737 241.632 138.773 242.424 ;
     RECT  138.701 246.048 138.913 246.072 ;
     RECT  138.557 135.168 138.953 135.24 ;
     RECT  137.704 244.224 138.953 244.248 ;
     RECT  138.017 229.872 138.989 229.896 ;
     RECT  138.563 249.264 138.997 249.288 ;
     RECT  138.053 214.896 139.021 221.208 ;
     RECT  138.269 222.816 139.021 222.84 ;
     RECT  138.773 241.632 139.025 242.328 ;
     RECT  138.997 249.264 139.043 249.672 ;
     RECT  138.913 245.328 139.061 246.072 ;
     RECT  138.305 167.184 139.129 213.72 ;
     RECT  139.021 214.896 139.129 222.84 ;
     RECT  138.125 233.568 139.129 234.168 ;
     RECT  138.737 137.328 139.133 138.552 ;
     RECT  138.017 145.872 139.133 146.76 ;
     RECT  138.949 158.352 139.165 158.376 ;
     RECT  139.165 157.872 139.169 158.376 ;
     RECT  139.133 145.872 139.205 146.568 ;
     RECT  138.737 147.888 139.205 147.912 ;
     RECT  139.025 241.632 139.205 242.088 ;
     RECT  139.129 233.568 139.229 234.264 ;
     RECT  137.765 232.512 139.273 232.536 ;
     RECT  139.229 233.568 139.273 234.312 ;
     RECT  138.197 162.432 139.309 163.992 ;
     RECT  138.305 165.024 139.309 166.152 ;
     RECT  139.129 167.184 139.309 222.84 ;
     RECT  137.939 231.312 139.333 231.432 ;
     RECT  139.273 232.512 139.333 234.312 ;
     RECT  137.891 226.464 139.34 226.488 ;
     RECT  138.949 228.384 139.34 228.408 ;
     RECT  138.161 237.744 139.345 239.592 ;
     RECT  139.309 162.432 139.379 222.84 ;
     RECT  139.333 231.312 139.379 234.312 ;
     RECT  138.652 153.12 139.421 154.776 ;
     RECT  139.345 237.744 139.421 239.976 ;
     RECT  139.34 226.464 139.427 228.408 ;
     RECT  138.197 159.648 139.429 159.768 ;
     RECT  139.421 238.224 139.429 239.976 ;
     RECT  138.769 140.784 139.453 141.384 ;
     RECT  139.205 241.632 139.457 241.656 ;
     RECT  138.557 224.16 139.493 224.184 ;
     RECT  139.285 236.544 139.529 236.568 ;
     RECT  139.379 231.312 139.561 232.824 ;
     RECT  139.379 213.504 139.597 222.84 ;
     RECT  139.133 137.904 139.619 138.552 ;
     RECT  139.169 157.872 139.633 158.088 ;
     RECT  139.619 138.528 139.665 138.552 ;
     RECT  138.737 247.2 139.667 247.512 ;
     RECT  138.629 150.624 139.705 150.648 ;
     RECT  139.421 154.464 139.741 154.776 ;
     RECT  138.953 135.216 139.813 135.24 ;
     RECT  139.427 227.472 139.849 228.408 ;
     RECT  139.813 135.216 139.853 135.672 ;
     RECT  139.597 213.504 139.853 223.944 ;
     RECT  139.705 150.48 139.885 150.648 ;
     RECT  139.379 162.432 139.889 211.944 ;
     RECT  139.021 143.424 139.921 143.448 ;
     RECT  139.427 226.464 139.925 226.488 ;
     RECT  139.421 153.12 139.993 153.144 ;
     RECT  139.993 152.784 140.033 153.144 ;
     RECT  139.849 227.472 140.033 229.128 ;
     RECT  139.561 230.928 140.053 232.824 ;
     RECT  139.741 154.464 140.069 156.168 ;
     RECT  139.885 149.52 140.137 150.696 ;
     RECT  139.885 147.792 140.173 147.816 ;
     RECT  139.043 249.648 140.177 249.672 ;
     RECT  139.429 159.072 140.197 159.768 ;
     RECT  139.889 162.432 140.197 190.92 ;
     RECT  139.853 218.976 140.249 223.944 ;
     RECT  140.197 159.072 140.285 159.96 ;
     RECT  140.053 230.304 140.285 232.824 ;
     RECT  140.197 161.76 140.357 190.92 ;
     RECT  140.285 230.928 140.357 232.824 ;
     RECT  139.061 245.328 140.389 245.352 ;
     RECT  140.389 244.56 140.425 245.352 ;
     RECT  140.245 241.92 140.461 241.944 ;
     RECT  139.667 247.344 140.461 247.512 ;
     RECT  139.889 192.048 140.533 211.944 ;
     RECT  139.205 146.304 140.537 146.568 ;
     RECT  140.173 147.744 140.537 147.816 ;
     RECT  140.137 149.52 140.537 150.792 ;
     RECT  140.533 192.048 140.537 212.04 ;
     RECT  140.537 146.304 140.569 146.52 ;
     RECT  140.461 241.488 140.569 241.944 ;
     RECT  140.285 159.072 140.573 159.768 ;
     RECT  140.357 231.024 140.579 232.824 ;
     RECT  140.033 152.784 140.605 152.808 ;
     RECT  139.429 238.224 140.605 239.112 ;
     RECT  140.569 240.528 140.653 241.944 ;
     RECT  140.653 241.008 140.677 241.944 ;
     RECT  140.281 243.36 140.677 243.384 ;
     RECT  140.425 244.56 140.681 246.216 ;
     RECT  139.777 236.448 140.705 236.472 ;
     RECT  140.705 236.448 140.725 236.712 ;
     RECT  140.461 247.344 140.725 247.656 ;
     RECT  140.681 245.328 140.75 246.216 ;
     RECT  140.75 245.376 140.771 246.216 ;
     RECT  140.725 236.016 140.789 236.712 ;
     RECT  140.249 218.976 140.812 220.68 ;
     RECT  140.789 236.016 140.812 236.568 ;
     RECT  139.453 140.592 140.821 141.384 ;
     RECT  139.921 142.56 140.821 143.448 ;
     RECT  140.537 150.432 140.821 150.792 ;
     RECT  140.605 151.872 140.821 152.808 ;
     RECT  140.249 221.712 140.821 223.944 ;
     RECT  140.069 154.464 140.825 155.688 ;
     RECT  140.033 229.104 140.825 229.128 ;
     RECT  139.379 234.24 140.917 234.312 ;
     RECT  140.605 238.224 140.929 239.256 ;
     RECT  140.357 162.432 140.933 190.92 ;
     RECT  139.853 213.504 140.933 217.704 ;
     RECT  139.853 135.648 140.956 135.672 ;
     RECT  140.917 234.24 140.963 234.36 ;
     RECT  140.537 210.912 140.965 212.04 ;
     RECT  140.933 213.648 140.965 217.704 ;
     RECT  140.713 138.336 140.969 138.36 ;
     RECT  140.677 241.008 141.005 243.384 ;
     RECT  140.965 213.648 141.011 217.752 ;
     RECT  140.821 148.176 141.013 148.2 ;
     RECT  139.633 157.344 141.037 158.088 ;
     RECT  140.573 159.072 141.037 159.624 ;
     RECT  140.929 238.08 141.041 239.256 ;
     RECT  140.821 140.592 141.061 143.448 ;
     RECT  140.033 227.472 141.109 227.544 ;
     RECT  141.037 157.344 141.113 159.624 ;
     RECT  140.963 234.336 141.149 234.36 ;
     RECT  140.812 236.448 141.149 236.568 ;
     RECT  140.821 150.432 141.157 152.808 ;
     RECT  140.933 162.672 141.205 190.92 ;
     RECT  140.537 192.048 141.205 209.88 ;
     RECT  141.011 217.68 141.221 217.752 ;
     RECT  141.005 241.008 141.221 242.568 ;
     RECT  141.157 150.72 141.251 152.808 ;
     RECT  140.825 154.464 141.251 154.968 ;
     RECT  141.061 140.208 141.253 143.448 ;
     RECT  141.212 144.768 141.253 144.792 ;
     RECT  140.245 136.752 141.257 136.776 ;
     RECT  141.205 162.672 141.293 209.88 ;
     RECT  141.253 140.208 141.299 144.792 ;
     RECT  141.041 238.224 141.301 239.256 ;
     RECT  141.013 148.176 141.329 148.824 ;
     RECT  141.293 162.672 141.329 190.92 ;
     RECT  140.725 247.296 141.329 249.144 ;
     RECT  141.221 241.008 141.347 242.376 ;
     RECT  140.579 231.024 141.397 231.96 ;
     RECT  141.329 167.472 141.401 190.92 ;
     RECT  141.347 241.92 141.401 242.376 ;
     RECT  141.293 192.048 141.437 209.88 ;
     RECT  141.113 157.344 141.473 158.952 ;
     RECT  140.812 218.976 141.473 220.488 ;
     RECT  141.061 139.2 141.491 139.224 ;
     RECT  141.221 217.728 141.505 217.752 ;
     RECT  141.473 218.976 141.505 219.432 ;
     RECT  141.437 194.16 141.545 209.88 ;
     RECT  141.505 217.728 141.545 219.432 ;
     RECT  140.173 252.096 141.577 252.12 ;
     RECT  141.473 220.416 141.581 220.488 ;
     RECT  141.299 140.208 141.587 144.216 ;
     RECT  141.329 148.56 141.613 148.824 ;
     RECT  140.965 229.632 141.613 229.704 ;
     RECT  141.545 194.208 141.644 209.88 ;
     RECT  140.965 210.912 141.644 212.664 ;
     RECT  141.613 229.632 141.649 229.752 ;
     RECT  141.397 230.736 141.649 231.96 ;
     RECT  141.401 167.472 141.653 190.728 ;
     RECT  141.251 150.72 141.697 151.896 ;
     RECT  141.644 194.208 141.731 212.664 ;
     RECT  141.587 140.208 141.793 140.568 ;
     RECT  141.149 236.544 141.793 236.568 ;
     RECT  141.731 194.208 141.797 209.208 ;
     RECT  141.587 141.84 141.827 144.216 ;
     RECT  140.771 245.376 141.901 245.4 ;
     RECT  141.731 210.384 141.932 212.664 ;
     RECT  141.011 213.648 141.932 216.648 ;
     RECT  141.901 232.944 141.937 232.968 ;
     RECT  141.109 226.608 142.009 227.544 ;
     RECT  142.009 226.464 142.028 227.544 ;
     RECT  141.251 154.464 142.153 154.872 ;
     RECT  141.932 210.384 142.153 216.648 ;
     RECT  142.028 226.272 142.153 227.544 ;
     RECT  141.793 236.544 142.153 236.856 ;
     RECT  141.329 162.672 142.172 166.248 ;
     RECT  142.172 162.432 142.189 166.248 ;
     RECT  142.189 162.336 142.213 166.248 ;
     RECT  142.153 235.968 142.213 236.856 ;
     RECT  141.649 229.632 142.261 231.96 ;
     RECT  141.937 232.944 142.261 233.496 ;
     RECT  140.821 221.712 142.297 224.424 ;
     RECT  142.153 226.272 142.297 227.736 ;
     RECT  141.401 242.304 142.297 242.376 ;
     RECT  141.901 245.376 142.297 246.312 ;
     RECT  141.329 247.296 142.297 248.76 ;
     RECT  142.117 135.216 142.405 135.24 ;
     RECT  141.653 169.104 142.405 190.728 ;
     RECT  141.437 192.048 142.405 193.128 ;
     RECT  142.297 226.272 142.405 228.024 ;
     RECT  142.261 229.632 142.405 233.496 ;
     RECT  142.153 154.416 142.441 154.872 ;
     RECT  142.153 210.384 142.453 216.696 ;
     RECT  142.405 169.104 142.513 193.128 ;
     RECT  141.797 194.208 142.513 209.112 ;
     RECT  142.405 226.224 142.513 228.024 ;
     RECT  142.213 162.144 142.645 166.248 ;
     RECT  141.653 167.472 142.645 168.12 ;
     RECT  142.513 250.176 142.645 250.2 ;
     RECT  141.613 148.56 142.652 149.256 ;
     RECT  141.697 150.72 142.652 150.744 ;
     RECT  142.213 234.72 142.657 234.744 ;
     RECT  142.213 235.776 142.657 236.856 ;
     RECT  141.404 137.616 142.693 137.64 ;
     RECT  141.793 139.344 142.693 140.568 ;
     RECT  141.581 220.416 142.693 220.44 ;
     RECT  142.297 221.712 142.693 224.52 ;
     RECT  142.297 242.304 142.693 242.616 ;
     RECT  141.473 158.208 142.765 158.952 ;
     RECT  142.405 135.072 142.808 135.24 ;
     RECT  142.477 136.224 142.808 136.248 ;
     RECT  142.693 137.616 142.808 140.568 ;
     RECT  141.827 141.84 142.808 143.832 ;
     RECT  140.569 145.872 142.808 146.52 ;
     RECT  142.652 148.56 142.808 150.744 ;
     RECT  141.697 151.872 142.808 151.896 ;
     RECT  142.441 153.744 142.808 154.872 ;
     RECT  142.765 157.584 142.808 159.24 ;
     RECT  142.645 162.144 142.808 168.12 ;
     RECT  142.513 169.104 142.808 209.112 ;
     RECT  142.453 210.384 142.808 216.936 ;
     RECT  141.545 218.256 142.808 219.432 ;
     RECT  142.693 220.416 142.808 224.52 ;
     RECT  142.513 225.792 142.808 228.024 ;
     RECT  142.405 229.152 142.808 233.496 ;
     RECT  142.657 234.72 142.808 236.856 ;
     RECT  141.301 238.224 142.808 239.976 ;
     RECT  142.693 242.256 142.808 242.616 ;
     RECT  141.325 243.696 142.808 243.96 ;
     RECT  142.297 245.376 142.808 248.76 ;
     RECT  142.645 250.176 142.808 250.344 ;
     RECT  141.577 252 142.808 252.12 ;
     RECT  142.808 2.148 142.912 369.372 ;
     RECT  142.912 2.418 143.104 369.102 ;
     RECT  143.104 216.096 143.129 216.936 ;
     RECT  143.104 153.36 143.219 155.064 ;
     RECT  143.104 168.384 143.219 209.352 ;
     RECT  143.104 210.384 143.219 215.064 ;
     RECT  143.219 212.016 143.267 215.064 ;
     RECT  143.104 226.32 143.273 226.68 ;
     RECT  143.104 245.04 143.315 248.76 ;
     RECT  143.104 232.896 143.345 233.976 ;
     RECT  143.345 233.472 143.363 233.976 ;
     RECT  143.104 235.152 143.363 236.568 ;
     RECT  143.273 226.32 143.417 226.632 ;
     RECT  143.104 239.616 143.453 239.976 ;
     RECT  143.267 212.016 143.459 212.664 ;
     RECT  143.267 213.888 143.489 215.064 ;
     RECT  143.104 228.24 143.489 229.08 ;
     RECT  143.104 249.792 143.489 250.2 ;
     RECT  143.363 235.488 143.497 236.568 ;
     RECT  143.104 142.32 143.507 142.344 ;
     RECT  143.104 242.256 143.525 242.904 ;
     RECT  143.459 212.352 143.561 212.664 ;
     RECT  143.104 218.592 143.603 220.152 ;
     RECT  143.219 153.36 143.633 153.816 ;
     RECT  143.603 218.592 143.644 220.104 ;
     RECT  143.489 250.176 143.651 250.2 ;
     RECT  143.315 248.208 143.669 248.76 ;
     RECT  143.219 154.848 143.699 155.064 ;
     RECT  143.104 221.184 143.699 225.144 ;
     RECT  143.315 245.04 143.699 246.888 ;
     RECT  143.104 230.112 143.795 231.336 ;
     RECT  143.104 146.496 143.813 146.52 ;
     RECT  143.699 224.16 143.813 225.144 ;
     RECT  143.104 138.576 143.849 138.696 ;
     RECT  143.497 235.488 143.849 236.04 ;
     RECT  143.104 156.72 143.939 159.288 ;
     RECT  143.104 162.048 144.029 167.064 ;
     RECT  143.939 157.872 144.065 159.288 ;
     RECT  143.699 221.184 144.101 222.888 ;
     RECT  143.104 251.328 144.133 251.352 ;
     RECT  143.363 233.664 144.145 233.976 ;
     RECT  143.795 230.352 144.173 231.336 ;
     RECT  144.145 233.664 144.173 233.688 ;
     RECT  143.104 150.72 144.188 151.992 ;
     RECT  143.849 138.576 144.197 138.6 ;
     RECT  144.029 165.024 144.205 167.064 ;
     RECT  143.219 168.384 144.205 209.112 ;
     RECT  144.197 137.904 144.236 138.6 ;
     RECT  143.489 213.888 144.245 214.872 ;
     RECT  143.813 224.496 144.245 225.144 ;
     RECT  144.236 137.472 144.277 138.6 ;
     RECT  143.104 140.448 144.277 140.568 ;
     RECT  144.277 136.752 144.281 138.6 ;
     RECT  143.489 228.576 144.281 229.08 ;
     RECT  143.669 248.736 144.281 248.76 ;
     RECT  143.525 242.256 144.313 242.664 ;
     RECT  144.281 136.752 144.323 137.496 ;
     RECT  144.029 162.048 144.349 163.992 ;
     RECT  143.104 149.328 144.353 149.352 ;
     RECT  144.101 221.184 144.353 222.84 ;
     RECT  143.104 144.816 144.38 144.84 ;
     RECT  143.219 210.384 144.389 210.984 ;
     RECT  144.229 142.944 144.421 142.968 ;
     RECT  143.129 216.096 144.421 216.12 ;
     RECT  144.173 231.312 144.425 231.336 ;
     RECT  144.421 216.096 144.457 216.6 ;
     RECT  144.38 144.336 144.461 144.84 ;
     RECT  144.461 144.336 144.467 144.36 ;
     RECT  144.133 251.232 144.533 251.352 ;
     RECT  144.065 158.352 144.565 159.288 ;
     RECT  143.644 220.08 144.565 220.104 ;
     RECT  144.277 140.448 144.605 141.288 ;
     RECT  143.699 245.616 144.605 246.888 ;
     RECT  143.939 156.72 144.637 156.744 ;
     RECT  143.561 212.352 144.637 212.424 ;
     RECT  144.349 161.808 144.677 163.992 ;
     RECT  144.637 212.352 144.709 212.616 ;
     RECT  144.457 215.232 144.709 216.6 ;
     RECT  144.205 165.024 144.755 209.112 ;
     RECT  143.699 155.04 144.757 155.064 ;
     RECT  144.637 156.192 144.757 156.744 ;
     RECT  144.281 228.576 144.757 229.032 ;
     RECT  143.849 235.968 144.757 236.04 ;
     RECT  143.104 237.936 144.781 238.488 ;
     RECT  143.453 239.712 144.781 239.976 ;
     RECT  144.323 136.752 144.785 136.776 ;
     RECT  144.281 138.576 144.785 138.6 ;
     RECT  144.755 200.592 144.803 209.112 ;
     RECT  144.709 211.488 144.803 212.808 ;
     RECT  144.757 235.968 144.803 236.76 ;
     RECT  144.755 165.024 144.821 199.464 ;
     RECT  144.803 236.736 144.844 236.76 ;
     RECT  143.417 226.368 144.853 226.392 ;
     RECT  144.313 241.536 144.853 242.664 ;
     RECT  143.633 153.36 144.893 153.384 ;
     RECT  144.605 246.576 144.893 246.888 ;
     RECT  144.821 165.024 144.899 192.072 ;
     RECT  144.757 228.528 144.899 229.032 ;
     RECT  144.853 226.368 144.929 227.208 ;
     RECT  144.929 227.184 144.965 227.208 ;
     RECT  144.757 155.04 145.001 156.744 ;
     RECT  144.421 142.944 145.033 143.208 ;
     RECT  145.001 155.664 145.037 156.744 ;
     RECT  144.565 158.352 145.037 159.384 ;
     RECT  144.781 237.936 145.037 239.976 ;
     RECT  144.821 193.68 145.091 199.464 ;
     RECT  144.803 200.64 145.091 209.112 ;
     RECT  143.644 218.592 145.109 218.616 ;
     RECT  144.353 221.76 145.213 222.84 ;
     RECT  144.709 215.232 145.237 216.648 ;
     RECT  145.237 215.232 145.283 217.416 ;
     RECT  144.245 213.888 145.285 214.056 ;
     RECT  145.283 215.232 145.285 216.264 ;
     RECT  144.853 241.536 145.285 242.808 ;
     RECT  145.285 213.888 145.321 216.264 ;
     RECT  144.565 220.08 145.321 220.632 ;
     RECT  145.213 221.76 145.321 223.272 ;
     RECT  145.283 217.392 145.325 217.416 ;
     RECT  144.677 163.344 145.331 163.992 ;
     RECT  145.285 241.056 145.331 242.808 ;
     RECT  144.605 141.264 145.333 141.288 ;
     RECT  145.033 142.944 145.333 144.216 ;
     RECT  144.389 210.384 145.357 210.456 ;
     RECT  145.331 241.056 145.372 241.08 ;
     RECT  145.333 141.264 145.389 141.912 ;
     RECT  143.104 147.648 145.393 147.672 ;
     RECT  145.091 200.976 145.393 209.112 ;
     RECT  145.357 210.192 145.393 210.456 ;
     RECT  145.321 220.08 145.393 223.416 ;
     RECT  145.249 139.2 145.397 139.224 ;
     RECT  145.331 242.064 145.397 242.376 ;
     RECT  144.899 165.024 145.427 189.096 ;
     RECT  145.427 165.024 145.429 188.568 ;
     RECT  145.393 147.648 145.433 148.152 ;
     RECT  145.037 238.464 145.433 239.976 ;
     RECT  145.333 142.896 145.465 144.216 ;
     RECT  145.037 156.72 145.469 156.744 ;
     RECT  145.037 158.496 145.469 159.384 ;
     RECT  144.533 251.232 145.469 251.256 ;
     RECT  144.188 150.432 145.477 151.992 ;
     RECT  145.469 158.544 145.501 159.384 ;
     RECT  145.477 149.76 145.577 152.376 ;
     RECT  145.393 220.08 145.609 223.464 ;
     RECT  144.245 224.544 145.609 225.144 ;
     RECT  145.429 218.496 145.645 218.52 ;
     RECT  145.609 220.08 145.645 225.144 ;
     RECT  145.465 142.896 145.685 144.504 ;
     RECT  145.037 155.664 145.685 155.688 ;
     RECT  145.331 163.344 145.685 163.608 ;
     RECT  145.501 158.544 145.757 159.48 ;
     RECT  144.493 160.704 145.757 160.728 ;
     RECT  145.429 164.592 145.757 188.568 ;
     RECT  145.645 220.08 145.763 225.624 ;
     RECT  145.645 217.968 145.829 218.52 ;
     RECT  145.685 142.944 145.865 144.504 ;
     RECT  145.757 164.592 145.865 165.192 ;
     RECT  144.803 211.488 145.933 211.848 ;
     RECT  145.865 144.192 145.937 144.504 ;
     RECT  144.899 190.272 145.969 192.072 ;
     RECT  145.757 158.544 145.973 159.384 ;
     RECT  145.757 169.248 145.973 188.568 ;
     RECT  145.763 220.08 145.973 223.368 ;
     RECT  145.393 200.976 146.009 210.456 ;
     RECT  144.677 161.808 146.041 161.832 ;
     RECT  145.973 220.08 146.077 220.104 ;
     RECT  146.009 201.024 146.081 210.456 ;
     RECT  145.973 171.936 146.099 188.568 ;
     RECT  145.937 144.48 146.113 144.504 ;
     RECT  146.113 144.48 146.153 144.792 ;
     RECT  145.433 238.464 146.185 239.016 ;
     RECT  145.933 211.488 146.204 212.616 ;
     RECT  145.577 149.76 146.225 151.56 ;
     RECT  145.973 169.248 146.261 170.808 ;
     RECT  146.081 201.12 146.291 210.456 ;
     RECT  146.204 211.44 146.291 212.616 ;
     RECT  146.077 230.304 146.297 230.328 ;
     RECT  146.041 145.92 146.329 145.944 ;
     RECT  145.389 141.888 146.333 141.912 ;
     RECT  145.091 193.68 146.365 199.32 ;
     RECT  145.969 189.6 146.369 192.072 ;
     RECT  146.291 201.12 146.369 210.36 ;
     RECT  146.185 227.424 146.465 227.448 ;
     RECT  145.865 164.592 146.473 165.048 ;
     RECT  144.899 229.008 146.473 229.032 ;
     RECT  146.473 229.008 146.513 229.128 ;
     RECT  145.763 225.12 146.531 225.624 ;
     RECT  145.321 213.648 146.549 216.264 ;
     RECT  146.465 226.848 146.549 227.448 ;
     RECT  146.185 237.648 146.549 239.016 ;
     RECT  145.973 158.544 146.581 158.568 ;
     RECT  146.261 169.296 146.585 170.808 ;
     RECT  145.829 217.968 146.585 218.424 ;
     RECT  146.365 193.248 146.617 199.32 ;
     RECT  146.549 213.648 146.621 216.072 ;
     RECT  146.225 149.76 146.653 149.928 ;
     RECT  145.757 167.472 146.675 168.264 ;
     RECT  145.897 236.352 146.693 236.376 ;
     RECT  146.581 154.464 146.725 154.488 ;
     RECT  146.585 217.968 146.725 218.376 ;
     RECT  146.369 201.12 146.765 204.024 ;
     RECT  145.969 160.752 146.771 160.776 ;
     RECT  146.041 161.808 146.797 162.936 ;
     RECT  146.329 145.92 146.801 146.712 ;
     RECT  146.549 237.648 146.801 238.488 ;
     RECT  146.725 217.536 146.819 218.376 ;
     RECT  146.077 219.648 146.819 220.104 ;
     RECT  146.473 164.304 146.869 165.048 ;
     RECT  146.797 161.52 146.873 162.936 ;
     RECT  146.369 205.296 146.873 210.36 ;
     RECT  146.819 219.648 146.873 219.672 ;
     RECT  145.973 221.472 146.873 223.368 ;
     RECT  146.761 234.432 146.905 234.456 ;
     RECT  146.617 193.248 146.941 199.896 ;
     RECT  146.869 164.304 146.945 165.624 ;
     RECT  146.873 222.144 146.945 223.368 ;
     RECT  146.945 165.6 147.013 165.624 ;
     RECT  146.513 229.104 147.013 229.128 ;
     RECT  146.801 145.92 147.017 146.424 ;
     RECT  146.653 149.328 147.059 149.928 ;
     RECT  147.013 165.6 147.059 166.392 ;
     RECT  146.099 171.936 147.089 187.608 ;
     RECT  146.621 213.744 147.107 216.072 ;
     RECT  146.801 238.224 147.155 238.488 ;
     RECT  146.725 154.464 147.157 155.064 ;
     RECT  146.225 151.2 147.161 151.56 ;
     RECT  146.905 234.432 147.161 234.792 ;
     RECT  146.581 157.92 147.197 158.568 ;
     RECT  146.945 164.304 147.197 164.328 ;
     RECT  146.765 201.984 147.197 204.024 ;
     RECT  146.819 218.256 147.197 218.376 ;
     RECT  146.531 225.12 147.197 225.144 ;
     RECT  147.161 151.2 147.203 151.224 ;
     RECT  147.155 238.224 147.233 238.248 ;
     RECT  146.941 193.152 147.301 199.896 ;
     RECT  145.433 148.128 147.356 148.152 ;
     RECT  146.153 144.768 147.481 144.792 ;
     RECT  147.059 166.224 147.481 166.392 ;
     RECT  146.675 167.472 147.481 167.832 ;
     RECT  145.865 142.944 147.589 142.968 ;
     RECT  147.481 144.24 147.589 144.792 ;
     RECT  146.369 189.6 147.596 191.352 ;
     RECT  147.089 187.296 147.637 187.608 ;
     RECT  147.596 188.784 147.637 191.352 ;
     RECT  147.157 154.416 147.733 155.064 ;
     RECT  147.481 166.224 147.805 167.832 ;
     RECT  146.873 205.296 147.841 210.072 ;
     RECT  147.017 146.4 147.877 146.424 ;
     RECT  147.356 147.6 147.877 148.152 ;
     RECT  146.549 227.424 147.877 227.448 ;
     RECT  147.197 202.128 147.884 204.024 ;
     RECT  147.877 227.232 147.913 227.448 ;
     RECT  147.013 229.104 147.913 229.704 ;
     RECT  146.585 169.296 148.021 170.616 ;
     RECT  147.089 171.936 148.021 186.216 ;
     RECT  147.157 156.144 148.028 156.168 ;
     RECT  147.229 157.344 148.028 157.368 ;
     RECT  147.197 218.256 148.028 218.28 ;
     RECT  147.733 153.6 148.057 155.064 ;
     RECT  146.797 230.928 148.057 230.952 ;
     RECT  148.057 152.88 148.065 155.064 ;
     RECT  148.028 156.144 148.065 157.368 ;
     RECT  147.637 187.296 148.069 191.352 ;
     RECT  147.841 205.296 148.129 210.36 ;
     RECT  146.291 211.632 148.129 212.616 ;
     RECT  147.445 151.056 148.165 151.08 ;
     RECT  147.884 202.128 148.201 204.216 ;
     RECT  147.913 220.704 148.201 220.728 ;
     RECT  147.589 142.944 148.208 144.792 ;
     RECT  147.877 146.4 148.208 148.152 ;
     RECT  147.059 149.904 148.208 149.928 ;
     RECT  148.165 151.056 148.208 151.656 ;
     RECT  148.065 152.88 148.208 157.368 ;
     RECT  147.197 158.496 148.208 158.568 ;
     RECT  147.769 160.032 148.208 160.056 ;
     RECT  146.873 161.52 148.208 162.696 ;
     RECT  147.805 166.224 148.208 168.12 ;
     RECT  148.021 169.296 148.208 186.216 ;
     RECT  148.069 187.296 148.208 191.544 ;
     RECT  147.301 193.152 148.208 200.136 ;
     RECT  148.201 201.216 148.208 204.216 ;
     RECT  148.129 205.296 148.208 212.616 ;
     RECT  147.107 213.744 148.208 215.064 ;
     RECT  147.107 216.048 148.208 216.072 ;
     RECT  148.028 217.92 148.208 218.28 ;
     RECT  148.201 220.656 148.208 220.728 ;
     RECT  146.945 222.144 148.208 223.272 ;
     RECT  147.913 227.232 148.208 227.496 ;
     RECT  147.913 229.104 148.208 229.848 ;
     RECT  148.057 230.928 148.208 231.864 ;
     RECT  147.161 234.768 148.208 234.792 ;
     RECT  147.481 237.216 148.208 237.24 ;
     RECT  145.397 242.064 148.208 242.088 ;
     RECT  148.208 2.148 148.312 369.372 ;
     RECT  148.312 2.418 148.504 369.102 ;
     RECT  148.504 190.272 148.529 199.08 ;
     RECT  148.529 190.272 148.643 198.936 ;
     RECT  148.504 226.416 148.643 227.496 ;
     RECT  148.504 233.904 148.643 234.84 ;
     RECT  148.504 237.216 148.643 237.24 ;
     RECT  148.643 234.816 148.645 234.84 ;
     RECT  148.504 202.32 148.673 206.184 ;
     RECT  148.504 155.424 148.709 155.64 ;
     RECT  148.504 228.528 148.739 232.392 ;
     RECT  148.504 224.016 148.745 224.616 ;
     RECT  148.643 227.424 148.745 227.448 ;
     RECT  148.504 145.872 148.781 148.152 ;
     RECT  148.504 164.736 148.781 164.856 ;
     RECT  148.504 220.416 148.781 220.776 ;
     RECT  148.739 232.368 148.781 232.392 ;
     RECT  148.739 228.528 148.787 230.808 ;
     RECT  148.504 167.04 148.817 167.496 ;
     RECT  148.787 229.536 148.817 230.808 ;
     RECT  148.504 158.208 148.835 160.056 ;
     RECT  148.504 142.944 148.853 143.256 ;
     RECT  148.835 158.208 148.853 159.768 ;
     RECT  148.709 155.616 148.889 155.64 ;
     RECT  148.853 158.208 148.961 159.624 ;
     RECT  148.504 219.024 148.997 219.336 ;
     RECT  148.781 145.872 149.02 146.616 ;
     RECT  148.504 216.048 149.033 216.936 ;
     RECT  149.02 145.872 149.041 146.52 ;
     RECT  148.673 202.512 149.075 206.184 ;
     RECT  149.075 202.608 149.105 206.184 ;
     RECT  148.997 219.312 149.105 219.336 ;
     RECT  148.504 211.824 149.177 215.016 ;
     RECT  148.817 230.784 149.285 230.808 ;
     RECT  148.504 161.088 149.321 162.504 ;
     RECT  148.643 193.68 149.321 198.936 ;
     RECT  148.504 170.976 149.363 188.136 ;
     RECT  148.961 159.6 149.393 159.624 ;
     RECT  148.781 220.416 149.393 220.728 ;
     RECT  148.787 228.528 149.429 228.552 ;
     RECT  149.321 195.6 149.452 198.936 ;
     RECT  149.177 211.968 149.465 215.016 ;
     RECT  148.504 217.968 149.497 218.04 ;
     RECT  149.363 180.288 149.501 188.136 ;
     RECT  148.817 167.088 149.516 167.496 ;
     RECT  148.504 207.552 149.516 207.576 ;
     RECT  148.504 209.088 149.516 210.744 ;
     RECT  149.516 207.552 149.533 210.744 ;
     RECT  148.961 158.208 149.537 158.568 ;
     RECT  149.363 170.976 149.537 179.208 ;
     RECT  148.504 168.576 149.555 169.656 ;
     RECT  149.516 167.088 149.557 167.592 ;
     RECT  149.555 168.576 149.557 169.272 ;
     RECT  148.504 200.592 149.557 201.24 ;
     RECT  148.504 151.008 149.564 152.904 ;
     RECT  149.452 196.176 149.564 198.936 ;
     RECT  148.643 190.272 149.603 192.696 ;
     RECT  149.533 207.264 149.603 210.744 ;
     RECT  149.564 150.288 149.605 152.904 ;
     RECT  149.557 200.592 149.605 201.48 ;
     RECT  149.603 190.896 149.609 192.696 ;
     RECT  149.564 196.176 149.641 199.176 ;
     RECT  149.605 200.256 149.641 201.48 ;
     RECT  149.641 196.176 149.645 201.48 ;
     RECT  149.645 196.896 149.651 201.48 ;
     RECT  149.609 191.232 149.681 192.696 ;
     RECT  149.651 199.968 149.692 201.48 ;
     RECT  149.681 192.672 149.708 192.696 ;
     RECT  149.321 193.68 149.708 194.28 ;
     RECT  148.745 224.016 149.753 224.04 ;
     RECT  149.537 170.976 149.789 179.16 ;
     RECT  149.603 207.264 149.789 208.104 ;
     RECT  149.708 192.672 149.795 194.28 ;
     RECT  148.781 164.832 149.813 164.856 ;
     RECT  149.465 211.968 149.843 214.776 ;
     RECT  149.813 164.688 149.845 164.856 ;
     RECT  148.781 148.128 149.861 148.152 ;
     RECT  149.501 182.16 149.861 188.136 ;
     RECT  149.843 213.984 149.884 214.776 ;
     RECT  148.853 142.944 149.885 142.968 ;
     RECT  149.641 144.816 149.893 144.84 ;
     RECT  149.845 164.688 149.897 165.912 ;
     RECT  149.557 167.088 149.897 169.272 ;
     RECT  149.605 149.328 149.929 152.904 ;
     RECT  149.897 165.408 149.932 165.912 ;
     RECT  149.681 191.232 149.933 191.4 ;
     RECT  149.893 144.816 149.939 145.032 ;
     RECT  149.885 142.944 149.969 143.64 ;
     RECT  149.789 170.976 149.969 172.344 ;
     RECT  149.884 214.032 149.987 214.776 ;
     RECT  149.603 209.088 149.996 210.744 ;
     RECT  149.497 217.872 149.996 218.04 ;
     RECT  149.861 182.16 150.005 184.872 ;
     RECT  149.987 214.32 150.005 214.776 ;
     RECT  149.789 173.424 150.077 179.16 ;
     RECT  149.651 196.896 150.077 198.84 ;
     RECT  149.843 211.968 150.083 212.664 ;
     RECT  149.996 217.344 150.083 218.04 ;
     RECT  149.105 206.064 150.185 206.184 ;
     RECT  149.692 201.216 150.217 201.48 ;
     RECT  149.105 202.608 150.217 204.984 ;
     RECT  149.861 186.192 150.229 188.136 ;
     RECT  149.033 216.048 150.253 216.072 ;
     RECT  149.537 158.544 150.289 158.568 ;
     RECT  150.077 197.136 150.293 198.84 ;
     RECT  150.229 186.192 150.316 188.472 ;
     RECT  150.005 182.16 150.365 182.712 ;
     RECT  150.217 201.216 150.365 204.984 ;
     RECT  150.185 206.16 150.401 206.184 ;
     RECT  149.996 209.088 150.401 210.936 ;
     RECT  148.504 221.952 150.401 222.84 ;
     RECT  150.083 218.016 150.469 218.04 ;
     RECT  150.361 219.024 150.469 219.048 ;
     RECT  149.393 220.704 150.469 220.728 ;
     RECT  150.365 201.216 150.509 204.84 ;
     RECT  150.469 218.016 150.509 220.728 ;
     RECT  150.509 218.256 150.515 220.728 ;
     RECT  149.501 180.288 150.541 180.696 ;
     RECT  150.365 182.16 150.541 182.376 ;
     RECT  149.929 149.328 150.545 153.048 ;
     RECT  149.795 192.672 150.545 192.696 ;
     RECT  150.401 222.192 150.545 222.84 ;
     RECT  150.545 222.192 150.553 222.216 ;
     RECT  150.401 209.712 150.577 210.936 ;
     RECT  149.897 168 150.581 169.272 ;
     RECT  150.524 154.704 150.611 154.728 ;
     RECT  150.545 150.096 150.617 153.048 ;
     RECT  150.577 209.712 150.617 211.032 ;
     RECT  150.289 158.544 150.653 159.192 ;
     RECT  149.789 207.264 150.653 207.288 ;
     RECT  150.509 201.216 150.689 204.024 ;
     RECT  150.515 219.84 150.689 220.728 ;
     RECT  149.321 161.52 150.725 162.504 ;
     RECT  149.692 199.968 150.725 200.136 ;
     RECT  150.005 184.272 150.761 184.872 ;
     RECT  150.293 197.136 150.761 198.408 ;
     RECT  150.541 225.744 150.797 225.768 ;
     RECT  150.689 201.216 150.815 202.968 ;
     RECT  149.933 191.232 150.829 191.256 ;
     RECT  150.617 152.4 150.833 153.048 ;
     RECT  150.761 184.656 150.86 184.872 ;
     RECT  150.316 186.192 150.86 188.136 ;
     RECT  150.761 198.096 150.899 198.408 ;
     RECT  150.833 152.4 150.905 152.424 ;
     RECT  150.86 184.656 150.905 188.136 ;
     RECT  150.829 190.272 150.937 191.256 ;
     RECT  150.815 201.12 150.941 202.968 ;
     RECT  150.905 184.656 150.947 186.408 ;
     RECT  149.969 171.456 150.973 172.344 ;
     RECT  150.077 173.424 150.973 173.736 ;
     RECT  150.515 218.256 150.977 218.28 ;
     RECT  150.253 216.048 151.01 216.648 ;
     RECT  150.541 180.144 151.013 182.376 ;
     RECT  150.947 184.656 151.085 185.16 ;
     RECT  150.941 201.12 151.085 202.92 ;
     RECT  150.617 150.096 151.121 151.032 ;
     RECT  150.617 210 151.157 211.032 ;
     RECT  150.725 161.904 151.193 162.504 ;
     RECT  151.013 180.144 151.193 181.272 ;
     RECT  150.905 187.536 151.193 188.136 ;
     RECT  150.937 190.272 151.193 191.976 ;
     RECT  150.689 219.84 151.193 219.864 ;
     RECT  150.725 200.112 151.225 200.136 ;
     RECT  151.085 201.12 151.225 201.576 ;
     RECT  150.083 212.64 151.225 212.664 ;
     RECT  151.225 212.64 151.237 212.712 ;
     RECT  150.973 171.456 151.292 173.736 ;
     RECT  151.237 212.304 151.309 212.712 ;
     RECT  151.292 171.456 151.333 173.832 ;
     RECT  150.077 174.912 151.333 179.16 ;
     RECT  151.193 188.112 151.337 188.136 ;
     RECT  149.041 146.4 151.369 146.424 ;
     RECT  151.309 212.304 151.373 212.664 ;
     RECT  151.34 189.6 151.381 189.624 ;
     RECT  150.653 158.544 151.405 158.904 ;
     RECT  150.853 195.744 151.405 195.768 ;
     RECT  149.932 165.408 151.409 165.576 ;
     RECT  151.381 188.256 151.427 189.624 ;
     RECT  151.297 166.896 151.429 166.92 ;
     RECT  150.581 168 151.429 168.648 ;
     RECT  151.261 170.16 151.441 170.184 ;
     RECT  151.441 170.16 151.475 170.232 ;
     RECT  151.333 171.456 151.475 179.16 ;
     RECT  151.193 191.232 151.517 191.976 ;
     RECT  151.121 151.008 151.553 151.032 ;
     RECT  151.085 202.848 151.553 202.872 ;
     RECT  151.405 158.448 151.621 158.904 ;
     RECT  151.429 166.896 151.657 168.648 ;
     RECT  149.939 145.008 151.667 145.032 ;
     RECT  151.009 160.56 151.667 160.584 ;
     RECT  151.333 163.008 151.667 163.032 ;
     RECT  151.157 210.288 151.669 211.032 ;
     RECT  151.373 212.304 151.669 212.328 ;
     RECT  151.405 195.744 151.693 195.96 ;
     RECT  151.621 158.448 151.708 159.528 ;
     RECT  151.669 210.288 151.715 212.328 ;
     RECT  149.795 194.16 151.729 194.28 ;
     RECT  151.369 146.4 151.733 147.048 ;
     RECT  151.085 185.136 151.733 185.16 ;
     RECT  150.899 198.384 151.733 198.408 ;
     RECT  151.715 211.2 151.756 212.328 ;
     RECT  150.649 232.944 151.765 232.968 ;
     RECT  150.565 156.192 151.805 156.216 ;
     RECT  151.724 163.824 151.811 163.848 ;
     RECT  151.756 212.016 151.841 212.328 ;
     RECT  151.193 180.144 151.877 180.6 ;
     RECT  151.733 147.024 151.907 147.048 ;
     RECT  151.693 195.744 151.909 196.776 ;
     RECT  151.657 166.08 151.945 168.648 ;
     RECT  150.947 186.192 151.949 186.408 ;
     RECT  151.405 214.848 151.981 214.872 ;
     RECT  150.145 234.72 152.021 234.744 ;
     RECT  151.441 164.928 152.051 164.952 ;
     RECT  151.945 166.08 152.051 168.696 ;
     RECT  150.613 157.248 152.053 157.272 ;
     RECT  151.909 195.744 152.053 197.208 ;
     RECT  152.051 166.08 152.092 166.248 ;
     RECT  152.012 199.008 152.099 199.032 ;
     RECT  152.053 195.744 152.14 197.88 ;
     RECT  151.765 232.944 152.149 233.448 ;
     RECT  151.517 191.232 152.161 191.88 ;
     RECT  151.01 216.048 152.161 216.6 ;
     RECT  151.873 217.824 152.161 217.848 ;
     RECT  151.225 200.112 152.237 201.576 ;
     RECT  152.161 216.048 152.243 217.848 ;
     RECT  152.149 232.512 152.256 233.448 ;
     RECT  152.051 168 152.273 168.696 ;
     RECT  151.427 188.256 152.273 188.664 ;
     RECT  152.197 219.024 152.284 219.048 ;
     RECT  151.549 223.968 152.291 223.992 ;
     RECT  152.053 156.72 152.293 157.272 ;
     RECT  151.708 158.448 152.293 158.568 ;
     RECT  152.237 200.16 152.309 201.576 ;
     RECT  152.245 224.976 152.332 225.528 ;
     RECT  151.729 193.632 152.341 194.28 ;
     RECT  152.14 195.744 152.341 197.064 ;
     RECT  152.161 191.04 152.345 191.88 ;
     RECT  152.197 164.736 152.381 164.76 ;
     RECT  148.817 229.536 152.453 229.56 ;
     RECT  152.341 193.632 152.485 197.064 ;
     RECT  152.125 181.584 152.525 181.608 ;
     RECT  151.193 161.904 152.593 161.928 ;
     RECT  152.293 156.72 152.633 158.568 ;
     RECT  151.475 171.744 152.665 179.16 ;
     RECT  151.877 180.144 152.665 180.504 ;
     RECT  152.633 158.544 152.725 158.568 ;
     RECT  152.701 181.776 152.737 181.8 ;
     RECT  152.309 201.552 152.737 201.576 ;
     RECT  152.737 181.776 152.881 181.944 ;
     RECT  151.949 186.192 152.989 186.216 ;
     RECT  151.841 212.016 153.133 212.04 ;
     RECT  152.593 161.616 153.241 161.928 ;
     RECT  151.475 170.208 153.277 170.232 ;
     RECT  152.485 193.104 153.277 197.064 ;
     RECT  152.665 171.744 153.313 180.504 ;
     RECT  152.273 168 153.385 168.024 ;
     RECT  153.277 169.392 153.385 170.232 ;
     RECT  153.313 171.552 153.385 180.504 ;
     RECT  152.092 166.08 153.457 166.104 ;
     RECT  153.385 168 153.493 170.232 ;
     RECT  153.385 171.264 153.493 180.504 ;
     RECT  153.241 161.616 153.565 162.744 ;
     RECT  150.689 204 153.565 204.024 ;
     RECT  151.861 154.224 153.608 154.248 ;
     RECT  152.633 156.72 153.608 157.512 ;
     RECT  152.725 158.544 153.608 159.384 ;
     RECT  153.565 161.616 153.608 162.936 ;
     RECT  153.457 165.888 153.608 166.104 ;
     RECT  153.493 168 153.608 180.504 ;
     RECT  152.881 181.776 153.608 182.424 ;
     RECT  153.349 183.696 153.608 183.72 ;
     RECT  152.989 185.328 153.608 186.216 ;
     RECT  152.273 188.256 153.608 188.28 ;
     RECT  152.345 191.04 153.608 191.352 ;
     RECT  153.277 192.672 153.608 197.064 ;
     RECT  152.309 200.16 153.608 200.184 ;
     RECT  152.737 201.552 153.608 201.816 ;
     RECT  153.565 203.232 153.608 204.024 ;
     RECT  151.117 207.84 153.608 207.864 ;
     RECT  152.845 209.856 153.608 210.12 ;
     RECT  153.133 212.016 153.608 212.088 ;
     RECT  153.025 213.072 153.608 213.096 ;
     RECT  151.981 214.512 153.608 214.872 ;
     RECT  152.243 216.048 153.608 217.32 ;
     RECT  151.477 221.184 153.608 221.208 ;
     RECT  153.097 223.632 153.608 223.656 ;
     RECT  152.332 225.504 153.608 225.528 ;
     RECT  152.593 228.96 153.608 228.984 ;
     RECT  151.765 231.264 153.608 231.288 ;
     RECT  152.256 232.512 153.608 232.536 ;
     RECT  153.608 2.148 153.712 369.372 ;
     RECT  153.712 2.418 153.904 369.102 ;
     RECT  153.904 209.856 153.929 212.088 ;
     RECT  153.904 201.456 153.965 201.816 ;
     RECT  153.904 192.384 154.019 193.944 ;
     RECT  153.904 217.92 154.019 218.568 ;
     RECT  153.904 221.184 154.019 221.208 ;
     RECT  153.904 203.232 154.073 203.64 ;
     RECT  153.904 195.888 154.109 196.584 ;
     RECT  154.019 217.92 154.153 218.328 ;
     RECT  154.073 203.52 154.325 203.64 ;
     RECT  153.904 165.072 154.397 166.44 ;
     RECT  153.904 222.336 154.397 222.6 ;
     RECT  153.904 155.712 154.403 156.744 ;
     RECT  153.904 170.208 154.433 173.448 ;
     RECT  154.019 192.384 154.433 192.648 ;
     RECT  154.403 155.712 154.444 156.216 ;
     RECT  153.904 190.464 154.469 191.352 ;
     RECT  154.433 192.384 154.469 192.504 ;
     RECT  153.904 154.224 154.505 154.248 ;
     RECT  153.904 213.6 154.505 216.216 ;
     RECT  153.904 182.4 154.541 183.72 ;
     RECT  154.433 171.072 154.577 173.448 ;
     RECT  153.929 210.816 154.613 212.088 ;
     RECT  154.153 217.92 154.613 218.136 ;
     RECT  154.109 196.56 154.649 196.584 ;
     RECT  154.397 165.072 154.685 166.2 ;
     RECT  153.904 207.264 154.685 207.432 ;
     RECT  153.904 158.256 154.721 159.384 ;
     RECT  153.904 163.968 154.721 163.992 ;
     RECT  154.685 165.072 154.829 165.288 ;
     RECT  154.469 192.384 154.865 192.408 ;
     RECT  153.904 204.96 154.865 205.896 ;
     RECT  154.541 182.4 154.901 182.952 ;
     RECT  154.685 207.264 154.901 207.288 ;
     RECT  154.865 204.96 154.973 205.272 ;
     RECT  154.469 190.944 155.045 191.352 ;
     RECT  153.904 162.624 155.077 162.936 ;
     RECT  154.973 205.056 155.081 205.272 ;
     RECT  154.721 158.352 155.117 159.384 ;
     RECT  155.081 205.056 155.153 205.176 ;
     RECT  154.505 216.048 155.185 216.216 ;
     RECT  153.904 199.104 155.261 199.128 ;
     RECT  153.904 160.992 155.293 161.016 ;
     RECT  155.077 162.48 155.293 162.936 ;
     RECT  154.577 171.504 155.297 173.448 ;
     RECT  155.293 160.992 155.333 162.936 ;
     RECT  155.297 171.504 155.333 171.624 ;
     RECT  154.444 156.192 155.369 156.216 ;
     RECT  155.333 160.992 155.377 161.88 ;
     RECT  154.019 193.92 155.401 193.944 ;
     RECT  154.613 212.064 155.401 212.088 ;
     RECT  154.505 213.6 155.405 214.488 ;
     RECT  155.297 173.184 155.437 173.448 ;
     RECT  153.904 174.768 155.437 181.416 ;
     RECT  154.897 189.36 155.437 189.384 ;
     RECT  155.401 193.776 155.441 193.944 ;
     RECT  155.221 197.856 155.441 197.88 ;
     RECT  155.401 212.064 155.441 212.568 ;
     RECT  155.441 212.4 155.461 212.568 ;
     RECT  155.405 213.6 155.461 214.344 ;
     RECT  155.045 190.944 155.477 191.304 ;
     RECT  155.437 173.184 155.549 181.416 ;
     RECT  155.117 159.024 155.605 159.384 ;
     RECT  155.437 226.704 155.617 226.728 ;
     RECT  155.605 159.024 155.651 160.968 ;
     RECT  153.904 167.712 155.653 168.024 ;
     RECT  154.613 217.92 155.657 217.944 ;
     RECT  154.969 222.672 155.657 222.696 ;
     RECT  155.437 189.36 155.693 189.48 ;
     RECT  155.437 221.184 155.725 221.208 ;
     RECT  155.617 226.704 155.725 227.304 ;
     RECT  155.651 159.36 155.729 160.968 ;
     RECT  155.401 196.368 155.761 196.44 ;
     RECT  155.549 180.288 155.801 181.416 ;
     RECT  155.761 196.368 155.801 196.536 ;
     RECT  155.153 205.152 155.801 205.176 ;
     RECT  155.725 226.368 155.837 227.304 ;
     RECT  155.801 196.416 155.873 196.536 ;
     RECT  155.837 226.368 155.873 226.968 ;
     RECT  155.333 162.912 155.909 162.936 ;
     RECT  155.333 171.6 155.909 171.624 ;
     RECT  153.965 201.456 155.941 201.48 ;
     RECT  154.325 203.52 156.085 203.544 ;
     RECT  155.461 212.4 156.089 214.344 ;
     RECT  155.365 206.352 156.121 206.376 ;
     RECT  156.089 213.792 156.125 214.344 ;
     RECT  155.873 226.512 156.125 226.968 ;
     RECT  156.121 205.824 156.133 206.376 ;
     RECT  155.873 196.416 156.161 196.44 ;
     RECT  156.085 207.504 156.179 207.528 ;
     RECT  156.089 212.4 156.179 212.664 ;
     RECT  156.085 203.52 156.181 204.072 ;
     RECT  155.653 167.712 156.197 168.696 ;
     RECT  155.797 183.408 156.197 183.432 ;
     RECT  154.613 210.816 156.197 210.84 ;
     RECT  156.121 166.176 156.205 166.2 ;
     RECT  156.181 203.52 156.227 204.744 ;
     RECT  156.133 205.824 156.227 206.52 ;
     RECT  155.653 209.712 156.229 209.736 ;
     RECT  154.829 165.072 156.233 165.096 ;
     RECT  156.125 226.608 156.233 226.92 ;
     RECT  156.227 204.72 156.269 204.744 ;
     RECT  156.229 209.712 156.269 210.36 ;
     RECT  156.233 226.608 156.269 226.728 ;
     RECT  155.185 216.048 156.301 216.648 ;
     RECT  156.125 214.32 156.305 214.344 ;
     RECT  156.197 167.712 156.341 167.736 ;
     RECT  155.941 201.456 156.341 201.768 ;
     RECT  156.269 226.704 156.341 226.728 ;
     RECT  153.904 185.328 156.373 186.36 ;
     RECT  156.373 185.232 156.377 186.36 ;
     RECT  155.941 189.024 156.38 189.048 ;
     RECT  155.725 220.8 156.409 221.208 ;
     RECT  156.301 216.048 156.419 216.696 ;
     RECT  155.477 190.944 156.445 191.256 ;
     RECT  156.409 220.8 156.445 221.496 ;
     RECT  156.179 212.64 156.449 212.664 ;
     RECT  156.38 188.448 156.467 189.048 ;
     RECT  156.269 210.336 156.467 210.36 ;
     RECT  156.377 185.232 156.485 185.256 ;
     RECT  155.549 173.184 156.517 179.16 ;
     RECT  156.517 173.04 156.521 179.16 ;
     RECT  156.227 203.52 156.521 203.544 ;
     RECT  156.341 201.456 156.593 201.48 ;
     RECT  156.301 198.384 156.665 198.408 ;
     RECT  156.419 216.048 156.733 216.648 ;
     RECT  156.521 173.04 156.737 173.448 ;
     RECT  156.445 190.56 156.737 191.256 ;
     RECT  156.445 220.8 156.737 221.736 ;
     RECT  156.733 215.808 156.773 216.648 ;
     RECT  154.933 154.272 156.803 154.296 ;
     RECT  156.085 163.776 156.845 163.8 ;
     RECT  156.737 221.472 156.845 221.736 ;
     RECT  156.769 168.72 156.881 168.936 ;
     RECT  155.441 193.776 156.913 193.8 ;
     RECT  156.845 221.472 156.989 221.496 ;
     RECT  156.157 218.256 157.052 218.28 ;
     RECT  155.845 219.456 157.052 219.48 ;
     RECT  156.913 193.632 157.057 193.8 ;
     RECT  156.737 173.184 157.097 173.448 ;
     RECT  157.057 157.536 157.129 158.088 ;
     RECT  156.913 196.608 157.133 196.632 ;
     RECT  157.052 218.256 157.139 219.48 ;
     RECT  157.129 157.536 157.201 158.424 ;
     RECT  156.757 155.616 157.205 155.64 ;
     RECT  157.093 204.96 157.205 204.984 ;
     RECT  155.729 159.648 157.237 160.2 ;
     RECT  156.445 171.024 157.237 171.48 ;
     RECT  156.737 190.752 157.241 191.256 ;
     RECT  157.139 218.256 157.241 218.856 ;
     RECT  157.057 193.536 157.273 193.8 ;
     RECT  157.201 194.832 157.273 194.856 ;
     RECT  157.237 171.024 157.285 171.72 ;
     RECT  157.285 170.976 157.331 171.72 ;
     RECT  156.881 168.912 157.333 168.936 ;
     RECT  157.273 201.408 157.333 201.432 ;
     RECT  156.773 215.808 157.349 216.408 ;
     RECT  157.333 168.912 157.379 169.896 ;
     RECT  157.333 200.592 157.379 201.432 ;
     RECT  157.34 156.432 157.381 156.456 ;
     RECT  157.201 157.536 157.381 158.472 ;
     RECT  157.237 159.6 157.385 160.2 ;
     RECT  157.381 156.432 157.427 158.568 ;
     RECT  157.385 159.6 157.427 159.624 ;
     RECT  157.427 157.344 157.468 158.568 ;
     RECT  157.309 198.336 157.477 198.36 ;
     RECT  157.379 200.592 157.493 200.664 ;
     RECT  157.436 199.536 157.523 199.56 ;
     RECT  157.468 157.344 157.529 158.088 ;
     RECT  156.877 189.216 157.565 189.24 ;
     RECT  155.801 180.288 157.597 180.552 ;
     RECT  157.477 197.04 157.709 198.36 ;
     RECT  157.273 193.536 157.745 194.856 ;
     RECT  157.349 215.808 157.745 215.832 ;
     RECT  157.745 194.784 157.781 194.856 ;
     RECT  157.379 169.872 157.853 169.896 ;
     RECT  157.745 193.536 157.853 193.656 ;
     RECT  157.097 173.184 157.925 173.208 ;
     RECT  157.709 197.04 157.925 197.544 ;
     RECT  156.227 206.496 157.957 206.52 ;
     RECT  157.331 170.976 157.961 171 ;
     RECT  157.781 194.784 157.961 194.808 ;
     RECT  157.957 206.496 157.993 207.336 ;
     RECT  157.529 158.064 157.997 158.088 ;
     RECT  157.993 206.4 158.029 207.336 ;
     RECT  157.777 202.128 158.033 202.152 ;
     RECT  158.029 205.92 158.053 207.336 ;
     RECT  157.241 190.752 158.156 190.776 ;
     RECT  158.053 205.92 158.245 207.528 ;
     RECT  157.885 204.432 158.353 204.456 ;
     RECT  158.353 203.472 158.54 204.456 ;
     RECT  156.521 174.768 159.008 179.16 ;
     RECT  157.597 180.288 159.008 180.6 ;
     RECT  157.993 185.28 159.008 185.304 ;
     RECT  156.377 186.336 159.008 186.36 ;
     RECT  158.156 190.032 159.008 190.776 ;
     RECT  157.853 193.632 159.008 193.656 ;
     RECT  157.925 197.52 159.008 197.544 ;
     RECT  157.493 200.64 159.008 200.664 ;
     RECT  158.54 202.32 159.008 204.456 ;
     RECT  158.245 205.92 159.008 208.056 ;
     RECT  157.241 218.832 159.008 218.856 ;
     RECT  157.273 219.888 159.008 219.912 ;
     RECT  159.008 2.148 159.112 369.372 ;
     RECT  159.112 2.418 159.304 369.102 ;
     RECT  159.304 207.168 159.329 207.192 ;
     RECT  159.304 210.96 159.365 210.984 ;
     RECT  159.304 190.752 159.869 190.776 ;
     RECT  159.304 174.768 164.408 176.376 ;
     RECT  159.304 177.552 164.408 179.16 ;
     RECT  159.304 180.288 164.408 180.312 ;
     RECT  159.304 186.336 164.408 186.36 ;
     RECT  164.408 2.148 164.512 369.372 ;
     RECT  164.512 2.418 164.704 369.102 ;
     RECT  164.704 174.768 169.808 176.424 ;
     RECT  164.704 177.552 169.808 179.16 ;
     RECT  164.704 180.288 169.808 180.312 ;
     RECT  164.704 186.336 169.808 186.36 ;
     RECT  169.808 2.148 169.912 369.372 ;
     RECT  169.912 2.418 170.104 369.102 ;
     RECT  170.104 174.768 175.208 176.424 ;
     RECT  170.104 177.552 175.208 179.16 ;
     RECT  170.104 180.288 175.208 180.312 ;
     RECT  170.104 186.336 175.208 186.36 ;
     RECT  175.208 2.148 175.312 369.372 ;
     RECT  175.312 2.418 175.504 369.102 ;
     RECT  175.504 174.768 180.608 176.424 ;
     RECT  175.504 177.552 180.608 179.16 ;
     RECT  175.504 180.288 180.608 180.312 ;
     RECT  175.504 186.336 180.608 186.36 ;
     RECT  180.608 2.148 180.712 369.372 ;
     RECT  180.712 2.418 180.904 369.102 ;
     RECT  180.904 174.768 186.008 176.424 ;
     RECT  180.904 177.552 186.008 179.16 ;
     RECT  180.904 180.288 186.008 180.312 ;
     RECT  180.904 186.336 186.008 186.36 ;
     RECT  186.008 2.148 186.112 369.372 ;
     RECT  186.112 2.418 186.304 369.102 ;
     RECT  186.304 174.768 191.408 176.424 ;
     RECT  186.304 177.552 191.408 179.16 ;
     RECT  186.304 180.288 191.408 180.312 ;
     RECT  186.304 186.336 191.408 186.36 ;
     RECT  191.408 2.148 191.512 369.372 ;
     RECT  191.512 2.418 191.704 369.102 ;
     RECT  191.704 174.768 196.808 176.424 ;
     RECT  191.704 177.552 196.808 179.16 ;
     RECT  191.704 180.288 196.808 180.312 ;
     RECT  191.704 186.336 196.808 186.36 ;
     RECT  196.808 2.148 196.912 369.372 ;
     RECT  196.912 2.418 197.104 369.102 ;
     RECT  197.104 174.768 202.208 176.424 ;
     RECT  197.104 177.552 202.208 179.16 ;
     RECT  197.104 180.288 202.208 180.312 ;
     RECT  197.104 186.336 202.208 186.36 ;
     RECT  202.208 2.148 202.312 369.372 ;
     RECT  202.312 2.418 202.504 369.102 ;
     RECT  202.504 174.768 207.608 176.424 ;
     RECT  202.504 177.552 207.608 179.16 ;
     RECT  202.504 180.288 207.608 180.312 ;
     RECT  202.504 186.336 207.608 186.36 ;
     RECT  207.608 2.148 207.712 369.372 ;
     RECT  207.712 2.418 207.904 369.102 ;
     RECT  207.904 174.768 213.008 176.424 ;
     RECT  207.904 177.552 213.008 179.16 ;
     RECT  207.904 180.288 213.008 180.312 ;
     RECT  207.904 186.336 213.008 186.36 ;
     RECT  213.008 2.148 213.112 369.372 ;
     RECT  213.112 2.418 213.304 369.102 ;
     RECT  213.304 174.768 218.408 176.424 ;
     RECT  213.304 177.552 218.408 179.16 ;
     RECT  213.304 180.288 218.408 180.312 ;
     RECT  213.304 186.336 218.408 186.36 ;
     RECT  218.408 2.148 218.512 369.372 ;
     RECT  218.512 2.418 218.704 369.102 ;
     RECT  218.704 174.768 223.808 176.424 ;
     RECT  218.704 177.552 223.808 179.16 ;
     RECT  218.704 180.288 223.808 180.312 ;
     RECT  218.704 186.336 223.808 186.36 ;
     RECT  223.808 2.148 223.912 369.372 ;
     RECT  223.912 2.418 224.104 369.102 ;
     RECT  224.104 174.768 229.208 176.424 ;
     RECT  224.104 177.552 229.208 179.16 ;
     RECT  224.104 180.288 229.208 180.312 ;
     RECT  224.104 186.336 229.208 186.36 ;
     RECT  229.208 2.148 229.312 369.372 ;
     RECT  229.312 2.418 229.504 369.102 ;
     RECT  229.504 174.768 234.608 176.424 ;
     RECT  229.504 177.552 234.608 179.16 ;
     RECT  229.504 180.288 234.608 180.312 ;
     RECT  229.504 186.336 234.608 186.36 ;
     RECT  234.608 2.148 234.712 369.372 ;
     RECT  234.712 2.418 234.904 369.102 ;
     RECT  234.904 174.768 240.008 176.424 ;
     RECT  234.904 177.552 240.008 179.16 ;
     RECT  234.904 180.288 240.008 180.312 ;
     RECT  234.904 186.336 240.008 186.36 ;
     RECT  240.008 2.148 240.112 369.372 ;
     RECT  240.112 2.418 240.304 369.102 ;
     RECT  240.304 174.768 243.497 176.424 ;
     RECT  243.497 174.768 243.641 176.376 ;
     RECT  240.304 180.288 243.857 180.312 ;
     RECT  240.304 177.552 244.181 179.16 ;
     RECT  240.304 186.336 244.181 186.36 ;
     RECT  243.641 174.768 244.253 175.992 ;
     RECT  244.181 178.8 245.005 179.16 ;
     RECT  244.253 174.768 245.408 174.84 ;
     RECT  244.253 175.968 245.408 175.992 ;
     RECT  244.181 177.552 245.408 177.576 ;
     RECT  245.005 178.8 245.408 179.928 ;
     RECT  245.408 2.148 245.512 369.372 ;
     RECT  245.512 2.418 245.704 369.102 ;
     RECT  245.704 176.688 246.805 180.264 ;
     RECT  246.805 176.592 247.381 180.264 ;
     RECT  247.381 176.592 248.364 180.36 ;
    LAYER M5 ;
     RECT  2.4 2.137 2.52 2.151 ;
     RECT  7.8 2.137 7.92 2.151 ;
     RECT  13.2 2.137 13.32 2.151 ;
     RECT  18.6 2.137 18.72 2.151 ;
     RECT  24 2.137 24.12 2.151 ;
     RECT  29.4 2.137 29.52 2.151 ;
     RECT  34.8 2.137 34.92 2.151 ;
     RECT  40.2 2.137 40.32 2.151 ;
     RECT  45.6 2.137 45.72 2.151 ;
     RECT  51 2.137 51.12 2.151 ;
     RECT  56.4 2.137 56.52 2.151 ;
     RECT  61.8 2.137 61.92 2.151 ;
     RECT  67.2 2.137 67.32 2.151 ;
     RECT  72.6 2.137 72.72 2.151 ;
     RECT  78 2.137 78.12 2.151 ;
     RECT  83.4 2.137 83.52 2.151 ;
     RECT  88.8 2.137 88.92 2.151 ;
     RECT  94.2 2.137 94.32 2.151 ;
     RECT  99.6 2.137 99.72 2.151 ;
     RECT  105 2.137 105.12 2.151 ;
     RECT  110.4 2.137 110.52 2.151 ;
     RECT  115.8 2.137 115.92 2.151 ;
     RECT  121.2 2.137 121.32 2.151 ;
     RECT  126.6 2.137 126.72 2.151 ;
     RECT  132 2.137 132.12 2.151 ;
     RECT  137.4 2.137 137.52 2.151 ;
     RECT  142.8 2.137 142.92 2.151 ;
     RECT  148.2 2.137 148.32 2.151 ;
     RECT  153.6 2.137 153.72 2.151 ;
     RECT  159 2.137 159.12 2.151 ;
     RECT  164.4 2.137 164.52 2.151 ;
     RECT  169.8 2.137 169.92 2.151 ;
     RECT  175.2 2.137 175.32 2.151 ;
     RECT  180.6 2.137 180.72 2.151 ;
     RECT  186 2.137 186.12 2.151 ;
     RECT  191.4 2.137 191.52 2.151 ;
     RECT  196.8 2.137 196.92 2.151 ;
     RECT  202.2 2.137 202.32 2.151 ;
     RECT  207.6 2.137 207.72 2.151 ;
     RECT  213 2.137 213.12 2.151 ;
     RECT  218.4 2.137 218.52 2.151 ;
     RECT  223.8 2.137 223.92 2.151 ;
     RECT  229.2 2.137 229.32 2.151 ;
     RECT  234.6 2.137 234.72 2.151 ;
     RECT  240 2.137 240.12 2.151 ;
     RECT  245.4 2.137 245.52 2.151 ;
     RECT  137.4 2.151 137.712 134.485 ;
     RECT  137.4 134.485 138.12 135.157 ;
     RECT  137.4 135.157 138.504 135.683 ;
     RECT  142.8 2.151 143.112 136.213 ;
     RECT  140.88 135.637 140.904 136.787 ;
     RECT  144.288 136.741 144.312 137.507 ;
     RECT  137.4 135.683 137.712 137.893 ;
     RECT  136.272 137.605 136.296 138.467 ;
     RECT  137.4 137.893 138.408 138.517 ;
     RECT  139.584 137.893 139.608 138.517 ;
     RECT  137.4 138.517 139.608 138.563 ;
     RECT  142.704 136.213 143.112 138.611 ;
     RECT  141.456 137.605 141.48 139.189 ;
     RECT  141.072 139.189 141.48 139.235 ;
     RECT  142.8 138.611 143.112 140.437 ;
     RECT  144.24 137.893 144.264 140.437 ;
     RECT  141.072 139.235 141.096 140.533 ;
     RECT  141.072 140.533 141.576 140.627 ;
     RECT  137.4 138.563 139.128 140.819 ;
     RECT  137.4 140.819 138.408 141.395 ;
     RECT  141.552 140.627 141.576 141.829 ;
     RECT  142.8 140.437 144.264 142.355 ;
     RECT  144.24 142.355 144.264 142.979 ;
     RECT  137.4 141.395 137.832 143.029 ;
     RECT  141.552 141.829 141.816 143.123 ;
     RECT  145.344 141.253 145.368 143.173 ;
     RECT  144.432 143.173 145.368 143.219 ;
     RECT  135.6 138.949 135.624 143.269 ;
     RECT  148.2 2.151 148.512 143.269 ;
     RECT  135.6 143.269 135.816 143.315 ;
     RECT  144.432 143.219 144.456 144.181 ;
     RECT  141.792 143.123 141.816 144.227 ;
     RECT  147.6 143.269 148.512 144.275 ;
     RECT  144.432 144.181 145.896 144.371 ;
     RECT  137.4 143.029 137.976 144.515 ;
     RECT  134.304 137.029 134.328 144.613 ;
     RECT  149.904 143.605 149.928 145.043 ;
     RECT  135.792 143.315 135.816 145.091 ;
     RECT  134.16 144.613 134.328 145.379 ;
     RECT  141.264 144.757 141.288 145.861 ;
     RECT  142.8 142.355 143.112 145.861 ;
     RECT  148.2 144.275 148.512 145.861 ;
     RECT  141.264 145.861 143.112 145.907 ;
     RECT  134.304 145.379 134.328 146.149 ;
     RECT  139.104 145.861 139.128 146.293 ;
     RECT  139.104 146.293 139.608 146.483 ;
     RECT  139.104 146.483 139.128 146.531 ;
     RECT  148.2 145.861 149.016 146.531 ;
     RECT  134.304 146.149 134.808 146.675 ;
     RECT  151.632 144.997 151.656 147.013 ;
     RECT  151.632 147.013 151.896 147.059 ;
     RECT  134.784 146.675 134.808 147.061 ;
     RECT  134.784 147.061 135.096 147.107 ;
     RECT  147.168 146.389 147.192 147.589 ;
     RECT  148.2 146.531 148.968 147.589 ;
     RECT  147.168 147.589 148.968 148.163 ;
     RECT  141.888 145.907 143.112 148.165 ;
     RECT  135.072 147.107 135.096 148.259 ;
     RECT  141.024 148.165 143.112 148.835 ;
     RECT  137.4 144.515 137.832 149.317 ;
     RECT  145.2 144.371 145.896 149.317 ;
     RECT  147.168 148.163 147.192 149.317 ;
     RECT  147.024 149.317 147.192 149.939 ;
     RECT  132 2.151 132.312 150.421 ;
     RECT  141.888 148.835 143.112 150.421 ;
     RECT  135.648 149.413 135.672 150.467 ;
     RECT  144.24 149.317 145.896 150.467 ;
     RECT  145.2 150.467 145.896 150.709 ;
     RECT  141.12 150.421 143.112 150.901 ;
     RECT  131.472 150.421 132.312 150.997 ;
     RECT  147.168 149.939 147.192 151.235 ;
     RECT  149.616 149.317 149.64 151.331 ;
     RECT  133.92 149.845 133.944 151.427 ;
     RECT  140.832 150.901 143.112 151.525 ;
     RECT  137.4 149.317 138.6 151.573 ;
     RECT  148.2 148.163 148.512 151.621 ;
     RECT  131.088 150.997 132.312 152.819 ;
     RECT  148.2 151.621 148.776 152.867 ;
     RECT  150.432 152.101 150.456 153.013 ;
     RECT  150.432 153.013 150.6 153.059 ;
     RECT  136.512 151.573 138.6 153.539 ;
     RECT  148.2 152.867 148.512 153.877 ;
     RECT  151.872 147.059 151.896 154.259 ;
     RECT  136.512 153.539 137.712 154.789 ;
     RECT  132 152.819 132.312 155.029 ;
     RECT  145.2 150.709 146.184 155.029 ;
     RECT  156.768 154.261 156.792 155.651 ;
     RECT  153.6 2.151 153.912 155.701 ;
     RECT  134.688 155.365 134.712 155.843 ;
     RECT  136.512 154.789 137.832 155.891 ;
     RECT  144.768 155.029 146.184 156.227 ;
     RECT  150.576 153.059 150.6 156.227 ;
     RECT  153.6 155.701 154.392 156.755 ;
     RECT  131.856 155.029 132.312 156.757 ;
     RECT  131.856 156.757 132.792 156.803 ;
     RECT  148.08 153.877 148.512 156.899 ;
     RECT  140.832 151.525 143.688 157.189 ;
     RECT  129.696 156.133 129.72 157.811 ;
     RECT  132 156.803 132.792 158.005 ;
     RECT  131.904 158.005 132.792 158.339 ;
     RECT  136.512 155.891 137.712 158.435 ;
     RECT  152.304 157.861 152.328 158.437 ;
     RECT  151.632 158.437 152.328 158.483 ;
     RECT  153.6 156.755 153.912 158.533 ;
     RECT  140.832 157.189 143.928 158.579 ;
     RECT  148.2 156.899 148.512 158.965 ;
     RECT  134.64 158.341 134.664 159.011 ;
     RECT  139.44 157.861 139.464 159.061 ;
     RECT  140.832 158.579 143.688 159.061 ;
     RECT  139.44 159.061 143.688 159.107 ;
     RECT  152.736 158.533 153.912 159.395 ;
     RECT  126.6 2.151 126.912 159.541 ;
     RECT  157.392 156.421 157.416 159.635 ;
     RECT  136.704 158.435 137.712 160.211 ;
     RECT  137.4 160.211 137.712 160.405 ;
     RECT  145.2 156.227 146.184 160.741 ;
     RECT  155.616 159.013 155.64 160.979 ;
     RECT  131.904 158.339 132.312 161.077 ;
     RECT  148.2 158.965 148.824 161.603 ;
     RECT  125.712 159.541 126.912 161.605 ;
     RECT  128.208 160.741 128.232 161.605 ;
     RECT  125.712 161.605 128.232 161.651 ;
     RECT  140.208 159.107 143.688 161.795 ;
     RECT  131.904 161.077 132.408 161.845 ;
     RECT  131.664 161.845 132.408 162.179 ;
     RECT  131.664 162.179 132.312 162.227 ;
     RECT  125.712 161.651 127.704 162.371 ;
     RECT  140.256 161.795 143.688 162.421 ;
     RECT  145.2 160.741 146.76 162.421 ;
     RECT  155.328 161.845 155.352 162.947 ;
     RECT  126.6 162.371 127.704 163.043 ;
     RECT  134.928 161.605 134.952 163.043 ;
     RECT  140.256 162.421 146.76 163.043 ;
     RECT  151.632 158.483 151.656 163.043 ;
     RECT  137.4 160.405 137.928 163.283 ;
     RECT  140.688 163.043 146.76 163.379 ;
     RECT  137.4 163.283 137.712 163.861 ;
     RECT  136.752 163.861 137.712 163.957 ;
     RECT  126.6 163.043 126.912 164.149 ;
     RECT  132 162.227 132.312 164.245 ;
     RECT  122.544 161.749 122.568 164.339 ;
     RECT  151.776 163.813 151.8 164.917 ;
     RECT  151.776 164.917 152.04 164.963 ;
     RECT  126 164.149 126.912 165.061 ;
     RECT  126 165.061 127.368 165.347 ;
     RECT  145.2 163.379 146.76 165.589 ;
     RECT  153.6 159.395 153.912 165.877 ;
     RECT  136.368 163.957 137.712 165.923 ;
     RECT  149.856 164.677 149.88 165.923 ;
     RECT  156.144 165.061 156.168 166.211 ;
     RECT  145.2 165.589 147.048 166.213 ;
     RECT  148.2 161.603 148.512 166.213 ;
     RECT  136.368 165.923 136.392 166.261 ;
     RECT  136.272 166.261 136.392 166.307 ;
     RECT  153.6 165.877 154.344 166.451 ;
     RECT  126.6 165.347 127.368 166.499 ;
     RECT  137.4 165.923 137.712 166.501 ;
     RECT  122.928 164.725 122.952 166.547 ;
     RECT  115.8 2.151 116.112 166.981 ;
     RECT  152.016 164.963 152.04 167.029 ;
     RECT  145.2 166.213 148.512 167.075 ;
     RECT  151.44 167.029 152.04 167.075 ;
     RECT  124.8 165.253 124.824 167.315 ;
     RECT  131.664 164.245 132.312 167.317 ;
     RECT  137.4 166.501 137.832 167.363 ;
     RECT  140.688 163.379 143.688 167.365 ;
     RECT  129.216 166.405 129.24 167.459 ;
     RECT  131.04 167.317 132.312 167.507 ;
     RECT  136.272 166.307 136.296 167.747 ;
     RECT  145.2 167.075 147.048 167.843 ;
     RECT  149.568 167.557 149.592 168.035 ;
     RECT  126.6 166.499 126.912 168.085 ;
     RECT  138.96 166.117 138.984 168.659 ;
     RECT  140.208 167.365 143.688 168.805 ;
     RECT  145.2 167.843 146.76 168.805 ;
     RECT  137.4 167.363 137.712 168.853 ;
     RECT  128.496 167.557 128.856 169.141 ;
     RECT  130.8 169.093 130.824 169.237 ;
     RECT  126.6 168.085 127.032 169.379 ;
     RECT  140.208 168.805 146.76 169.813 ;
     RECT  128.496 169.141 129.144 169.859 ;
     RECT  137.4 168.853 138.36 169.907 ;
     RECT  157.344 168.901 157.368 169.907 ;
     RECT  137.4 169.907 137.832 170.245 ;
     RECT  130.128 169.237 130.824 170.291 ;
     RECT  103.536 166.645 103.56 170.293 ;
     RECT  105 2.151 105.312 170.389 ;
     RECT  128.496 169.859 128.52 170.437 ;
     RECT  148.2 167.075 148.512 170.437 ;
     RECT  126.6 169.379 126.912 170.821 ;
     RECT  104.832 170.389 105.312 170.867 ;
     RECT  140.208 169.813 146.952 170.965 ;
     RECT  153.6 166.451 153.912 171.013 ;
     RECT  148.032 170.437 148.512 171.059 ;
     RECT  136.608 170.245 137.832 171.107 ;
     RECT  153.504 171.013 153.912 171.347 ;
     RECT  139.344 170.965 146.952 171.397 ;
     RECT  132 167.507 132.312 171.445 ;
     RECT  151.44 167.075 151.464 171.491 ;
     RECT  157.296 170.965 157.32 171.731 ;
     RECT  103.536 170.293 103.608 171.925 ;
     RECT  103.488 171.925 103.608 171.971 ;
     RECT  138.96 171.397 146.952 172.117 ;
     RECT  148.2 171.059 148.512 172.117 ;
     RECT  123.696 170.869 123.72 172.163 ;
     RECT  149.52 169.621 149.544 172.309 ;
     RECT  134.112 168.085 134.136 172.501 ;
     RECT  135.552 171.589 135.576 172.501 ;
     RECT  126.6 170.821 127.32 172.645 ;
     RECT  128.352 170.437 128.52 172.645 ;
     RECT  103.488 171.971 103.56 172.739 ;
     RECT  138.96 172.117 148.512 172.883 ;
     RECT  139.056 172.883 148.512 173.077 ;
     RECT  149.52 172.309 150.456 173.077 ;
     RECT  136.608 171.107 137.712 173.317 ;
     RECT  96.672 172.645 96.696 173.363 ;
     RECT  101.088 171.925 101.112 173.363 ;
     RECT  105 170.867 105.312 173.413 ;
     RECT  126.6 172.645 128.52 173.459 ;
     RECT  139.056 173.077 150.456 173.557 ;
     RECT  134.112 172.501 135.576 173.605 ;
     RECT  136.608 173.317 137.88 173.605 ;
     RECT  139.056 173.557 150.744 173.747 ;
     RECT  134.112 173.605 137.88 173.797 ;
     RECT  150.72 173.747 150.744 173.797 ;
     RECT  99.6 2.151 99.912 173.941 ;
     RECT  121.2 2.151 121.512 174.181 ;
     RECT  156 173.173 156.024 174.419 ;
     RECT  139.056 173.747 149.544 174.421 ;
     RECT  128.352 173.459 128.52 174.467 ;
     RECT  123.648 173.509 123.672 174.515 ;
     RECT  104.832 173.413 105.312 174.659 ;
     RECT  150.72 173.797 151.368 174.803 ;
     RECT  99.6 173.941 100.008 175.091 ;
     RECT  126.6 173.459 126.912 175.093 ;
     RECT  128.352 174.467 128.376 175.093 ;
     RECT  157.392 173.173 157.416 175.139 ;
     RECT  138.912 174.421 149.544 175.381 ;
     RECT  150.72 174.803 150.744 175.381 ;
     RECT  103.536 172.739 103.56 175.619 ;
     RECT  164.4 2.151 164.712 176.005 ;
     RECT  99.6 175.091 99.912 176.101 ;
     RECT  131.328 171.445 132.312 176.101 ;
     RECT  125.376 172.117 125.4 176.147 ;
     RECT  138.912 175.381 150.744 176.195 ;
     RECT  130.128 170.291 130.152 176.197 ;
     RECT  131.136 176.101 132.312 176.197 ;
     RECT  164.4 176.005 165.288 176.387 ;
     RECT  134.112 173.797 137.928 176.389 ;
     RECT  138.912 176.195 149.544 176.389 ;
     RECT  105 174.659 105.312 176.485 ;
     RECT  150.72 176.195 150.744 177.059 ;
     RECT  97.056 176.101 97.08 177.205 ;
     RECT  104.832 176.485 105.312 177.205 ;
     RECT  104.832 177.205 105.48 177.251 ;
     RECT  125.568 176.677 125.592 177.299 ;
     RECT  133.488 176.389 149.544 177.445 ;
     RECT  123.888 176.677 123.912 177.491 ;
     RECT  126.6 175.093 128.376 177.781 ;
     RECT  98.64 176.101 99.912 177.875 ;
     RECT  105 177.251 105.48 177.875 ;
     RECT  106.848 170.965 106.872 178.019 ;
     RECT  155.664 177.781 155.688 178.403 ;
     RECT  108.768 177.301 108.792 178.501 ;
     RECT  110.4 2.151 110.712 178.501 ;
     RECT  108.768 178.501 110.712 178.547 ;
     RECT  159 2.151 159.312 178.645 ;
     RECT  94.2 2.151 94.512 178.933 ;
     RECT  103.056 178.645 103.08 179.075 ;
     RECT  133.488 177.445 150.504 179.075 ;
     RECT  130.128 176.197 132.312 179.413 ;
     RECT  94.2 178.933 95.064 179.795 ;
     RECT  96.864 177.205 97.08 179.891 ;
     RECT  126.6 177.781 128.52 180.085 ;
     RECT  99.6 177.875 99.912 180.133 ;
     RECT  105 177.875 105.312 180.181 ;
     RECT  151.824 180.181 151.848 180.323 ;
     RECT  94.2 179.795 94.68 180.707 ;
     RECT  104.256 180.181 105.312 180.707 ;
     RECT  99.6 180.133 100.392 180.755 ;
     RECT  121.2 174.181 122.376 180.755 ;
     RECT  109.68 178.547 110.712 181.237 ;
     RECT  133.488 179.075 149.544 181.237 ;
     RECT  106.56 178.933 106.584 181.475 ;
     RECT  115.8 166.981 116.232 181.667 ;
     RECT  103.968 181.093 103.992 181.811 ;
     RECT  129.6 179.413 132.312 182.149 ;
     RECT  133.296 181.237 149.544 182.149 ;
     RECT  125.808 180.085 128.52 182.195 ;
     RECT  99.6 180.755 100.008 182.341 ;
     RECT  129.6 182.149 149.544 182.387 ;
     RECT  130.128 182.387 149.544 182.531 ;
     RECT  125.808 182.195 127.032 182.579 ;
     RECT  97.056 179.891 97.08 182.627 ;
     RECT  109.2 181.237 110.712 182.627 ;
     RECT  95.76 182.149 95.784 182.771 ;
     RECT  105 180.707 105.312 182.917 ;
     RECT  99.6 182.341 100.296 183.011 ;
     RECT  126.6 182.579 127.032 183.011 ;
     RECT  102.48 181.813 102.504 183.107 ;
     RECT  130.128 182.531 132.312 183.541 ;
     RECT  102.048 183.349 102.072 183.587 ;
     RECT  121.2 180.755 122.232 184.021 ;
     RECT  94.2 180.707 94.512 184.069 ;
     RECT  126.6 183.011 126.912 184.069 ;
     RECT  133.296 182.531 149.544 184.069 ;
     RECT  106.56 182.629 106.584 184.451 ;
     RECT  104.16 182.917 105.312 184.739 ;
     RECT  130.08 183.541 132.312 185.125 ;
     RECT  94.032 184.069 94.512 185.173 ;
     RECT  94.032 185.173 95.352 185.315 ;
     RECT  158.016 178.645 159.312 185.315 ;
     RECT  120.384 184.021 122.232 185.603 ;
     RECT  153.6 171.347 153.912 185.797 ;
     RECT  128.064 182.195 128.52 186.133 ;
     RECT  130.032 185.125 132.312 186.133 ;
     RECT  128.064 186.133 132.312 186.275 ;
     RECT  94.2 185.315 95.352 186.371 ;
     RECT  120.72 185.603 122.232 186.371 ;
     RECT  150.912 185.413 150.936 186.419 ;
     RECT  101.952 185.941 101.976 186.467 ;
     RECT  103.2 185.941 103.224 186.467 ;
     RECT  123.648 182.533 123.672 186.707 ;
     RECT  106.608 185.461 106.632 187.475 ;
     RECT  105 184.739 105.312 187.477 ;
     RECT  101.904 186.901 101.928 187.571 ;
     RECT  109.872 182.627 110.712 187.669 ;
     RECT  130.032 186.275 132.312 187.717 ;
     RECT  133.296 184.069 149.592 187.717 ;
     RECT  120.72 186.371 122.136 188.147 ;
     RECT  105 187.477 105.432 188.293 ;
     RECT  130.032 187.717 149.592 188.437 ;
     RECT  156.384 185.221 156.408 188.437 ;
     RECT  109.632 187.669 110.712 188.531 ;
     RECT  94.2 186.371 94.512 188.533 ;
     RECT  130.032 188.437 150.264 188.581 ;
     RECT  95.904 187.477 95.928 188.723 ;
     RECT  128.064 186.275 128.52 188.723 ;
     RECT  110.4 188.531 110.712 189.061 ;
     RECT  110.4 189.061 110.808 189.205 ;
     RECT  94.08 188.533 94.512 189.299 ;
     RECT  121.2 188.147 122.136 189.299 ;
     RECT  123.696 187.573 123.72 189.299 ;
     RECT  126.6 184.069 127.032 189.395 ;
     RECT  98.496 188.773 98.52 189.493 ;
     RECT  97.824 189.493 98.52 189.587 ;
     RECT  99.6 183.011 100.008 189.733 ;
     RECT  105 188.293 106.008 189.875 ;
     RECT  159 185.315 159.312 190.021 ;
     RECT  128.352 188.723 128.52 190.163 ;
     RECT  97.824 189.587 97.848 190.403 ;
     RECT  107.76 189.829 107.784 190.451 ;
     RECT  99.6 189.733 100.296 190.739 ;
     RECT  110.4 189.205 111.768 190.979 ;
     RECT  122.496 189.877 122.52 190.979 ;
     RECT  155.28 190.981 155.304 191.123 ;
     RECT  105 189.875 105.48 191.219 ;
     RECT  129.984 188.581 150.264 191.221 ;
     RECT  151.392 188.629 151.416 191.221 ;
     RECT  129.984 191.221 151.416 191.267 ;
     RECT  105 191.219 105.312 191.365 ;
     RECT  129.984 191.267 149.592 191.365 ;
     RECT  128.352 190.163 128.376 191.459 ;
     RECT  94.2 189.299 94.512 191.461 ;
     RECT  129.504 191.365 149.592 191.507 ;
     RECT  133.296 191.507 149.592 191.795 ;
     RECT  151.008 191.267 151.416 191.891 ;
     RECT  129.504 191.507 132.312 192.179 ;
     RECT  94.2 191.461 95.208 192.323 ;
     RECT  123.696 192.037 123.72 192.659 ;
     RECT  129.792 192.179 132.312 192.661 ;
     RECT  133.296 191.795 149.544 192.661 ;
     RECT  104.304 191.365 105.312 192.707 ;
     RECT  106.608 191.173 106.632 192.707 ;
     RECT  122.496 192.037 122.52 192.707 ;
     RECT  97.488 190.789 97.512 192.803 ;
     RECT  129.792 192.661 149.544 192.947 ;
     RECT  126.6 189.395 126.912 193.189 ;
     RECT  130.08 192.947 149.544 193.189 ;
     RECT  130.08 193.189 149.784 193.283 ;
     RECT  99.6 190.739 99.912 193.381 ;
     RECT  99.504 193.381 99.912 194.771 ;
     RECT  102.576 193.765 102.6 194.963 ;
     RECT  101.088 194.917 101.112 195.061 ;
     RECT  130.128 193.283 149.784 195.395 ;
     RECT  151.008 191.891 151.032 195.733 ;
     RECT  150.864 195.733 151.032 195.779 ;
     RECT  100.896 195.061 101.112 195.781 ;
     RECT  100.896 195.781 101.208 195.827 ;
     RECT  103.92 195.445 103.944 195.971 ;
     RECT  119.664 195.877 119.688 196.355 ;
     RECT  99.6 194.771 99.912 196.453 ;
     RECT  101.088 195.827 101.208 196.499 ;
     RECT  123.36 195.781 123.384 196.691 ;
     RECT  152.16 195.925 152.184 196.691 ;
     RECT  130.128 195.395 130.824 197.219 ;
     RECT  158.208 190.021 159.312 197.509 ;
     RECT  121.2 189.299 121.512 197.749 ;
     RECT  131.904 195.395 149.784 197.749 ;
     RECT  150.864 195.779 150.888 197.749 ;
     RECT  105 192.707 105.312 198.373 ;
     RECT  99.504 196.453 99.912 198.419 ;
     RECT  101.184 196.499 101.208 198.419 ;
     RECT  130.128 197.219 130.776 198.517 ;
     RECT  121.2 197.749 122.184 199.091 ;
     RECT  129.984 198.517 130.776 199.091 ;
     RECT  157.488 197.509 159.312 199.571 ;
     RECT  130.128 199.091 130.776 199.573 ;
     RECT  123.312 197.077 123.336 200.005 ;
     RECT  105 198.373 105.528 200.147 ;
     RECT  152.064 197.173 152.088 200.147 ;
     RECT  156.384 188.437 156.456 200.581 ;
     RECT  158.208 199.571 159.312 200.581 ;
     RECT  123.312 200.005 124.296 200.675 ;
     RECT  128.256 199.621 128.28 200.675 ;
     RECT  130.128 199.573 130.872 200.675 ;
     RECT  156.384 200.581 159.312 200.675 ;
     RECT  131.904 197.749 150.888 201.109 ;
     RECT  131.904 201.109 151.032 201.251 ;
     RECT  156.384 200.675 157.368 201.443 ;
     RECT  151.008 201.251 151.032 201.587 ;
     RECT  123.312 200.675 123.336 201.733 ;
     RECT  123.312 201.733 123.72 202.885 ;
     RECT  159 200.675 159.312 202.885 ;
     RECT  123.312 202.885 124.056 202.979 ;
     RECT  131.904 201.251 149.976 203.317 ;
     RECT  124.032 202.979 124.056 203.507 ;
     RECT  125.904 193.189 126.912 203.509 ;
     RECT  158.592 202.885 159.312 203.843 ;
     RECT  130.128 200.675 130.776 203.941 ;
     RECT  131.76 203.317 149.976 203.941 ;
     RECT  156.384 201.443 156.456 204.037 ;
     RECT  130.128 203.941 149.976 204.179 ;
     RECT  131.76 204.179 143.256 204.323 ;
     RECT  144.24 204.179 149.976 204.467 ;
     RECT  149.52 204.467 149.976 204.515 ;
     RECT  144.24 204.467 148.512 204.995 ;
     RECT  125.904 203.509 127.704 205.187 ;
     RECT  144.432 204.995 148.512 205.619 ;
     RECT  121.2 199.091 121.512 206.149 ;
     RECT  131.904 204.323 143.256 206.197 ;
     RECT  130.128 204.179 130.776 206.293 ;
     RECT  131.76 206.197 143.256 206.387 ;
     RECT  156.192 204.037 156.456 206.485 ;
     RECT  159 203.843 159.312 206.821 ;
     RECT  121.2 206.149 122.088 206.917 ;
     RECT  123.696 206.293 123.72 207.059 ;
     RECT  144.432 205.619 144.984 207.251 ;
     RECT  121.2 206.917 122.232 207.539 ;
     RECT  156.144 206.485 156.456 207.539 ;
     RECT  158.064 206.821 159.312 207.539 ;
     RECT  144.432 207.251 144.696 208.549 ;
     RECT  121.2 207.539 121.512 208.597 ;
     RECT  131.904 206.387 143.256 208.643 ;
     RECT  144.432 208.549 144.792 208.739 ;
     RECT  149.568 204.515 149.976 209.077 ;
     RECT  121.2 208.597 121.992 209.219 ;
     RECT  124.272 208.021 124.296 209.315 ;
     RECT  131.904 208.643 134.136 209.411 ;
     RECT  146.064 205.619 148.512 209.701 ;
     RECT  149.568 209.077 150.168 209.701 ;
     RECT  146.064 209.701 150.168 209.891 ;
     RECT  146.064 209.891 150.072 210.371 ;
     RECT  156.384 207.539 156.456 210.371 ;
     RECT  146.064 210.371 148.632 210.419 ;
     RECT  146.256 210.419 148.632 210.707 ;
     RECT  129.264 206.293 130.776 211.283 ;
     RECT  133.344 209.411 134.136 211.331 ;
     RECT  131.904 209.411 132.312 211.427 ;
     RECT  146.256 210.707 148.512 211.811 ;
     RECT  149.904 210.371 150.072 211.957 ;
     RECT  149.808 211.957 150.072 212.003 ;
     RECT  135.408 208.643 143.256 212.005 ;
     RECT  133.488 211.331 134.136 212.099 ;
     RECT  147.024 211.811 148.512 212.099 ;
     RECT  151.68 210.277 151.704 212.293 ;
     RECT  151.248 212.293 151.704 212.339 ;
     RECT  156.384 210.371 156.408 212.389 ;
     RECT  144.72 212.389 144.744 212.485 ;
     RECT  151.248 212.339 151.272 212.723 ;
     RECT  133.488 212.099 133.848 212.771 ;
     RECT  144.72 212.485 144.792 212.819 ;
     RECT  130.032 211.283 130.776 213.059 ;
     RECT  156.144 212.389 156.408 213.157 ;
     RECT  133.488 212.771 133.608 213.203 ;
     RECT  124.896 213.109 124.92 213.731 ;
     RECT  144.72 212.819 144.744 213.971 ;
     RECT  149.808 212.003 149.976 214.019 ;
     RECT  149.904 214.019 149.976 214.067 ;
     RECT  155.472 213.157 156.408 214.211 ;
     RECT  132 211.427 132.312 214.213 ;
     RECT  147.072 212.099 148.512 214.355 ;
     RECT  135.408 212.005 143.448 214.693 ;
     RECT  147.072 214.355 147.096 214.741 ;
     RECT  125.904 205.187 126.912 214.837 ;
     RECT  147.024 214.741 147.096 215.219 ;
     RECT  147.024 215.219 147.048 215.507 ;
     RECT  125.904 214.837 127.656 215.797 ;
     RECT  133.584 213.203 133.608 215.989 ;
     RECT  133.392 215.989 133.608 216.035 ;
     RECT  149.904 214.067 149.928 216.037 ;
     RECT  156.144 214.211 156.408 216.037 ;
     RECT  149.904 216.037 150.072 216.083 ;
     RECT  146.4 216.037 146.424 216.179 ;
     RECT  153.6 185.797 154.104 216.229 ;
     RECT  130.128 213.059 130.776 216.325 ;
     RECT  133.392 216.035 133.416 216.371 ;
     RECT  144.768 216.517 144.792 216.565 ;
     RECT  135.36 214.693 143.448 216.613 ;
     RECT  144.768 216.565 145.272 216.659 ;
     RECT  129.168 216.325 130.776 216.661 ;
     RECT  125.136 215.797 127.656 216.707 ;
     RECT  155.856 216.037 156.408 216.707 ;
     RECT  153.408 216.229 154.104 217.331 ;
     RECT  150.048 216.083 150.072 217.379 ;
     RECT  145.248 216.659 145.272 217.427 ;
     RECT  134.544 216.613 143.448 217.763 ;
     RECT  148.2 214.355 148.512 217.909 ;
     RECT  128.64 216.661 130.776 217.955 ;
     RECT  125.136 216.707 126.912 218.149 ;
     RECT  148.08 217.909 148.512 218.243 ;
     RECT  125.136 218.149 127.272 218.291 ;
     RECT  135.024 217.763 143.448 218.339 ;
     RECT  153.6 217.331 154.104 218.339 ;
     RECT  132 214.213 132.408 218.387 ;
     RECT  135.024 218.339 135.432 218.915 ;
     RECT  125.136 218.291 127.176 219.059 ;
     RECT  152.208 217.285 152.232 219.059 ;
     RECT  157.104 218.341 157.128 219.059 ;
     RECT  136.56 218.339 143.448 219.397 ;
     RECT  155.856 216.707 155.88 219.491 ;
     RECT  132 218.387 132.312 219.685 ;
     RECT  150.48 218.245 150.504 219.875 ;
     RECT  125.136 219.059 126.912 220.067 ;
     RECT  136.56 219.397 143.592 220.163 ;
     RECT  135.408 218.915 135.432 220.357 ;
     RECT  144.768 220.453 144.792 220.643 ;
     RECT  136.56 220.163 143.448 220.691 ;
     RECT  132 219.685 132.408 221.171 ;
     RECT  153.6 218.339 154.008 221.219 ;
     RECT  145.44 221.557 145.464 221.699 ;
     RECT  141.648 220.691 143.448 222.133 ;
     RECT  150.48 222.181 150.504 222.323 ;
     RECT  134.592 220.357 135.432 222.371 ;
     RECT  146.784 217.525 146.808 222.515 ;
     RECT  135.408 222.371 135.432 222.805 ;
     RECT  136.56 220.691 140.616 222.805 ;
     RECT  141.648 222.133 143.688 222.805 ;
     RECT  135.408 222.805 140.616 224.435 ;
     RECT  129.168 217.955 130.776 224.533 ;
     RECT  132 221.171 132.312 224.533 ;
     RECT  141.648 222.805 143.832 224.533 ;
     RECT  145.728 222.805 145.752 224.533 ;
     RECT  141.648 224.533 145.752 224.675 ;
     RECT  144.864 224.675 145.752 224.819 ;
     RECT  129.168 224.533 132.312 224.965 ;
     RECT  129.168 224.965 132.792 225.203 ;
     RECT  125.904 220.067 126.912 225.349 ;
     RECT  152.256 223.957 152.28 225.539 ;
     RECT  128.064 223.957 128.088 225.731 ;
     RECT  148.2 218.243 148.512 226.405 ;
     RECT  125.904 225.349 127.032 226.451 ;
     RECT  132 225.203 132.792 226.883 ;
     RECT  146.496 225.589 146.52 226.883 ;
     RECT  135.408 224.435 135.432 226.981 ;
     RECT  148.2 226.405 148.632 227.507 ;
     RECT  129.168 225.203 130.776 227.651 ;
     RECT  129.168 227.651 130.152 227.747 ;
     RECT  141.648 224.675 143.832 228.517 ;
     RECT  144.864 224.819 144.888 228.517 ;
     RECT  148.2 227.507 148.512 228.517 ;
     RECT  141.648 228.517 144.888 228.563 ;
     RECT  132 226.883 132.408 228.611 ;
     RECT  141.648 228.563 144.792 228.611 ;
     RECT  148.2 228.517 148.776 229.571 ;
     RECT  141.648 228.611 143.784 229.763 ;
     RECT  141.84 229.763 143.784 230.147 ;
     RECT  136.56 224.435 140.616 230.339 ;
     RECT  134.496 226.981 135.432 230.387 ;
     RECT  128.496 230.293 128.52 230.867 ;
     RECT  140.592 230.339 140.616 231.445 ;
     RECT  148.2 229.571 148.512 231.445 ;
     RECT  130.128 227.747 130.152 231.925 ;
     RECT  136.56 230.339 139.32 231.925 ;
     RECT  141.84 230.147 143.448 231.971 ;
     RECT  130.128 231.925 130.776 232.019 ;
     RECT  134.4 231.205 134.424 232.307 ;
     RECT  148.2 231.445 148.728 232.403 ;
     RECT  128.592 231.301 128.616 232.405 ;
     RECT  128.592 232.405 128.856 232.451 ;
     RECT  136.56 231.925 139.368 232.501 ;
     RECT  140.544 231.445 140.616 232.501 ;
     RECT  136.56 232.501 140.616 232.547 ;
     RECT  152.16 231.253 152.184 233.459 ;
     RECT  142.128 231.971 143.448 233.653 ;
     RECT  144.768 228.611 144.792 233.653 ;
     RECT  130.752 232.019 130.776 233.987 ;
     RECT  142.128 233.653 144.792 233.987 ;
     RECT  139.248 232.547 140.616 234.229 ;
     RECT  139.248 234.229 140.952 234.275 ;
     RECT  139.248 234.275 139.368 234.323 ;
     RECT  140.592 234.275 140.952 234.371 ;
     RECT  132 228.611 132.312 234.805 ;
     RECT  128.832 232.451 128.856 234.899 ;
     RECT  130.56 234.229 130.584 235.571 ;
     RECT  140.592 234.371 140.616 236.005 ;
     RECT  132 234.805 133.032 236.579 ;
     RECT  139.296 234.323 139.368 236.579 ;
     RECT  142.128 233.987 143.448 236.579 ;
     RECT  140.592 236.005 140.76 236.723 ;
     RECT  148.2 232.403 148.632 237.251 ;
     RECT  136.56 232.547 137.712 237.733 ;
     RECT  139.344 236.579 139.368 237.733 ;
     RECT  144.768 233.987 144.792 237.971 ;
     RECT  136.56 237.733 139.368 238.213 ;
     RECT  140.592 236.723 140.616 238.213 ;
     RECT  135.408 230.387 135.432 238.259 ;
     RECT  136.56 238.213 140.616 238.355 ;
     RECT  147.12 238.213 147.144 238.499 ;
     RECT  132 236.579 132.408 238.741 ;
     RECT  139.344 238.355 140.616 238.883 ;
     RECT  136.56 238.355 137.712 239.029 ;
     RECT  136.224 239.029 137.712 239.123 ;
     RECT  139.344 238.883 139.368 239.555 ;
     RECT  140.592 238.883 140.616 239.941 ;
     RECT  142.128 236.579 143.112 239.941 ;
     RECT  132 238.741 132.552 239.987 ;
     RECT  136.224 239.123 136.248 240.515 ;
     RECT  140.592 239.941 143.112 240.563 ;
     RECT  141.312 240.563 143.112 241.043 ;
     RECT  145.296 239.941 145.32 242.819 ;
     RECT  134.256 241.621 134.28 243.349 ;
     RECT  133.968 243.349 134.28 243.395 ;
     RECT  133.968 243.395 133.992 244.595 ;
     RECT  135.744 241.045 135.768 244.739 ;
     RECT  142.128 241.043 143.112 245.029 ;
     RECT  142.128 245.029 143.688 245.651 ;
     RECT  142.128 245.651 143.304 245.699 ;
     RECT  137.4 239.123 137.712 246.037 ;
     RECT  139.392 239.941 139.416 246.037 ;
     RECT  132 239.987 132.312 246.421 ;
     RECT  137.4 246.037 139.416 247.189 ;
     RECT  137.4 247.189 139.656 247.235 ;
     RECT  140.736 246.181 140.76 247.333 ;
     RECT  142.656 245.699 143.304 247.333 ;
     RECT  139.632 247.235 139.656 247.379 ;
     RECT  142.512 247.333 143.304 248.579 ;
     RECT  140.736 247.333 141.48 248.771 ;
     RECT  137.4 247.235 138.552 249.253 ;
     RECT  137.4 249.253 139.032 249.299 ;
     RECT  139.008 249.299 139.032 249.683 ;
     RECT  142.656 248.579 143.304 250.165 ;
     RECT  142.656 250.165 143.64 250.355 ;
     RECT  142.8 250.355 143.64 251.363 ;
     RECT  140.736 248.771 140.76 252.131 ;
     RECT  125.904 226.451 126.912 277.715 ;
     RECT  2.4 2.151 2.712 369.369 ;
     RECT  7.8 2.151 8.112 369.369 ;
     RECT  13.2 2.151 13.512 369.369 ;
     RECT  18.6 2.151 18.912 369.369 ;
     RECT  24 2.151 24.312 369.369 ;
     RECT  29.4 2.151 29.712 369.369 ;
     RECT  34.8 2.151 35.112 369.369 ;
     RECT  40.2 2.151 40.512 369.369 ;
     RECT  45.6 2.151 45.912 369.369 ;
     RECT  51 2.151 51.312 369.369 ;
     RECT  56.4 2.151 56.712 369.369 ;
     RECT  61.8 2.151 62.112 369.369 ;
     RECT  67.2 2.151 67.512 369.369 ;
     RECT  72.6 2.151 72.912 369.369 ;
     RECT  78 2.151 78.312 369.369 ;
     RECT  83.4 2.151 83.712 369.369 ;
     RECT  88.8 2.151 89.112 369.369 ;
     RECT  94.2 192.323 94.512 369.369 ;
     RECT  99.6 198.419 99.912 369.369 ;
     RECT  105 200.147 105.312 369.369 ;
     RECT  110.4 190.979 110.712 369.369 ;
     RECT  115.8 181.667 116.112 369.369 ;
     RECT  121.2 209.219 121.512 369.369 ;
     RECT  126.6 277.715 126.912 369.369 ;
     RECT  137.4 249.299 137.712 369.369 ;
     RECT  142.8 251.363 143.112 369.369 ;
     RECT  148.2 237.251 148.512 369.369 ;
     RECT  153.6 221.219 153.912 369.369 ;
     RECT  159 207.539 159.312 369.369 ;
     RECT  164.4 176.387 164.712 369.369 ;
     RECT  169.8 2.151 170.112 369.369 ;
     RECT  175.2 2.151 175.512 369.369 ;
     RECT  180.6 2.151 180.912 369.369 ;
     RECT  186 2.151 186.312 369.369 ;
     RECT  191.4 2.151 191.712 369.369 ;
     RECT  196.8 2.151 197.112 369.369 ;
     RECT  202.2 2.151 202.512 369.369 ;
     RECT  207.6 2.151 207.912 369.369 ;
     RECT  213 2.151 213.312 369.369 ;
     RECT  218.4 2.151 218.712 369.369 ;
     RECT  223.8 2.151 224.112 369.369 ;
     RECT  229.2 2.151 229.512 369.369 ;
     RECT  234.6 2.151 234.912 369.369 ;
     RECT  240 2.151 240.312 369.369 ;
     RECT  245.4 2.151 245.712 369.369 ;
     RECT  2.4 369.369 2.52 369.383 ;
     RECT  7.8 369.369 7.92 369.383 ;
     RECT  13.2 369.369 13.32 369.383 ;
     RECT  18.6 369.369 18.72 369.383 ;
     RECT  24 369.369 24.12 369.383 ;
     RECT  29.4 369.369 29.52 369.383 ;
     RECT  34.8 369.369 34.92 369.383 ;
     RECT  40.2 369.369 40.32 369.383 ;
     RECT  45.6 369.369 45.72 369.383 ;
     RECT  51 369.369 51.12 369.383 ;
     RECT  56.4 369.369 56.52 369.383 ;
     RECT  61.8 369.369 61.92 369.383 ;
     RECT  67.2 369.369 67.32 369.383 ;
     RECT  72.6 369.369 72.72 369.383 ;
     RECT  78 369.369 78.12 369.383 ;
     RECT  83.4 369.369 83.52 369.383 ;
     RECT  88.8 369.369 88.92 369.383 ;
     RECT  94.2 369.369 94.32 369.383 ;
     RECT  99.6 369.369 99.72 369.383 ;
     RECT  105 369.369 105.12 369.383 ;
     RECT  110.4 369.369 110.52 369.383 ;
     RECT  115.8 369.369 115.92 369.383 ;
     RECT  121.2 369.369 121.32 369.383 ;
     RECT  126.6 369.369 126.72 369.383 ;
     RECT  132 246.421 132.552 369.383 ;
     RECT  137.4 369.369 137.52 369.383 ;
     RECT  142.8 369.369 142.92 369.383 ;
     RECT  148.2 369.369 148.32 369.383 ;
     RECT  153.6 369.369 153.72 369.383 ;
     RECT  159 369.369 159.12 369.383 ;
     RECT  164.4 369.369 164.52 369.383 ;
     RECT  169.8 369.369 169.92 369.383 ;
     RECT  175.2 369.369 175.32 369.383 ;
     RECT  180.6 369.369 180.72 369.383 ;
     RECT  186 369.369 186.12 369.383 ;
     RECT  191.4 369.369 191.52 369.383 ;
     RECT  196.8 369.369 196.92 369.383 ;
     RECT  202.2 369.369 202.32 369.383 ;
     RECT  207.6 369.369 207.72 369.383 ;
     RECT  213 369.369 213.12 369.383 ;
     RECT  218.4 369.369 218.52 369.383 ;
     RECT  223.8 369.369 223.92 369.383 ;
     RECT  229.2 369.369 229.32 369.383 ;
     RECT  234.6 369.369 234.72 369.383 ;
     RECT  240 369.369 240.12 369.383 ;
     RECT  245.4 369.369 245.52 369.383 ;
     RECT  132.432 369.383 132.552 371.173 ;
     RECT  132.336 371.173 132.552 371.269 ;
     RECT  132.24 371.269 132.552 371.365 ;
     RECT  132.144 371.365 132.552 371.411 ;
     RECT  132.144 371.411 132.456 371.472 ;
  END
END ot_qwen_ctrl_pc_head
END LIBRARY
